VERSION 5.8 ;
BUSBITCHARS "[]" ;
DIVIDERCHAR "/" ;
UNITS
    DATABASE MICRONS 1000 ;
END UNITS

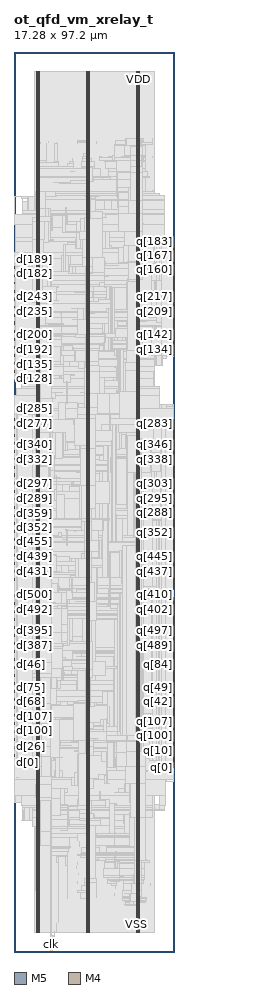
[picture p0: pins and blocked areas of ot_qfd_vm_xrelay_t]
MACRO ot_qfd_vm_xrelay_t
  FOREIGN ot_qfd_vm_xrelay_t 0 0 ;
  CLASS BLOCK ;
  SIZE 17.28 BY 97.2 ;
  PIN clk
    DIRECTION INPUT ;
    USE SIGNAL ;
    PORT
      LAYER M5 ;
        RECT  3.984 0 4.008 0.084 ;
    END
  END clk
  PIN d[0]
    DIRECTION INPUT ;
    USE SIGNAL ;
    PORT
      LAYER M4 ;
        RECT  0 20.496 0.084 20.52 ;
    END
  END d[0]
  PIN d[100]
    DIRECTION INPUT ;
    USE SIGNAL ;
    PORT
      LAYER M4 ;
        RECT  0 23.952 0.084 23.976 ;
    END
  END d[100]
  PIN d[101]
    DIRECTION INPUT ;
    USE SIGNAL ;
    PORT
      LAYER M4 ;
        RECT  0 24.048 0.084 24.072 ;
    END
  END d[101]
  PIN d[102]
    DIRECTION INPUT ;
    USE SIGNAL ;
    PORT
      LAYER M4 ;
        RECT  0 24.144 0.084 24.168 ;
    END
  END d[102]
  PIN d[103]
    DIRECTION INPUT ;
    USE SIGNAL ;
    PORT
      LAYER M4 ;
        RECT  0 24.24 0.084 24.264 ;
    END
  END d[103]
  PIN d[104]
    DIRECTION INPUT ;
    USE SIGNAL ;
    PORT
      LAYER M4 ;
        RECT  0 24.336 0.084 24.36 ;
    END
  END d[104]
  PIN d[105]
    DIRECTION INPUT ;
    USE SIGNAL ;
    PORT
      LAYER M4 ;
        RECT  0 24.432 0.084 24.456 ;
    END
  END d[105]
  PIN d[106]
    DIRECTION INPUT ;
    USE SIGNAL ;
    PORT
      LAYER M4 ;
        RECT  0 24.528 0.084 24.552 ;
    END
  END d[106]
  PIN d[107]
    DIRECTION INPUT ;
    USE SIGNAL ;
    PORT
      LAYER M4 ;
        RECT  0 24.624 0.084 24.648 ;
    END
  END d[107]
  PIN d[108]
    DIRECTION INPUT ;
    USE SIGNAL ;
    PORT
      LAYER M4 ;
        RECT  0 24.72 0.084 24.744 ;
    END
  END d[108]
  PIN d[109]
    DIRECTION INPUT ;
    USE SIGNAL ;
    PORT
      LAYER M4 ;
        RECT  0 24.816 0.084 24.84 ;
    END
  END d[109]
  PIN d[10]
    DIRECTION INPUT ;
    USE SIGNAL ;
    PORT
      LAYER M4 ;
        RECT  0 21.456 0.084 21.48 ;
    END
  END d[10]
  PIN d[110]
    DIRECTION INPUT ;
    USE SIGNAL ;
    PORT
      LAYER M4 ;
        RECT  0 24.912 0.084 24.936 ;
    END
  END d[110]
  PIN d[111]
    DIRECTION INPUT ;
    USE SIGNAL ;
    PORT
      LAYER M4 ;
        RECT  0 25.008 0.084 25.032 ;
    END
  END d[111]
  PIN d[112]
    DIRECTION INPUT ;
    USE SIGNAL ;
    PORT
      LAYER M4 ;
        RECT  0 25.104 0.084 25.128 ;
    END
  END d[112]
  PIN d[113]
    DIRECTION INPUT ;
    USE SIGNAL ;
    PORT
      LAYER M4 ;
        RECT  0 25.2 0.084 25.224 ;
    END
  END d[113]
  PIN d[114]
    DIRECTION INPUT ;
    USE SIGNAL ;
    PORT
      LAYER M4 ;
        RECT  0 25.296 0.084 25.32 ;
    END
  END d[114]
  PIN d[115]
    DIRECTION INPUT ;
    USE SIGNAL ;
    PORT
      LAYER M4 ;
        RECT  0 25.392 0.084 25.416 ;
    END
  END d[115]
  PIN d[116]
    DIRECTION INPUT ;
    USE SIGNAL ;
    PORT
      LAYER M4 ;
        RECT  0 25.488 0.084 25.512 ;
    END
  END d[116]
  PIN d[117]
    DIRECTION INPUT ;
    USE SIGNAL ;
    PORT
      LAYER M4 ;
        RECT  0 25.584 0.084 25.608 ;
    END
  END d[117]
  PIN d[118]
    DIRECTION INPUT ;
    USE SIGNAL ;
    PORT
      LAYER M4 ;
        RECT  0 25.68 0.084 25.704 ;
    END
  END d[118]
  PIN d[119]
    DIRECTION INPUT ;
    USE SIGNAL ;
    PORT
      LAYER M4 ;
        RECT  0 25.776 0.084 25.8 ;
    END
  END d[119]
  PIN d[11]
    DIRECTION INPUT ;
    USE SIGNAL ;
    PORT
      LAYER M4 ;
        RECT  0 21.552 0.084 21.576 ;
    END
  END d[11]
  PIN d[120]
    DIRECTION INPUT ;
    USE SIGNAL ;
    PORT
      LAYER M4 ;
        RECT  0 25.872 0.084 25.896 ;
    END
  END d[120]
  PIN d[121]
    DIRECTION INPUT ;
    USE SIGNAL ;
    PORT
      LAYER M4 ;
        RECT  0 25.968 0.084 25.992 ;
    END
  END d[121]
  PIN d[122]
    DIRECTION INPUT ;
    USE SIGNAL ;
    PORT
      LAYER M4 ;
        RECT  0 26.064 0.084 26.088 ;
    END
  END d[122]
  PIN d[123]
    DIRECTION INPUT ;
    USE SIGNAL ;
    PORT
      LAYER M4 ;
        RECT  0 26.16 0.084 26.184 ;
    END
  END d[123]
  PIN d[124]
    DIRECTION INPUT ;
    USE SIGNAL ;
    PORT
      LAYER M4 ;
        RECT  0 26.256 0.084 26.28 ;
    END
  END d[124]
  PIN d[125]
    DIRECTION INPUT ;
    USE SIGNAL ;
    PORT
      LAYER M4 ;
        RECT  0 26.352 0.084 26.376 ;
    END
  END d[125]
  PIN d[126]
    DIRECTION INPUT ;
    USE SIGNAL ;
    PORT
      LAYER M4 ;
        RECT  0 26.448 0.084 26.472 ;
    END
  END d[126]
  PIN d[127]
    DIRECTION INPUT ;
    USE SIGNAL ;
    PORT
      LAYER M4 ;
        RECT  0 26.544 0.084 26.568 ;
    END
  END d[127]
  PIN d[128]
    DIRECTION INPUT ;
    USE SIGNAL ;
    PORT
      LAYER M4 ;
        RECT  0 61.968 0.084 61.992 ;
    END
  END d[128]
  PIN d[129]
    DIRECTION INPUT ;
    USE SIGNAL ;
    PORT
      LAYER M4 ;
        RECT  0 62.064 0.084 62.088 ;
    END
  END d[129]
  PIN d[12]
    DIRECTION INPUT ;
    USE SIGNAL ;
    PORT
      LAYER M4 ;
        RECT  0 21.648 0.084 21.672 ;
    END
  END d[12]
  PIN d[130]
    DIRECTION INPUT ;
    USE SIGNAL ;
    PORT
      LAYER M4 ;
        RECT  0 62.16 0.084 62.184 ;
    END
  END d[130]
  PIN d[131]
    DIRECTION INPUT ;
    USE SIGNAL ;
    PORT
      LAYER M4 ;
        RECT  0 62.256 0.084 62.28 ;
    END
  END d[131]
  PIN d[132]
    DIRECTION INPUT ;
    USE SIGNAL ;
    PORT
      LAYER M4 ;
        RECT  0 62.352 0.084 62.376 ;
    END
  END d[132]
  PIN d[133]
    DIRECTION INPUT ;
    USE SIGNAL ;
    PORT
      LAYER M4 ;
        RECT  0 62.448 0.084 62.472 ;
    END
  END d[133]
  PIN d[134]
    DIRECTION INPUT ;
    USE SIGNAL ;
    PORT
      LAYER M4 ;
        RECT  0 62.544 0.084 62.568 ;
    END
  END d[134]
  PIN d[135]
    DIRECTION INPUT ;
    USE SIGNAL ;
    PORT
      LAYER M4 ;
        RECT  0 62.64 0.084 62.664 ;
    END
  END d[135]
  PIN d[136]
    DIRECTION INPUT ;
    USE SIGNAL ;
    PORT
      LAYER M4 ;
        RECT  0 62.736 0.084 62.76 ;
    END
  END d[136]
  PIN d[137]
    DIRECTION INPUT ;
    USE SIGNAL ;
    PORT
      LAYER M4 ;
        RECT  0 62.832 0.084 62.856 ;
    END
  END d[137]
  PIN d[138]
    DIRECTION INPUT ;
    USE SIGNAL ;
    PORT
      LAYER M4 ;
        RECT  0 62.928 0.084 62.952 ;
    END
  END d[138]
  PIN d[139]
    DIRECTION INPUT ;
    USE SIGNAL ;
    PORT
      LAYER M4 ;
        RECT  0 63.024 0.084 63.048 ;
    END
  END d[139]
  PIN d[13]
    DIRECTION INPUT ;
    USE SIGNAL ;
    PORT
      LAYER M4 ;
        RECT  0 21.744 0.084 21.768 ;
    END
  END d[13]
  PIN d[140]
    DIRECTION INPUT ;
    USE SIGNAL ;
    PORT
      LAYER M4 ;
        RECT  0 63.12 0.084 63.144 ;
    END
  END d[140]
  PIN d[141]
    DIRECTION INPUT ;
    USE SIGNAL ;
    PORT
      LAYER M4 ;
        RECT  0 63.216 0.084 63.24 ;
    END
  END d[141]
  PIN d[142]
    DIRECTION INPUT ;
    USE SIGNAL ;
    PORT
      LAYER M4 ;
        RECT  0 63.312 0.084 63.336 ;
    END
  END d[142]
  PIN d[143]
    DIRECTION INPUT ;
    USE SIGNAL ;
    PORT
      LAYER M4 ;
        RECT  0 63.408 0.084 63.432 ;
    END
  END d[143]
  PIN d[144]
    DIRECTION INPUT ;
    USE SIGNAL ;
    PORT
      LAYER M4 ;
        RECT  0 63.504 0.084 63.528 ;
    END
  END d[144]
  PIN d[145]
    DIRECTION INPUT ;
    USE SIGNAL ;
    PORT
      LAYER M4 ;
        RECT  0 63.6 0.084 63.624 ;
    END
  END d[145]
  PIN d[146]
    DIRECTION INPUT ;
    USE SIGNAL ;
    PORT
      LAYER M4 ;
        RECT  0 63.696 0.084 63.72 ;
    END
  END d[146]
  PIN d[147]
    DIRECTION INPUT ;
    USE SIGNAL ;
    PORT
      LAYER M4 ;
        RECT  0 63.792 0.084 63.816 ;
    END
  END d[147]
  PIN d[148]
    DIRECTION INPUT ;
    USE SIGNAL ;
    PORT
      LAYER M4 ;
        RECT  0 63.888 0.084 63.912 ;
    END
  END d[148]
  PIN d[149]
    DIRECTION INPUT ;
    USE SIGNAL ;
    PORT
      LAYER M4 ;
        RECT  0 63.984 0.084 64.008 ;
    END
  END d[149]
  PIN d[14]
    DIRECTION INPUT ;
    USE SIGNAL ;
    PORT
      LAYER M4 ;
        RECT  0 21.84 0.084 21.864 ;
    END
  END d[14]
  PIN d[150]
    DIRECTION INPUT ;
    USE SIGNAL ;
    PORT
      LAYER M4 ;
        RECT  0 64.08 0.084 64.104 ;
    END
  END d[150]
  PIN d[151]
    DIRECTION INPUT ;
    USE SIGNAL ;
    PORT
      LAYER M4 ;
        RECT  0 64.176 0.084 64.2 ;
    END
  END d[151]
  PIN d[152]
    DIRECTION INPUT ;
    USE SIGNAL ;
    PORT
      LAYER M4 ;
        RECT  0 64.272 0.084 64.296 ;
    END
  END d[152]
  PIN d[153]
    DIRECTION INPUT ;
    USE SIGNAL ;
    PORT
      LAYER M4 ;
        RECT  0 64.368 0.084 64.392 ;
    END
  END d[153]
  PIN d[154]
    DIRECTION INPUT ;
    USE SIGNAL ;
    PORT
      LAYER M4 ;
        RECT  0 64.464 0.084 64.488 ;
    END
  END d[154]
  PIN d[155]
    DIRECTION INPUT ;
    USE SIGNAL ;
    PORT
      LAYER M4 ;
        RECT  0 64.56 0.084 64.584 ;
    END
  END d[155]
  PIN d[156]
    DIRECTION INPUT ;
    USE SIGNAL ;
    PORT
      LAYER M4 ;
        RECT  0 64.656 0.084 64.68 ;
    END
  END d[156]
  PIN d[157]
    DIRECTION INPUT ;
    USE SIGNAL ;
    PORT
      LAYER M4 ;
        RECT  0 64.752 0.084 64.776 ;
    END
  END d[157]
  PIN d[158]
    DIRECTION INPUT ;
    USE SIGNAL ;
    PORT
      LAYER M4 ;
        RECT  0 64.848 0.084 64.872 ;
    END
  END d[158]
  PIN d[159]
    DIRECTION INPUT ;
    USE SIGNAL ;
    PORT
      LAYER M4 ;
        RECT  0 64.944 0.084 64.968 ;
    END
  END d[159]
  PIN d[15]
    DIRECTION INPUT ;
    USE SIGNAL ;
    PORT
      LAYER M4 ;
        RECT  0 21.936 0.084 21.96 ;
    END
  END d[15]
  PIN d[160]
    DIRECTION INPUT ;
    USE SIGNAL ;
    PORT
      LAYER M4 ;
        RECT  0 71.184 0.084 71.208 ;
    END
  END d[160]
  PIN d[161]
    DIRECTION INPUT ;
    USE SIGNAL ;
    PORT
      LAYER M4 ;
        RECT  0 71.28 0.084 71.304 ;
    END
  END d[161]
  PIN d[162]
    DIRECTION INPUT ;
    USE SIGNAL ;
    PORT
      LAYER M4 ;
        RECT  0 71.376 0.084 71.4 ;
    END
  END d[162]
  PIN d[163]
    DIRECTION INPUT ;
    USE SIGNAL ;
    PORT
      LAYER M4 ;
        RECT  0 71.472 0.084 71.496 ;
    END
  END d[163]
  PIN d[164]
    DIRECTION INPUT ;
    USE SIGNAL ;
    PORT
      LAYER M4 ;
        RECT  0 71.568 0.084 71.592 ;
    END
  END d[164]
  PIN d[165]
    DIRECTION INPUT ;
    USE SIGNAL ;
    PORT
      LAYER M4 ;
        RECT  0 71.664 0.084 71.688 ;
    END
  END d[165]
  PIN d[166]
    DIRECTION INPUT ;
    USE SIGNAL ;
    PORT
      LAYER M4 ;
        RECT  0 71.76 0.084 71.784 ;
    END
  END d[166]
  PIN d[167]
    DIRECTION INPUT ;
    USE SIGNAL ;
    PORT
      LAYER M4 ;
        RECT  0 71.856 0.084 71.88 ;
    END
  END d[167]
  PIN d[168]
    DIRECTION INPUT ;
    USE SIGNAL ;
    PORT
      LAYER M4 ;
        RECT  0 71.952 0.084 71.976 ;
    END
  END d[168]
  PIN d[169]
    DIRECTION INPUT ;
    USE SIGNAL ;
    PORT
      LAYER M4 ;
        RECT  0 72.048 0.084 72.072 ;
    END
  END d[169]
  PIN d[16]
    DIRECTION INPUT ;
    USE SIGNAL ;
    PORT
      LAYER M4 ;
        RECT  0 22.032 0.084 22.056 ;
    END
  END d[16]
  PIN d[170]
    DIRECTION INPUT ;
    USE SIGNAL ;
    PORT
      LAYER M4 ;
        RECT  0 72.144 0.084 72.168 ;
    END
  END d[170]
  PIN d[171]
    DIRECTION INPUT ;
    USE SIGNAL ;
    PORT
      LAYER M4 ;
        RECT  0 72.24 0.084 72.264 ;
    END
  END d[171]
  PIN d[172]
    DIRECTION INPUT ;
    USE SIGNAL ;
    PORT
      LAYER M4 ;
        RECT  0 72.336 0.084 72.36 ;
    END
  END d[172]
  PIN d[173]
    DIRECTION INPUT ;
    USE SIGNAL ;
    PORT
      LAYER M4 ;
        RECT  0 72.432 0.084 72.456 ;
    END
  END d[173]
  PIN d[174]
    DIRECTION INPUT ;
    USE SIGNAL ;
    PORT
      LAYER M4 ;
        RECT  0 72.528 0.084 72.552 ;
    END
  END d[174]
  PIN d[175]
    DIRECTION INPUT ;
    USE SIGNAL ;
    PORT
      LAYER M4 ;
        RECT  0 72.624 0.084 72.648 ;
    END
  END d[175]
  PIN d[176]
    DIRECTION INPUT ;
    USE SIGNAL ;
    PORT
      LAYER M4 ;
        RECT  0 72.72 0.084 72.744 ;
    END
  END d[176]
  PIN d[177]
    DIRECTION INPUT ;
    USE SIGNAL ;
    PORT
      LAYER M4 ;
        RECT  0 72.816 0.084 72.84 ;
    END
  END d[177]
  PIN d[178]
    DIRECTION INPUT ;
    USE SIGNAL ;
    PORT
      LAYER M4 ;
        RECT  0 72.912 0.084 72.936 ;
    END
  END d[178]
  PIN d[179]
    DIRECTION INPUT ;
    USE SIGNAL ;
    PORT
      LAYER M4 ;
        RECT  0 73.008 0.084 73.032 ;
    END
  END d[179]
  PIN d[17]
    DIRECTION INPUT ;
    USE SIGNAL ;
    PORT
      LAYER M4 ;
        RECT  0 22.128 0.084 22.152 ;
    END
  END d[17]
  PIN d[180]
    DIRECTION INPUT ;
    USE SIGNAL ;
    PORT
      LAYER M4 ;
        RECT  0 73.104 0.084 73.128 ;
    END
  END d[180]
  PIN d[181]
    DIRECTION INPUT ;
    USE SIGNAL ;
    PORT
      LAYER M4 ;
        RECT  0 73.2 0.084 73.224 ;
    END
  END d[181]
  PIN d[182]
    DIRECTION INPUT ;
    USE SIGNAL ;
    PORT
      LAYER M4 ;
        RECT  0 73.296 0.084 73.32 ;
    END
  END d[182]
  PIN d[183]
    DIRECTION INPUT ;
    USE SIGNAL ;
    PORT
      LAYER M4 ;
        RECT  0 73.392 0.084 73.416 ;
    END
  END d[183]
  PIN d[184]
    DIRECTION INPUT ;
    USE SIGNAL ;
    PORT
      LAYER M4 ;
        RECT  0 73.488 0.084 73.512 ;
    END
  END d[184]
  PIN d[185]
    DIRECTION INPUT ;
    USE SIGNAL ;
    PORT
      LAYER M4 ;
        RECT  0 73.584 0.084 73.608 ;
    END
  END d[185]
  PIN d[186]
    DIRECTION INPUT ;
    USE SIGNAL ;
    PORT
      LAYER M4 ;
        RECT  0 73.68 0.084 73.704 ;
    END
  END d[186]
  PIN d[187]
    DIRECTION INPUT ;
    USE SIGNAL ;
    PORT
      LAYER M4 ;
        RECT  0 73.776 0.084 73.8 ;
    END
  END d[187]
  PIN d[188]
    DIRECTION INPUT ;
    USE SIGNAL ;
    PORT
      LAYER M4 ;
        RECT  0 73.872 0.084 73.896 ;
    END
  END d[188]
  PIN d[189]
    DIRECTION INPUT ;
    USE SIGNAL ;
    PORT
      LAYER M4 ;
        RECT  0 73.968 0.084 73.992 ;
    END
  END d[189]
  PIN d[18]
    DIRECTION INPUT ;
    USE SIGNAL ;
    PORT
      LAYER M4 ;
        RECT  0 22.224 0.084 22.248 ;
    END
  END d[18]
  PIN d[190]
    DIRECTION INPUT ;
    USE SIGNAL ;
    PORT
      LAYER M4 ;
        RECT  0 74.064 0.084 74.088 ;
    END
  END d[190]
  PIN d[191]
    DIRECTION INPUT ;
    USE SIGNAL ;
    PORT
      LAYER M4 ;
        RECT  0 74.16 0.084 74.184 ;
    END
  END d[191]
  PIN d[192]
    DIRECTION INPUT ;
    USE SIGNAL ;
    PORT
      LAYER M4 ;
        RECT  0 65.04 0.084 65.064 ;
    END
  END d[192]
  PIN d[193]
    DIRECTION INPUT ;
    USE SIGNAL ;
    PORT
      LAYER M4 ;
        RECT  0 65.136 0.084 65.16 ;
    END
  END d[193]
  PIN d[194]
    DIRECTION INPUT ;
    USE SIGNAL ;
    PORT
      LAYER M4 ;
        RECT  0 65.232 0.084 65.256 ;
    END
  END d[194]
  PIN d[195]
    DIRECTION INPUT ;
    USE SIGNAL ;
    PORT
      LAYER M4 ;
        RECT  0 65.328 0.084 65.352 ;
    END
  END d[195]
  PIN d[196]
    DIRECTION INPUT ;
    USE SIGNAL ;
    PORT
      LAYER M4 ;
        RECT  0 65.424 0.084 65.448 ;
    END
  END d[196]
  PIN d[197]
    DIRECTION INPUT ;
    USE SIGNAL ;
    PORT
      LAYER M4 ;
        RECT  0 65.52 0.084 65.544 ;
    END
  END d[197]
  PIN d[198]
    DIRECTION INPUT ;
    USE SIGNAL ;
    PORT
      LAYER M4 ;
        RECT  0 65.616 0.084 65.64 ;
    END
  END d[198]
  PIN d[199]
    DIRECTION INPUT ;
    USE SIGNAL ;
    PORT
      LAYER M4 ;
        RECT  0 65.712 0.084 65.736 ;
    END
  END d[199]
  PIN d[19]
    DIRECTION INPUT ;
    USE SIGNAL ;
    PORT
      LAYER M4 ;
        RECT  0 22.32 0.084 22.344 ;
    END
  END d[19]
  PIN d[1]
    DIRECTION INPUT ;
    USE SIGNAL ;
    PORT
      LAYER M4 ;
        RECT  0 20.592 0.084 20.616 ;
    END
  END d[1]
  PIN d[200]
    DIRECTION INPUT ;
    USE SIGNAL ;
    PORT
      LAYER M4 ;
        RECT  0 65.808 0.084 65.832 ;
    END
  END d[200]
  PIN d[201]
    DIRECTION INPUT ;
    USE SIGNAL ;
    PORT
      LAYER M4 ;
        RECT  0 65.904 0.084 65.928 ;
    END
  END d[201]
  PIN d[202]
    DIRECTION INPUT ;
    USE SIGNAL ;
    PORT
      LAYER M4 ;
        RECT  0 66 0.084 66.024 ;
    END
  END d[202]
  PIN d[203]
    DIRECTION INPUT ;
    USE SIGNAL ;
    PORT
      LAYER M4 ;
        RECT  0 66.096 0.084 66.12 ;
    END
  END d[203]
  PIN d[204]
    DIRECTION INPUT ;
    USE SIGNAL ;
    PORT
      LAYER M4 ;
        RECT  0 66.192 0.084 66.216 ;
    END
  END d[204]
  PIN d[205]
    DIRECTION INPUT ;
    USE SIGNAL ;
    PORT
      LAYER M4 ;
        RECT  0 66.288 0.084 66.312 ;
    END
  END d[205]
  PIN d[206]
    DIRECTION INPUT ;
    USE SIGNAL ;
    PORT
      LAYER M4 ;
        RECT  0 66.384 0.084 66.408 ;
    END
  END d[206]
  PIN d[207]
    DIRECTION INPUT ;
    USE SIGNAL ;
    PORT
      LAYER M4 ;
        RECT  0 66.48 0.084 66.504 ;
    END
  END d[207]
  PIN d[208]
    DIRECTION INPUT ;
    USE SIGNAL ;
    PORT
      LAYER M4 ;
        RECT  0 66.576 0.084 66.6 ;
    END
  END d[208]
  PIN d[209]
    DIRECTION INPUT ;
    USE SIGNAL ;
    PORT
      LAYER M4 ;
        RECT  0 66.672 0.084 66.696 ;
    END
  END d[209]
  PIN d[20]
    DIRECTION INPUT ;
    USE SIGNAL ;
    PORT
      LAYER M4 ;
        RECT  0 22.416 0.084 22.44 ;
    END
  END d[20]
  PIN d[210]
    DIRECTION INPUT ;
    USE SIGNAL ;
    PORT
      LAYER M4 ;
        RECT  0 66.768 0.084 66.792 ;
    END
  END d[210]
  PIN d[211]
    DIRECTION INPUT ;
    USE SIGNAL ;
    PORT
      LAYER M4 ;
        RECT  0 66.864 0.084 66.888 ;
    END
  END d[211]
  PIN d[212]
    DIRECTION INPUT ;
    USE SIGNAL ;
    PORT
      LAYER M4 ;
        RECT  0 66.96 0.084 66.984 ;
    END
  END d[212]
  PIN d[213]
    DIRECTION INPUT ;
    USE SIGNAL ;
    PORT
      LAYER M4 ;
        RECT  0 67.056 0.084 67.08 ;
    END
  END d[213]
  PIN d[214]
    DIRECTION INPUT ;
    USE SIGNAL ;
    PORT
      LAYER M4 ;
        RECT  0 67.152 0.084 67.176 ;
    END
  END d[214]
  PIN d[215]
    DIRECTION INPUT ;
    USE SIGNAL ;
    PORT
      LAYER M4 ;
        RECT  0 67.248 0.084 67.272 ;
    END
  END d[215]
  PIN d[216]
    DIRECTION INPUT ;
    USE SIGNAL ;
    PORT
      LAYER M4 ;
        RECT  0 67.344 0.084 67.368 ;
    END
  END d[216]
  PIN d[217]
    DIRECTION INPUT ;
    USE SIGNAL ;
    PORT
      LAYER M4 ;
        RECT  0 67.44 0.084 67.464 ;
    END
  END d[217]
  PIN d[218]
    DIRECTION INPUT ;
    USE SIGNAL ;
    PORT
      LAYER M4 ;
        RECT  0 67.536 0.084 67.56 ;
    END
  END d[218]
  PIN d[219]
    DIRECTION INPUT ;
    USE SIGNAL ;
    PORT
      LAYER M4 ;
        RECT  0 67.632 0.084 67.656 ;
    END
  END d[219]
  PIN d[21]
    DIRECTION INPUT ;
    USE SIGNAL ;
    PORT
      LAYER M4 ;
        RECT  0 22.512 0.084 22.536 ;
    END
  END d[21]
  PIN d[220]
    DIRECTION INPUT ;
    USE SIGNAL ;
    PORT
      LAYER M4 ;
        RECT  0 67.728 0.084 67.752 ;
    END
  END d[220]
  PIN d[221]
    DIRECTION INPUT ;
    USE SIGNAL ;
    PORT
      LAYER M4 ;
        RECT  0 67.824 0.084 67.848 ;
    END
  END d[221]
  PIN d[222]
    DIRECTION INPUT ;
    USE SIGNAL ;
    PORT
      LAYER M4 ;
        RECT  0 67.92 0.084 67.944 ;
    END
  END d[222]
  PIN d[223]
    DIRECTION INPUT ;
    USE SIGNAL ;
    PORT
      LAYER M4 ;
        RECT  0 68.016 0.084 68.04 ;
    END
  END d[223]
  PIN d[224]
    DIRECTION INPUT ;
    USE SIGNAL ;
    PORT
      LAYER M4 ;
        RECT  0 68.112 0.084 68.136 ;
    END
  END d[224]
  PIN d[225]
    DIRECTION INPUT ;
    USE SIGNAL ;
    PORT
      LAYER M4 ;
        RECT  0 68.208 0.084 68.232 ;
    END
  END d[225]
  PIN d[226]
    DIRECTION INPUT ;
    USE SIGNAL ;
    PORT
      LAYER M4 ;
        RECT  0 68.304 0.084 68.328 ;
    END
  END d[226]
  PIN d[227]
    DIRECTION INPUT ;
    USE SIGNAL ;
    PORT
      LAYER M4 ;
        RECT  0 68.4 0.084 68.424 ;
    END
  END d[227]
  PIN d[228]
    DIRECTION INPUT ;
    USE SIGNAL ;
    PORT
      LAYER M4 ;
        RECT  0 68.496 0.084 68.52 ;
    END
  END d[228]
  PIN d[229]
    DIRECTION INPUT ;
    USE SIGNAL ;
    PORT
      LAYER M4 ;
        RECT  0 68.592 0.084 68.616 ;
    END
  END d[229]
  PIN d[22]
    DIRECTION INPUT ;
    USE SIGNAL ;
    PORT
      LAYER M4 ;
        RECT  0 22.608 0.084 22.632 ;
    END
  END d[22]
  PIN d[230]
    DIRECTION INPUT ;
    USE SIGNAL ;
    PORT
      LAYER M4 ;
        RECT  0 68.688 0.084 68.712 ;
    END
  END d[230]
  PIN d[231]
    DIRECTION INPUT ;
    USE SIGNAL ;
    PORT
      LAYER M4 ;
        RECT  0 68.784 0.084 68.808 ;
    END
  END d[231]
  PIN d[232]
    DIRECTION INPUT ;
    USE SIGNAL ;
    PORT
      LAYER M4 ;
        RECT  0 68.88 0.084 68.904 ;
    END
  END d[232]
  PIN d[233]
    DIRECTION INPUT ;
    USE SIGNAL ;
    PORT
      LAYER M4 ;
        RECT  0 68.976 0.084 69 ;
    END
  END d[233]
  PIN d[234]
    DIRECTION INPUT ;
    USE SIGNAL ;
    PORT
      LAYER M4 ;
        RECT  0 69.072 0.084 69.096 ;
    END
  END d[234]
  PIN d[235]
    DIRECTION INPUT ;
    USE SIGNAL ;
    PORT
      LAYER M4 ;
        RECT  0 69.168 0.084 69.192 ;
    END
  END d[235]
  PIN d[236]
    DIRECTION INPUT ;
    USE SIGNAL ;
    PORT
      LAYER M4 ;
        RECT  0 69.264 0.084 69.288 ;
    END
  END d[236]
  PIN d[237]
    DIRECTION INPUT ;
    USE SIGNAL ;
    PORT
      LAYER M4 ;
        RECT  0 69.36 0.084 69.384 ;
    END
  END d[237]
  PIN d[238]
    DIRECTION INPUT ;
    USE SIGNAL ;
    PORT
      LAYER M4 ;
        RECT  0 69.456 0.084 69.48 ;
    END
  END d[238]
  PIN d[239]
    DIRECTION INPUT ;
    USE SIGNAL ;
    PORT
      LAYER M4 ;
        RECT  0 69.552 0.084 69.576 ;
    END
  END d[239]
  PIN d[23]
    DIRECTION INPUT ;
    USE SIGNAL ;
    PORT
      LAYER M4 ;
        RECT  0 22.704 0.084 22.728 ;
    END
  END d[23]
  PIN d[240]
    DIRECTION INPUT ;
    USE SIGNAL ;
    PORT
      LAYER M4 ;
        RECT  0 69.648 0.084 69.672 ;
    END
  END d[240]
  PIN d[241]
    DIRECTION INPUT ;
    USE SIGNAL ;
    PORT
      LAYER M4 ;
        RECT  0 69.744 0.084 69.768 ;
    END
  END d[241]
  PIN d[242]
    DIRECTION INPUT ;
    USE SIGNAL ;
    PORT
      LAYER M4 ;
        RECT  0 69.84 0.084 69.864 ;
    END
  END d[242]
  PIN d[243]
    DIRECTION INPUT ;
    USE SIGNAL ;
    PORT
      LAYER M4 ;
        RECT  0 69.936 0.084 69.96 ;
    END
  END d[243]
  PIN d[244]
    DIRECTION INPUT ;
    USE SIGNAL ;
    PORT
      LAYER M4 ;
        RECT  0 70.032 0.084 70.056 ;
    END
  END d[244]
  PIN d[245]
    DIRECTION INPUT ;
    USE SIGNAL ;
    PORT
      LAYER M4 ;
        RECT  0 70.128 0.084 70.152 ;
    END
  END d[245]
  PIN d[246]
    DIRECTION INPUT ;
    USE SIGNAL ;
    PORT
      LAYER M4 ;
        RECT  0 70.224 0.084 70.248 ;
    END
  END d[246]
  PIN d[247]
    DIRECTION INPUT ;
    USE SIGNAL ;
    PORT
      LAYER M4 ;
        RECT  0 70.32 0.084 70.344 ;
    END
  END d[247]
  PIN d[248]
    DIRECTION INPUT ;
    USE SIGNAL ;
    PORT
      LAYER M4 ;
        RECT  0 70.416 0.084 70.44 ;
    END
  END d[248]
  PIN d[249]
    DIRECTION INPUT ;
    USE SIGNAL ;
    PORT
      LAYER M4 ;
        RECT  0 70.512 0.084 70.536 ;
    END
  END d[249]
  PIN d[24]
    DIRECTION INPUT ;
    USE SIGNAL ;
    PORT
      LAYER M4 ;
        RECT  0 22.8 0.084 22.824 ;
    END
  END d[24]
  PIN d[250]
    DIRECTION INPUT ;
    USE SIGNAL ;
    PORT
      LAYER M4 ;
        RECT  0 70.608 0.084 70.632 ;
    END
  END d[250]
  PIN d[251]
    DIRECTION INPUT ;
    USE SIGNAL ;
    PORT
      LAYER M4 ;
        RECT  0 70.704 0.084 70.728 ;
    END
  END d[251]
  PIN d[252]
    DIRECTION INPUT ;
    USE SIGNAL ;
    PORT
      LAYER M4 ;
        RECT  0 70.8 0.084 70.824 ;
    END
  END d[252]
  PIN d[253]
    DIRECTION INPUT ;
    USE SIGNAL ;
    PORT
      LAYER M4 ;
        RECT  0 70.896 0.084 70.92 ;
    END
  END d[253]
  PIN d[254]
    DIRECTION INPUT ;
    USE SIGNAL ;
    PORT
      LAYER M4 ;
        RECT  0 70.992 0.084 71.016 ;
    END
  END d[254]
  PIN d[255]
    DIRECTION INPUT ;
    USE SIGNAL ;
    PORT
      LAYER M4 ;
        RECT  0 71.088 0.084 71.112 ;
    END
  END d[255]
  PIN d[256]
    DIRECTION INPUT ;
    USE SIGNAL ;
    PORT
      LAYER M4 ;
        RECT  0 55.056 0.084 55.08 ;
    END
  END d[256]
  PIN d[257]
    DIRECTION INPUT ;
    USE SIGNAL ;
    PORT
      LAYER M4 ;
        RECT  0 55.152 0.084 55.176 ;
    END
  END d[257]
  PIN d[258]
    DIRECTION INPUT ;
    USE SIGNAL ;
    PORT
      LAYER M4 ;
        RECT  0 55.248 0.084 55.272 ;
    END
  END d[258]
  PIN d[259]
    DIRECTION INPUT ;
    USE SIGNAL ;
    PORT
      LAYER M4 ;
        RECT  0 55.344 0.084 55.368 ;
    END
  END d[259]
  PIN d[25]
    DIRECTION INPUT ;
    USE SIGNAL ;
    PORT
      LAYER M4 ;
        RECT  0 22.896 0.084 22.92 ;
    END
  END d[25]
  PIN d[260]
    DIRECTION INPUT ;
    USE SIGNAL ;
    PORT
      LAYER M4 ;
        RECT  0 55.44 0.084 55.464 ;
    END
  END d[260]
  PIN d[261]
    DIRECTION INPUT ;
    USE SIGNAL ;
    PORT
      LAYER M4 ;
        RECT  0 55.536 0.084 55.56 ;
    END
  END d[261]
  PIN d[262]
    DIRECTION INPUT ;
    USE SIGNAL ;
    PORT
      LAYER M4 ;
        RECT  0 55.632 0.084 55.656 ;
    END
  END d[262]
  PIN d[263]
    DIRECTION INPUT ;
    USE SIGNAL ;
    PORT
      LAYER M4 ;
        RECT  0 55.728 0.084 55.752 ;
    END
  END d[263]
  PIN d[264]
    DIRECTION INPUT ;
    USE SIGNAL ;
    PORT
      LAYER M4 ;
        RECT  0 55.824 0.084 55.848 ;
    END
  END d[264]
  PIN d[265]
    DIRECTION INPUT ;
    USE SIGNAL ;
    PORT
      LAYER M4 ;
        RECT  0 55.92 0.084 55.944 ;
    END
  END d[265]
  PIN d[266]
    DIRECTION INPUT ;
    USE SIGNAL ;
    PORT
      LAYER M4 ;
        RECT  0 56.016 0.084 56.04 ;
    END
  END d[266]
  PIN d[267]
    DIRECTION INPUT ;
    USE SIGNAL ;
    PORT
      LAYER M4 ;
        RECT  0 56.112 0.084 56.136 ;
    END
  END d[267]
  PIN d[268]
    DIRECTION INPUT ;
    USE SIGNAL ;
    PORT
      LAYER M4 ;
        RECT  0 56.208 0.084 56.232 ;
    END
  END d[268]
  PIN d[269]
    DIRECTION INPUT ;
    USE SIGNAL ;
    PORT
      LAYER M4 ;
        RECT  0 56.304 0.084 56.328 ;
    END
  END d[269]
  PIN d[26]
    DIRECTION INPUT ;
    USE SIGNAL ;
    PORT
      LAYER M4 ;
        RECT  0 22.992 0.084 23.016 ;
    END
  END d[26]
  PIN d[270]
    DIRECTION INPUT ;
    USE SIGNAL ;
    PORT
      LAYER M4 ;
        RECT  0 56.4 0.084 56.424 ;
    END
  END d[270]
  PIN d[271]
    DIRECTION INPUT ;
    USE SIGNAL ;
    PORT
      LAYER M4 ;
        RECT  0 56.496 0.084 56.52 ;
    END
  END d[271]
  PIN d[272]
    DIRECTION INPUT ;
    USE SIGNAL ;
    PORT
      LAYER M4 ;
        RECT  0 56.592 0.084 56.616 ;
    END
  END d[272]
  PIN d[273]
    DIRECTION INPUT ;
    USE SIGNAL ;
    PORT
      LAYER M4 ;
        RECT  0 56.688 0.084 56.712 ;
    END
  END d[273]
  PIN d[274]
    DIRECTION INPUT ;
    USE SIGNAL ;
    PORT
      LAYER M4 ;
        RECT  0 56.784 0.084 56.808 ;
    END
  END d[274]
  PIN d[275]
    DIRECTION INPUT ;
    USE SIGNAL ;
    PORT
      LAYER M4 ;
        RECT  0 56.88 0.084 56.904 ;
    END
  END d[275]
  PIN d[276]
    DIRECTION INPUT ;
    USE SIGNAL ;
    PORT
      LAYER M4 ;
        RECT  0 56.976 0.084 57 ;
    END
  END d[276]
  PIN d[277]
    DIRECTION INPUT ;
    USE SIGNAL ;
    PORT
      LAYER M4 ;
        RECT  0 57.072 0.084 57.096 ;
    END
  END d[277]
  PIN d[278]
    DIRECTION INPUT ;
    USE SIGNAL ;
    PORT
      LAYER M4 ;
        RECT  0 57.168 0.084 57.192 ;
    END
  END d[278]
  PIN d[279]
    DIRECTION INPUT ;
    USE SIGNAL ;
    PORT
      LAYER M4 ;
        RECT  0 57.264 0.084 57.288 ;
    END
  END d[279]
  PIN d[27]
    DIRECTION INPUT ;
    USE SIGNAL ;
    PORT
      LAYER M4 ;
        RECT  0 23.088 0.084 23.112 ;
    END
  END d[27]
  PIN d[280]
    DIRECTION INPUT ;
    USE SIGNAL ;
    PORT
      LAYER M4 ;
        RECT  0 57.36 0.084 57.384 ;
    END
  END d[280]
  PIN d[281]
    DIRECTION INPUT ;
    USE SIGNAL ;
    PORT
      LAYER M4 ;
        RECT  0 57.456 0.084 57.48 ;
    END
  END d[281]
  PIN d[282]
    DIRECTION INPUT ;
    USE SIGNAL ;
    PORT
      LAYER M4 ;
        RECT  0 57.552 0.084 57.576 ;
    END
  END d[282]
  PIN d[283]
    DIRECTION INPUT ;
    USE SIGNAL ;
    PORT
      LAYER M4 ;
        RECT  0 57.648 0.084 57.672 ;
    END
  END d[283]
  PIN d[284]
    DIRECTION INPUT ;
    USE SIGNAL ;
    PORT
      LAYER M4 ;
        RECT  0 57.744 0.084 57.768 ;
    END
  END d[284]
  PIN d[285]
    DIRECTION INPUT ;
    USE SIGNAL ;
    PORT
      LAYER M4 ;
        RECT  0 57.84 0.084 57.864 ;
    END
  END d[285]
  PIN d[286]
    DIRECTION INPUT ;
    USE SIGNAL ;
    PORT
      LAYER M4 ;
        RECT  0 57.936 0.084 57.96 ;
    END
  END d[286]
  PIN d[287]
    DIRECTION INPUT ;
    USE SIGNAL ;
    PORT
      LAYER M4 ;
        RECT  0 58.032 0.084 58.056 ;
    END
  END d[287]
  PIN d[288]
    DIRECTION INPUT ;
    USE SIGNAL ;
    PORT
      LAYER M4 ;
        RECT  0 48.912 0.084 48.936 ;
    END
  END d[288]
  PIN d[289]
    DIRECTION INPUT ;
    USE SIGNAL ;
    PORT
      LAYER M4 ;
        RECT  0 49.008 0.084 49.032 ;
    END
  END d[289]
  PIN d[28]
    DIRECTION INPUT ;
    USE SIGNAL ;
    PORT
      LAYER M4 ;
        RECT  0 23.184 0.084 23.208 ;
    END
  END d[28]
  PIN d[290]
    DIRECTION INPUT ;
    USE SIGNAL ;
    PORT
      LAYER M4 ;
        RECT  0 49.104 0.084 49.128 ;
    END
  END d[290]
  PIN d[291]
    DIRECTION INPUT ;
    USE SIGNAL ;
    PORT
      LAYER M4 ;
        RECT  0 49.2 0.084 49.224 ;
    END
  END d[291]
  PIN d[292]
    DIRECTION INPUT ;
    USE SIGNAL ;
    PORT
      LAYER M4 ;
        RECT  0 49.296 0.084 49.32 ;
    END
  END d[292]
  PIN d[293]
    DIRECTION INPUT ;
    USE SIGNAL ;
    PORT
      LAYER M4 ;
        RECT  0 49.392 0.084 49.416 ;
    END
  END d[293]
  PIN d[294]
    DIRECTION INPUT ;
    USE SIGNAL ;
    PORT
      LAYER M4 ;
        RECT  0 49.488 0.084 49.512 ;
    END
  END d[294]
  PIN d[295]
    DIRECTION INPUT ;
    USE SIGNAL ;
    PORT
      LAYER M4 ;
        RECT  0 49.584 0.084 49.608 ;
    END
  END d[295]
  PIN d[296]
    DIRECTION INPUT ;
    USE SIGNAL ;
    PORT
      LAYER M4 ;
        RECT  0 49.68 0.084 49.704 ;
    END
  END d[296]
  PIN d[297]
    DIRECTION INPUT ;
    USE SIGNAL ;
    PORT
      LAYER M4 ;
        RECT  0 49.776 0.084 49.8 ;
    END
  END d[297]
  PIN d[298]
    DIRECTION INPUT ;
    USE SIGNAL ;
    PORT
      LAYER M4 ;
        RECT  0 49.872 0.084 49.896 ;
    END
  END d[298]
  PIN d[299]
    DIRECTION INPUT ;
    USE SIGNAL ;
    PORT
      LAYER M4 ;
        RECT  0 49.968 0.084 49.992 ;
    END
  END d[299]
  PIN d[29]
    DIRECTION INPUT ;
    USE SIGNAL ;
    PORT
      LAYER M4 ;
        RECT  0 23.28 0.084 23.304 ;
    END
  END d[29]
  PIN d[2]
    DIRECTION INPUT ;
    USE SIGNAL ;
    PORT
      LAYER M4 ;
        RECT  0 20.688 0.084 20.712 ;
    END
  END d[2]
  PIN d[300]
    DIRECTION INPUT ;
    USE SIGNAL ;
    PORT
      LAYER M4 ;
        RECT  0 50.064 0.084 50.088 ;
    END
  END d[300]
  PIN d[301]
    DIRECTION INPUT ;
    USE SIGNAL ;
    PORT
      LAYER M4 ;
        RECT  0 50.16 0.084 50.184 ;
    END
  END d[301]
  PIN d[302]
    DIRECTION INPUT ;
    USE SIGNAL ;
    PORT
      LAYER M4 ;
        RECT  0 50.256 0.084 50.28 ;
    END
  END d[302]
  PIN d[303]
    DIRECTION INPUT ;
    USE SIGNAL ;
    PORT
      LAYER M4 ;
        RECT  0 50.352 0.084 50.376 ;
    END
  END d[303]
  PIN d[304]
    DIRECTION INPUT ;
    USE SIGNAL ;
    PORT
      LAYER M4 ;
        RECT  0 50.448 0.084 50.472 ;
    END
  END d[304]
  PIN d[305]
    DIRECTION INPUT ;
    USE SIGNAL ;
    PORT
      LAYER M4 ;
        RECT  0 50.544 0.084 50.568 ;
    END
  END d[305]
  PIN d[306]
    DIRECTION INPUT ;
    USE SIGNAL ;
    PORT
      LAYER M4 ;
        RECT  0 50.64 0.084 50.664 ;
    END
  END d[306]
  PIN d[307]
    DIRECTION INPUT ;
    USE SIGNAL ;
    PORT
      LAYER M4 ;
        RECT  0 50.736 0.084 50.76 ;
    END
  END d[307]
  PIN d[308]
    DIRECTION INPUT ;
    USE SIGNAL ;
    PORT
      LAYER M4 ;
        RECT  0 50.832 0.084 50.856 ;
    END
  END d[308]
  PIN d[309]
    DIRECTION INPUT ;
    USE SIGNAL ;
    PORT
      LAYER M4 ;
        RECT  0 50.928 0.084 50.952 ;
    END
  END d[309]
  PIN d[30]
    DIRECTION INPUT ;
    USE SIGNAL ;
    PORT
      LAYER M4 ;
        RECT  0 23.376 0.084 23.4 ;
    END
  END d[30]
  PIN d[310]
    DIRECTION INPUT ;
    USE SIGNAL ;
    PORT
      LAYER M4 ;
        RECT  0 51.024 0.084 51.048 ;
    END
  END d[310]
  PIN d[311]
    DIRECTION INPUT ;
    USE SIGNAL ;
    PORT
      LAYER M4 ;
        RECT  0 51.12 0.084 51.144 ;
    END
  END d[311]
  PIN d[312]
    DIRECTION INPUT ;
    USE SIGNAL ;
    PORT
      LAYER M4 ;
        RECT  0 51.216 0.084 51.24 ;
    END
  END d[312]
  PIN d[313]
    DIRECTION INPUT ;
    USE SIGNAL ;
    PORT
      LAYER M4 ;
        RECT  0 51.312 0.084 51.336 ;
    END
  END d[313]
  PIN d[314]
    DIRECTION INPUT ;
    USE SIGNAL ;
    PORT
      LAYER M4 ;
        RECT  0 51.408 0.084 51.432 ;
    END
  END d[314]
  PIN d[315]
    DIRECTION INPUT ;
    USE SIGNAL ;
    PORT
      LAYER M4 ;
        RECT  0 51.504 0.084 51.528 ;
    END
  END d[315]
  PIN d[316]
    DIRECTION INPUT ;
    USE SIGNAL ;
    PORT
      LAYER M4 ;
        RECT  0 51.6 0.084 51.624 ;
    END
  END d[316]
  PIN d[317]
    DIRECTION INPUT ;
    USE SIGNAL ;
    PORT
      LAYER M4 ;
        RECT  0 51.696 0.084 51.72 ;
    END
  END d[317]
  PIN d[318]
    DIRECTION INPUT ;
    USE SIGNAL ;
    PORT
      LAYER M4 ;
        RECT  0 51.792 0.084 51.816 ;
    END
  END d[318]
  PIN d[319]
    DIRECTION INPUT ;
    USE SIGNAL ;
    PORT
      LAYER M4 ;
        RECT  0 51.888 0.084 51.912 ;
    END
  END d[319]
  PIN d[31]
    DIRECTION INPUT ;
    USE SIGNAL ;
    PORT
      LAYER M4 ;
        RECT  0 23.472 0.084 23.496 ;
    END
  END d[31]
  PIN d[320]
    DIRECTION INPUT ;
    USE SIGNAL ;
    PORT
      LAYER M4 ;
        RECT  0 51.984 0.084 52.008 ;
    END
  END d[320]
  PIN d[321]
    DIRECTION INPUT ;
    USE SIGNAL ;
    PORT
      LAYER M4 ;
        RECT  0 52.08 0.084 52.104 ;
    END
  END d[321]
  PIN d[322]
    DIRECTION INPUT ;
    USE SIGNAL ;
    PORT
      LAYER M4 ;
        RECT  0 52.176 0.084 52.2 ;
    END
  END d[322]
  PIN d[323]
    DIRECTION INPUT ;
    USE SIGNAL ;
    PORT
      LAYER M4 ;
        RECT  0 52.272 0.084 52.296 ;
    END
  END d[323]
  PIN d[324]
    DIRECTION INPUT ;
    USE SIGNAL ;
    PORT
      LAYER M4 ;
        RECT  0 52.368 0.084 52.392 ;
    END
  END d[324]
  PIN d[325]
    DIRECTION INPUT ;
    USE SIGNAL ;
    PORT
      LAYER M4 ;
        RECT  0 52.464 0.084 52.488 ;
    END
  END d[325]
  PIN d[326]
    DIRECTION INPUT ;
    USE SIGNAL ;
    PORT
      LAYER M4 ;
        RECT  0 52.56 0.084 52.584 ;
    END
  END d[326]
  PIN d[327]
    DIRECTION INPUT ;
    USE SIGNAL ;
    PORT
      LAYER M4 ;
        RECT  0 52.656 0.084 52.68 ;
    END
  END d[327]
  PIN d[328]
    DIRECTION INPUT ;
    USE SIGNAL ;
    PORT
      LAYER M4 ;
        RECT  0 52.752 0.084 52.776 ;
    END
  END d[328]
  PIN d[329]
    DIRECTION INPUT ;
    USE SIGNAL ;
    PORT
      LAYER M4 ;
        RECT  0 52.848 0.084 52.872 ;
    END
  END d[329]
  PIN d[32]
    DIRECTION INPUT ;
    USE SIGNAL ;
    PORT
      LAYER M4 ;
        RECT  0 29.712 0.084 29.736 ;
    END
  END d[32]
  PIN d[330]
    DIRECTION INPUT ;
    USE SIGNAL ;
    PORT
      LAYER M4 ;
        RECT  0 52.944 0.084 52.968 ;
    END
  END d[330]
  PIN d[331]
    DIRECTION INPUT ;
    USE SIGNAL ;
    PORT
      LAYER M4 ;
        RECT  0 53.04 0.084 53.064 ;
    END
  END d[331]
  PIN d[332]
    DIRECTION INPUT ;
    USE SIGNAL ;
    PORT
      LAYER M4 ;
        RECT  0 53.136 0.084 53.16 ;
    END
  END d[332]
  PIN d[333]
    DIRECTION INPUT ;
    USE SIGNAL ;
    PORT
      LAYER M4 ;
        RECT  0 53.232 0.084 53.256 ;
    END
  END d[333]
  PIN d[334]
    DIRECTION INPUT ;
    USE SIGNAL ;
    PORT
      LAYER M4 ;
        RECT  0 53.328 0.084 53.352 ;
    END
  END d[334]
  PIN d[335]
    DIRECTION INPUT ;
    USE SIGNAL ;
    PORT
      LAYER M4 ;
        RECT  0 53.424 0.084 53.448 ;
    END
  END d[335]
  PIN d[336]
    DIRECTION INPUT ;
    USE SIGNAL ;
    PORT
      LAYER M4 ;
        RECT  0 53.52 0.084 53.544 ;
    END
  END d[336]
  PIN d[337]
    DIRECTION INPUT ;
    USE SIGNAL ;
    PORT
      LAYER M4 ;
        RECT  0 53.616 0.084 53.64 ;
    END
  END d[337]
  PIN d[338]
    DIRECTION INPUT ;
    USE SIGNAL ;
    PORT
      LAYER M4 ;
        RECT  0 53.712 0.084 53.736 ;
    END
  END d[338]
  PIN d[339]
    DIRECTION INPUT ;
    USE SIGNAL ;
    PORT
      LAYER M4 ;
        RECT  0 53.808 0.084 53.832 ;
    END
  END d[339]
  PIN d[33]
    DIRECTION INPUT ;
    USE SIGNAL ;
    PORT
      LAYER M4 ;
        RECT  0 29.808 0.084 29.832 ;
    END
  END d[33]
  PIN d[340]
    DIRECTION INPUT ;
    USE SIGNAL ;
    PORT
      LAYER M4 ;
        RECT  0 53.904 0.084 53.928 ;
    END
  END d[340]
  PIN d[341]
    DIRECTION INPUT ;
    USE SIGNAL ;
    PORT
      LAYER M4 ;
        RECT  0 54 0.084 54.024 ;
    END
  END d[341]
  PIN d[342]
    DIRECTION INPUT ;
    USE SIGNAL ;
    PORT
      LAYER M4 ;
        RECT  0 54.096 0.084 54.12 ;
    END
  END d[342]
  PIN d[343]
    DIRECTION INPUT ;
    USE SIGNAL ;
    PORT
      LAYER M4 ;
        RECT  0 54.192 0.084 54.216 ;
    END
  END d[343]
  PIN d[344]
    DIRECTION INPUT ;
    USE SIGNAL ;
    PORT
      LAYER M4 ;
        RECT  0 54.288 0.084 54.312 ;
    END
  END d[344]
  PIN d[345]
    DIRECTION INPUT ;
    USE SIGNAL ;
    PORT
      LAYER M4 ;
        RECT  0 54.384 0.084 54.408 ;
    END
  END d[345]
  PIN d[346]
    DIRECTION INPUT ;
    USE SIGNAL ;
    PORT
      LAYER M4 ;
        RECT  0 54.48 0.084 54.504 ;
    END
  END d[346]
  PIN d[347]
    DIRECTION INPUT ;
    USE SIGNAL ;
    PORT
      LAYER M4 ;
        RECT  0 54.576 0.084 54.6 ;
    END
  END d[347]
  PIN d[348]
    DIRECTION INPUT ;
    USE SIGNAL ;
    PORT
      LAYER M4 ;
        RECT  0 54.672 0.084 54.696 ;
    END
  END d[348]
  PIN d[349]
    DIRECTION INPUT ;
    USE SIGNAL ;
    PORT
      LAYER M4 ;
        RECT  0 54.768 0.084 54.792 ;
    END
  END d[349]
  PIN d[34]
    DIRECTION INPUT ;
    USE SIGNAL ;
    PORT
      LAYER M4 ;
        RECT  0 29.904 0.084 29.928 ;
    END
  END d[34]
  PIN d[350]
    DIRECTION INPUT ;
    USE SIGNAL ;
    PORT
      LAYER M4 ;
        RECT  0 54.864 0.084 54.888 ;
    END
  END d[350]
  PIN d[351]
    DIRECTION INPUT ;
    USE SIGNAL ;
    PORT
      LAYER M4 ;
        RECT  0 54.96 0.084 54.984 ;
    END
  END d[351]
  PIN d[352]
    DIRECTION INPUT ;
    USE SIGNAL ;
    PORT
      LAYER M4 ;
        RECT  0 45.84 0.084 45.864 ;
    END
  END d[352]
  PIN d[353]
    DIRECTION INPUT ;
    USE SIGNAL ;
    PORT
      LAYER M4 ;
        RECT  0 45.936 0.084 45.96 ;
    END
  END d[353]
  PIN d[354]
    DIRECTION INPUT ;
    USE SIGNAL ;
    PORT
      LAYER M4 ;
        RECT  0 46.032 0.084 46.056 ;
    END
  END d[354]
  PIN d[355]
    DIRECTION INPUT ;
    USE SIGNAL ;
    PORT
      LAYER M4 ;
        RECT  0 46.128 0.084 46.152 ;
    END
  END d[355]
  PIN d[356]
    DIRECTION INPUT ;
    USE SIGNAL ;
    PORT
      LAYER M4 ;
        RECT  0 46.224 0.084 46.248 ;
    END
  END d[356]
  PIN d[357]
    DIRECTION INPUT ;
    USE SIGNAL ;
    PORT
      LAYER M4 ;
        RECT  0 46.32 0.084 46.344 ;
    END
  END d[357]
  PIN d[358]
    DIRECTION INPUT ;
    USE SIGNAL ;
    PORT
      LAYER M4 ;
        RECT  0 46.416 0.084 46.44 ;
    END
  END d[358]
  PIN d[359]
    DIRECTION INPUT ;
    USE SIGNAL ;
    PORT
      LAYER M4 ;
        RECT  0 46.512 0.084 46.536 ;
    END
  END d[359]
  PIN d[35]
    DIRECTION INPUT ;
    USE SIGNAL ;
    PORT
      LAYER M4 ;
        RECT  0 30 0.084 30.024 ;
    END
  END d[35]
  PIN d[360]
    DIRECTION INPUT ;
    USE SIGNAL ;
    PORT
      LAYER M4 ;
        RECT  0 46.608 0.084 46.632 ;
    END
  END d[360]
  PIN d[361]
    DIRECTION INPUT ;
    USE SIGNAL ;
    PORT
      LAYER M4 ;
        RECT  0 46.704 0.084 46.728 ;
    END
  END d[361]
  PIN d[362]
    DIRECTION INPUT ;
    USE SIGNAL ;
    PORT
      LAYER M4 ;
        RECT  0 46.8 0.084 46.824 ;
    END
  END d[362]
  PIN d[363]
    DIRECTION INPUT ;
    USE SIGNAL ;
    PORT
      LAYER M4 ;
        RECT  0 46.896 0.084 46.92 ;
    END
  END d[363]
  PIN d[364]
    DIRECTION INPUT ;
    USE SIGNAL ;
    PORT
      LAYER M4 ;
        RECT  0 46.992 0.084 47.016 ;
    END
  END d[364]
  PIN d[365]
    DIRECTION INPUT ;
    USE SIGNAL ;
    PORT
      LAYER M4 ;
        RECT  0 47.088 0.084 47.112 ;
    END
  END d[365]
  PIN d[366]
    DIRECTION INPUT ;
    USE SIGNAL ;
    PORT
      LAYER M4 ;
        RECT  0 47.184 0.084 47.208 ;
    END
  END d[366]
  PIN d[367]
    DIRECTION INPUT ;
    USE SIGNAL ;
    PORT
      LAYER M4 ;
        RECT  0 47.28 0.084 47.304 ;
    END
  END d[367]
  PIN d[368]
    DIRECTION INPUT ;
    USE SIGNAL ;
    PORT
      LAYER M4 ;
        RECT  0 47.376 0.084 47.4 ;
    END
  END d[368]
  PIN d[369]
    DIRECTION INPUT ;
    USE SIGNAL ;
    PORT
      LAYER M4 ;
        RECT  0 47.472 0.084 47.496 ;
    END
  END d[369]
  PIN d[36]
    DIRECTION INPUT ;
    USE SIGNAL ;
    PORT
      LAYER M4 ;
        RECT  0 30.096 0.084 30.12 ;
    END
  END d[36]
  PIN d[370]
    DIRECTION INPUT ;
    USE SIGNAL ;
    PORT
      LAYER M4 ;
        RECT  0 47.568 0.084 47.592 ;
    END
  END d[370]
  PIN d[371]
    DIRECTION INPUT ;
    USE SIGNAL ;
    PORT
      LAYER M4 ;
        RECT  0 47.664 0.084 47.688 ;
    END
  END d[371]
  PIN d[372]
    DIRECTION INPUT ;
    USE SIGNAL ;
    PORT
      LAYER M4 ;
        RECT  0 47.76 0.084 47.784 ;
    END
  END d[372]
  PIN d[373]
    DIRECTION INPUT ;
    USE SIGNAL ;
    PORT
      LAYER M4 ;
        RECT  0 47.856 0.084 47.88 ;
    END
  END d[373]
  PIN d[374]
    DIRECTION INPUT ;
    USE SIGNAL ;
    PORT
      LAYER M4 ;
        RECT  0 47.952 0.084 47.976 ;
    END
  END d[374]
  PIN d[375]
    DIRECTION INPUT ;
    USE SIGNAL ;
    PORT
      LAYER M4 ;
        RECT  0 48.048 0.084 48.072 ;
    END
  END d[375]
  PIN d[376]
    DIRECTION INPUT ;
    USE SIGNAL ;
    PORT
      LAYER M4 ;
        RECT  0 48.144 0.084 48.168 ;
    END
  END d[376]
  PIN d[377]
    DIRECTION INPUT ;
    USE SIGNAL ;
    PORT
      LAYER M4 ;
        RECT  0 48.24 0.084 48.264 ;
    END
  END d[377]
  PIN d[378]
    DIRECTION INPUT ;
    USE SIGNAL ;
    PORT
      LAYER M4 ;
        RECT  0 48.336 0.084 48.36 ;
    END
  END d[378]
  PIN d[379]
    DIRECTION INPUT ;
    USE SIGNAL ;
    PORT
      LAYER M4 ;
        RECT  0 48.432 0.084 48.456 ;
    END
  END d[379]
  PIN d[37]
    DIRECTION INPUT ;
    USE SIGNAL ;
    PORT
      LAYER M4 ;
        RECT  0 30.192 0.084 30.216 ;
    END
  END d[37]
  PIN d[380]
    DIRECTION INPUT ;
    USE SIGNAL ;
    PORT
      LAYER M4 ;
        RECT  0 48.528 0.084 48.552 ;
    END
  END d[380]
  PIN d[381]
    DIRECTION INPUT ;
    USE SIGNAL ;
    PORT
      LAYER M4 ;
        RECT  0 48.624 0.084 48.648 ;
    END
  END d[381]
  PIN d[382]
    DIRECTION INPUT ;
    USE SIGNAL ;
    PORT
      LAYER M4 ;
        RECT  0 48.72 0.084 48.744 ;
    END
  END d[382]
  PIN d[383]
    DIRECTION INPUT ;
    USE SIGNAL ;
    PORT
      LAYER M4 ;
        RECT  0 48.816 0.084 48.84 ;
    END
  END d[383]
  PIN d[384]
    DIRECTION INPUT ;
    USE SIGNAL ;
    PORT
      LAYER M4 ;
        RECT  0 32.784 0.084 32.808 ;
    END
  END d[384]
  PIN d[385]
    DIRECTION INPUT ;
    USE SIGNAL ;
    PORT
      LAYER M4 ;
        RECT  0 32.88 0.084 32.904 ;
    END
  END d[385]
  PIN d[386]
    DIRECTION INPUT ;
    USE SIGNAL ;
    PORT
      LAYER M4 ;
        RECT  0 32.976 0.084 33 ;
    END
  END d[386]
  PIN d[387]
    DIRECTION INPUT ;
    USE SIGNAL ;
    PORT
      LAYER M4 ;
        RECT  0 33.072 0.084 33.096 ;
    END
  END d[387]
  PIN d[388]
    DIRECTION INPUT ;
    USE SIGNAL ;
    PORT
      LAYER M4 ;
        RECT  0 33.168 0.084 33.192 ;
    END
  END d[388]
  PIN d[389]
    DIRECTION INPUT ;
    USE SIGNAL ;
    PORT
      LAYER M4 ;
        RECT  0 33.264 0.084 33.288 ;
    END
  END d[389]
  PIN d[38]
    DIRECTION INPUT ;
    USE SIGNAL ;
    PORT
      LAYER M4 ;
        RECT  0 30.288 0.084 30.312 ;
    END
  END d[38]
  PIN d[390]
    DIRECTION INPUT ;
    USE SIGNAL ;
    PORT
      LAYER M4 ;
        RECT  0 33.36 0.084 33.384 ;
    END
  END d[390]
  PIN d[391]
    DIRECTION INPUT ;
    USE SIGNAL ;
    PORT
      LAYER M4 ;
        RECT  0 33.456 0.084 33.48 ;
    END
  END d[391]
  PIN d[392]
    DIRECTION INPUT ;
    USE SIGNAL ;
    PORT
      LAYER M4 ;
        RECT  0 33.552 0.084 33.576 ;
    END
  END d[392]
  PIN d[393]
    DIRECTION INPUT ;
    USE SIGNAL ;
    PORT
      LAYER M4 ;
        RECT  0 33.648 0.084 33.672 ;
    END
  END d[393]
  PIN d[394]
    DIRECTION INPUT ;
    USE SIGNAL ;
    PORT
      LAYER M4 ;
        RECT  0 33.744 0.084 33.768 ;
    END
  END d[394]
  PIN d[395]
    DIRECTION INPUT ;
    USE SIGNAL ;
    PORT
      LAYER M4 ;
        RECT  0 33.84 0.084 33.864 ;
    END
  END d[395]
  PIN d[396]
    DIRECTION INPUT ;
    USE SIGNAL ;
    PORT
      LAYER M4 ;
        RECT  0 33.936 0.084 33.96 ;
    END
  END d[396]
  PIN d[397]
    DIRECTION INPUT ;
    USE SIGNAL ;
    PORT
      LAYER M4 ;
        RECT  0 34.032 0.084 34.056 ;
    END
  END d[397]
  PIN d[398]
    DIRECTION INPUT ;
    USE SIGNAL ;
    PORT
      LAYER M4 ;
        RECT  0 34.128 0.084 34.152 ;
    END
  END d[398]
  PIN d[399]
    DIRECTION INPUT ;
    USE SIGNAL ;
    PORT
      LAYER M4 ;
        RECT  0 34.224 0.084 34.248 ;
    END
  END d[399]
  PIN d[39]
    DIRECTION INPUT ;
    USE SIGNAL ;
    PORT
      LAYER M4 ;
        RECT  0 30.384 0.084 30.408 ;
    END
  END d[39]
  PIN d[3]
    DIRECTION INPUT ;
    USE SIGNAL ;
    PORT
      LAYER M4 ;
        RECT  0 20.784 0.084 20.808 ;
    END
  END d[3]
  PIN d[400]
    DIRECTION INPUT ;
    USE SIGNAL ;
    PORT
      LAYER M4 ;
        RECT  0 34.32 0.084 34.344 ;
    END
  END d[400]
  PIN d[401]
    DIRECTION INPUT ;
    USE SIGNAL ;
    PORT
      LAYER M4 ;
        RECT  0 34.416 0.084 34.44 ;
    END
  END d[401]
  PIN d[402]
    DIRECTION INPUT ;
    USE SIGNAL ;
    PORT
      LAYER M4 ;
        RECT  0 34.512 0.084 34.536 ;
    END
  END d[402]
  PIN d[403]
    DIRECTION INPUT ;
    USE SIGNAL ;
    PORT
      LAYER M4 ;
        RECT  0 34.608 0.084 34.632 ;
    END
  END d[403]
  PIN d[404]
    DIRECTION INPUT ;
    USE SIGNAL ;
    PORT
      LAYER M4 ;
        RECT  0 34.704 0.084 34.728 ;
    END
  END d[404]
  PIN d[405]
    DIRECTION INPUT ;
    USE SIGNAL ;
    PORT
      LAYER M4 ;
        RECT  0 34.8 0.084 34.824 ;
    END
  END d[405]
  PIN d[406]
    DIRECTION INPUT ;
    USE SIGNAL ;
    PORT
      LAYER M4 ;
        RECT  0 34.896 0.084 34.92 ;
    END
  END d[406]
  PIN d[407]
    DIRECTION INPUT ;
    USE SIGNAL ;
    PORT
      LAYER M4 ;
        RECT  0 34.992 0.084 35.016 ;
    END
  END d[407]
  PIN d[408]
    DIRECTION INPUT ;
    USE SIGNAL ;
    PORT
      LAYER M4 ;
        RECT  0 35.088 0.084 35.112 ;
    END
  END d[408]
  PIN d[409]
    DIRECTION INPUT ;
    USE SIGNAL ;
    PORT
      LAYER M4 ;
        RECT  0 35.184 0.084 35.208 ;
    END
  END d[409]
  PIN d[40]
    DIRECTION INPUT ;
    USE SIGNAL ;
    PORT
      LAYER M4 ;
        RECT  0 30.48 0.084 30.504 ;
    END
  END d[40]
  PIN d[410]
    DIRECTION INPUT ;
    USE SIGNAL ;
    PORT
      LAYER M4 ;
        RECT  0 35.28 0.084 35.304 ;
    END
  END d[410]
  PIN d[411]
    DIRECTION INPUT ;
    USE SIGNAL ;
    PORT
      LAYER M4 ;
        RECT  0 35.376 0.084 35.4 ;
    END
  END d[411]
  PIN d[412]
    DIRECTION INPUT ;
    USE SIGNAL ;
    PORT
      LAYER M4 ;
        RECT  0 35.472 0.084 35.496 ;
    END
  END d[412]
  PIN d[413]
    DIRECTION INPUT ;
    USE SIGNAL ;
    PORT
      LAYER M4 ;
        RECT  0 35.568 0.084 35.592 ;
    END
  END d[413]
  PIN d[414]
    DIRECTION INPUT ;
    USE SIGNAL ;
    PORT
      LAYER M4 ;
        RECT  0 35.664 0.084 35.688 ;
    END
  END d[414]
  PIN d[415]
    DIRECTION INPUT ;
    USE SIGNAL ;
    PORT
      LAYER M4 ;
        RECT  0 35.76 0.084 35.784 ;
    END
  END d[415]
  PIN d[416]
    DIRECTION INPUT ;
    USE SIGNAL ;
    PORT
      LAYER M4 ;
        RECT  0 39.696 0.084 39.72 ;
    END
  END d[416]
  PIN d[417]
    DIRECTION INPUT ;
    USE SIGNAL ;
    PORT
      LAYER M4 ;
        RECT  0 39.792 0.084 39.816 ;
    END
  END d[417]
  PIN d[418]
    DIRECTION INPUT ;
    USE SIGNAL ;
    PORT
      LAYER M4 ;
        RECT  0 39.888 0.084 39.912 ;
    END
  END d[418]
  PIN d[419]
    DIRECTION INPUT ;
    USE SIGNAL ;
    PORT
      LAYER M4 ;
        RECT  0 39.984 0.084 40.008 ;
    END
  END d[419]
  PIN d[41]
    DIRECTION INPUT ;
    USE SIGNAL ;
    PORT
      LAYER M4 ;
        RECT  0 30.576 0.084 30.6 ;
    END
  END d[41]
  PIN d[420]
    DIRECTION INPUT ;
    USE SIGNAL ;
    PORT
      LAYER M4 ;
        RECT  0 40.08 0.084 40.104 ;
    END
  END d[420]
  PIN d[421]
    DIRECTION INPUT ;
    USE SIGNAL ;
    PORT
      LAYER M4 ;
        RECT  0 40.176 0.084 40.2 ;
    END
  END d[421]
  PIN d[422]
    DIRECTION INPUT ;
    USE SIGNAL ;
    PORT
      LAYER M4 ;
        RECT  0 40.272 0.084 40.296 ;
    END
  END d[422]
  PIN d[423]
    DIRECTION INPUT ;
    USE SIGNAL ;
    PORT
      LAYER M4 ;
        RECT  0 40.368 0.084 40.392 ;
    END
  END d[423]
  PIN d[424]
    DIRECTION INPUT ;
    USE SIGNAL ;
    PORT
      LAYER M4 ;
        RECT  0 40.464 0.084 40.488 ;
    END
  END d[424]
  PIN d[425]
    DIRECTION INPUT ;
    USE SIGNAL ;
    PORT
      LAYER M4 ;
        RECT  0 40.56 0.084 40.584 ;
    END
  END d[425]
  PIN d[426]
    DIRECTION INPUT ;
    USE SIGNAL ;
    PORT
      LAYER M4 ;
        RECT  0 40.656 0.084 40.68 ;
    END
  END d[426]
  PIN d[427]
    DIRECTION INPUT ;
    USE SIGNAL ;
    PORT
      LAYER M4 ;
        RECT  0 40.752 0.084 40.776 ;
    END
  END d[427]
  PIN d[428]
    DIRECTION INPUT ;
    USE SIGNAL ;
    PORT
      LAYER M4 ;
        RECT  0 40.848 0.084 40.872 ;
    END
  END d[428]
  PIN d[429]
    DIRECTION INPUT ;
    USE SIGNAL ;
    PORT
      LAYER M4 ;
        RECT  0 40.944 0.084 40.968 ;
    END
  END d[429]
  PIN d[42]
    DIRECTION INPUT ;
    USE SIGNAL ;
    PORT
      LAYER M4 ;
        RECT  0 30.672 0.084 30.696 ;
    END
  END d[42]
  PIN d[430]
    DIRECTION INPUT ;
    USE SIGNAL ;
    PORT
      LAYER M4 ;
        RECT  0 41.04 0.084 41.064 ;
    END
  END d[430]
  PIN d[431]
    DIRECTION INPUT ;
    USE SIGNAL ;
    PORT
      LAYER M4 ;
        RECT  0 41.136 0.084 41.16 ;
    END
  END d[431]
  PIN d[432]
    DIRECTION INPUT ;
    USE SIGNAL ;
    PORT
      LAYER M4 ;
        RECT  0 41.232 0.084 41.256 ;
    END
  END d[432]
  PIN d[433]
    DIRECTION INPUT ;
    USE SIGNAL ;
    PORT
      LAYER M4 ;
        RECT  0 41.328 0.084 41.352 ;
    END
  END d[433]
  PIN d[434]
    DIRECTION INPUT ;
    USE SIGNAL ;
    PORT
      LAYER M4 ;
        RECT  0 41.424 0.084 41.448 ;
    END
  END d[434]
  PIN d[435]
    DIRECTION INPUT ;
    USE SIGNAL ;
    PORT
      LAYER M4 ;
        RECT  0 41.52 0.084 41.544 ;
    END
  END d[435]
  PIN d[436]
    DIRECTION INPUT ;
    USE SIGNAL ;
    PORT
      LAYER M4 ;
        RECT  0 41.616 0.084 41.64 ;
    END
  END d[436]
  PIN d[437]
    DIRECTION INPUT ;
    USE SIGNAL ;
    PORT
      LAYER M4 ;
        RECT  0 41.712 0.084 41.736 ;
    END
  END d[437]
  PIN d[438]
    DIRECTION INPUT ;
    USE SIGNAL ;
    PORT
      LAYER M4 ;
        RECT  0 41.808 0.084 41.832 ;
    END
  END d[438]
  PIN d[439]
    DIRECTION INPUT ;
    USE SIGNAL ;
    PORT
      LAYER M4 ;
        RECT  0 41.904 0.084 41.928 ;
    END
  END d[439]
  PIN d[43]
    DIRECTION INPUT ;
    USE SIGNAL ;
    PORT
      LAYER M4 ;
        RECT  0 30.768 0.084 30.792 ;
    END
  END d[43]
  PIN d[440]
    DIRECTION INPUT ;
    USE SIGNAL ;
    PORT
      LAYER M4 ;
        RECT  0 42 0.084 42.024 ;
    END
  END d[440]
  PIN d[441]
    DIRECTION INPUT ;
    USE SIGNAL ;
    PORT
      LAYER M4 ;
        RECT  0 42.096 0.084 42.12 ;
    END
  END d[441]
  PIN d[442]
    DIRECTION INPUT ;
    USE SIGNAL ;
    PORT
      LAYER M4 ;
        RECT  0 42.192 0.084 42.216 ;
    END
  END d[442]
  PIN d[443]
    DIRECTION INPUT ;
    USE SIGNAL ;
    PORT
      LAYER M4 ;
        RECT  0 42.288 0.084 42.312 ;
    END
  END d[443]
  PIN d[444]
    DIRECTION INPUT ;
    USE SIGNAL ;
    PORT
      LAYER M4 ;
        RECT  0 42.384 0.084 42.408 ;
    END
  END d[444]
  PIN d[445]
    DIRECTION INPUT ;
    USE SIGNAL ;
    PORT
      LAYER M4 ;
        RECT  0 42.48 0.084 42.504 ;
    END
  END d[445]
  PIN d[446]
    DIRECTION INPUT ;
    USE SIGNAL ;
    PORT
      LAYER M4 ;
        RECT  0 42.576 0.084 42.6 ;
    END
  END d[446]
  PIN d[447]
    DIRECTION INPUT ;
    USE SIGNAL ;
    PORT
      LAYER M4 ;
        RECT  0 42.672 0.084 42.696 ;
    END
  END d[447]
  PIN d[448]
    DIRECTION INPUT ;
    USE SIGNAL ;
    PORT
      LAYER M4 ;
        RECT  0 42.768 0.084 42.792 ;
    END
  END d[448]
  PIN d[449]
    DIRECTION INPUT ;
    USE SIGNAL ;
    PORT
      LAYER M4 ;
        RECT  0 42.864 0.084 42.888 ;
    END
  END d[449]
  PIN d[44]
    DIRECTION INPUT ;
    USE SIGNAL ;
    PORT
      LAYER M4 ;
        RECT  0 30.864 0.084 30.888 ;
    END
  END d[44]
  PIN d[450]
    DIRECTION INPUT ;
    USE SIGNAL ;
    PORT
      LAYER M4 ;
        RECT  0 42.96 0.084 42.984 ;
    END
  END d[450]
  PIN d[451]
    DIRECTION INPUT ;
    USE SIGNAL ;
    PORT
      LAYER M4 ;
        RECT  0 43.056 0.084 43.08 ;
    END
  END d[451]
  PIN d[452]
    DIRECTION INPUT ;
    USE SIGNAL ;
    PORT
      LAYER M4 ;
        RECT  0 43.152 0.084 43.176 ;
    END
  END d[452]
  PIN d[453]
    DIRECTION INPUT ;
    USE SIGNAL ;
    PORT
      LAYER M4 ;
        RECT  0 43.248 0.084 43.272 ;
    END
  END d[453]
  PIN d[454]
    DIRECTION INPUT ;
    USE SIGNAL ;
    PORT
      LAYER M4 ;
        RECT  0 43.344 0.084 43.368 ;
    END
  END d[454]
  PIN d[455]
    DIRECTION INPUT ;
    USE SIGNAL ;
    PORT
      LAYER M4 ;
        RECT  0 43.44 0.084 43.464 ;
    END
  END d[455]
  PIN d[456]
    DIRECTION INPUT ;
    USE SIGNAL ;
    PORT
      LAYER M4 ;
        RECT  0 43.536 0.084 43.56 ;
    END
  END d[456]
  PIN d[457]
    DIRECTION INPUT ;
    USE SIGNAL ;
    PORT
      LAYER M4 ;
        RECT  0 43.632 0.084 43.656 ;
    END
  END d[457]
  PIN d[458]
    DIRECTION INPUT ;
    USE SIGNAL ;
    PORT
      LAYER M4 ;
        RECT  0 43.728 0.084 43.752 ;
    END
  END d[458]
  PIN d[459]
    DIRECTION INPUT ;
    USE SIGNAL ;
    PORT
      LAYER M4 ;
        RECT  0 43.824 0.084 43.848 ;
    END
  END d[459]
  PIN d[45]
    DIRECTION INPUT ;
    USE SIGNAL ;
    PORT
      LAYER M4 ;
        RECT  0 30.96 0.084 30.984 ;
    END
  END d[45]
  PIN d[460]
    DIRECTION INPUT ;
    USE SIGNAL ;
    PORT
      LAYER M4 ;
        RECT  0 43.92 0.084 43.944 ;
    END
  END d[460]
  PIN d[461]
    DIRECTION INPUT ;
    USE SIGNAL ;
    PORT
      LAYER M4 ;
        RECT  0 44.016 0.084 44.04 ;
    END
  END d[461]
  PIN d[462]
    DIRECTION INPUT ;
    USE SIGNAL ;
    PORT
      LAYER M4 ;
        RECT  0 44.112 0.084 44.136 ;
    END
  END d[462]
  PIN d[463]
    DIRECTION INPUT ;
    USE SIGNAL ;
    PORT
      LAYER M4 ;
        RECT  0 44.208 0.084 44.232 ;
    END
  END d[463]
  PIN d[464]
    DIRECTION INPUT ;
    USE SIGNAL ;
    PORT
      LAYER M4 ;
        RECT  0 44.304 0.084 44.328 ;
    END
  END d[464]
  PIN d[465]
    DIRECTION INPUT ;
    USE SIGNAL ;
    PORT
      LAYER M4 ;
        RECT  0 44.4 0.084 44.424 ;
    END
  END d[465]
  PIN d[466]
    DIRECTION INPUT ;
    USE SIGNAL ;
    PORT
      LAYER M4 ;
        RECT  0 44.496 0.084 44.52 ;
    END
  END d[466]
  PIN d[467]
    DIRECTION INPUT ;
    USE SIGNAL ;
    PORT
      LAYER M4 ;
        RECT  0 44.592 0.084 44.616 ;
    END
  END d[467]
  PIN d[468]
    DIRECTION INPUT ;
    USE SIGNAL ;
    PORT
      LAYER M4 ;
        RECT  0 44.688 0.084 44.712 ;
    END
  END d[468]
  PIN d[469]
    DIRECTION INPUT ;
    USE SIGNAL ;
    PORT
      LAYER M4 ;
        RECT  0 44.784 0.084 44.808 ;
    END
  END d[469]
  PIN d[46]
    DIRECTION INPUT ;
    USE SIGNAL ;
    PORT
      LAYER M4 ;
        RECT  0 31.056 0.084 31.08 ;
    END
  END d[46]
  PIN d[470]
    DIRECTION INPUT ;
    USE SIGNAL ;
    PORT
      LAYER M4 ;
        RECT  0 44.88 0.084 44.904 ;
    END
  END d[470]
  PIN d[471]
    DIRECTION INPUT ;
    USE SIGNAL ;
    PORT
      LAYER M4 ;
        RECT  0 44.976 0.084 45 ;
    END
  END d[471]
  PIN d[472]
    DIRECTION INPUT ;
    USE SIGNAL ;
    PORT
      LAYER M4 ;
        RECT  0 45.072 0.084 45.096 ;
    END
  END d[472]
  PIN d[473]
    DIRECTION INPUT ;
    USE SIGNAL ;
    PORT
      LAYER M4 ;
        RECT  0 45.168 0.084 45.192 ;
    END
  END d[473]
  PIN d[474]
    DIRECTION INPUT ;
    USE SIGNAL ;
    PORT
      LAYER M4 ;
        RECT  0 45.264 0.084 45.288 ;
    END
  END d[474]
  PIN d[475]
    DIRECTION INPUT ;
    USE SIGNAL ;
    PORT
      LAYER M4 ;
        RECT  0 45.36 0.084 45.384 ;
    END
  END d[475]
  PIN d[476]
    DIRECTION INPUT ;
    USE SIGNAL ;
    PORT
      LAYER M4 ;
        RECT  0 45.456 0.084 45.48 ;
    END
  END d[476]
  PIN d[477]
    DIRECTION INPUT ;
    USE SIGNAL ;
    PORT
      LAYER M4 ;
        RECT  0 45.552 0.084 45.576 ;
    END
  END d[477]
  PIN d[478]
    DIRECTION INPUT ;
    USE SIGNAL ;
    PORT
      LAYER M4 ;
        RECT  0 45.648 0.084 45.672 ;
    END
  END d[478]
  PIN d[479]
    DIRECTION INPUT ;
    USE SIGNAL ;
    PORT
      LAYER M4 ;
        RECT  0 45.744 0.084 45.768 ;
    END
  END d[479]
  PIN d[47]
    DIRECTION INPUT ;
    USE SIGNAL ;
    PORT
      LAYER M4 ;
        RECT  0 31.152 0.084 31.176 ;
    END
  END d[47]
  PIN d[480]
    DIRECTION INPUT ;
    USE SIGNAL ;
    PORT
      LAYER M4 ;
        RECT  0 35.856 0.084 35.88 ;
    END
  END d[480]
  PIN d[481]
    DIRECTION INPUT ;
    USE SIGNAL ;
    PORT
      LAYER M4 ;
        RECT  0 35.952 0.084 35.976 ;
    END
  END d[481]
  PIN d[482]
    DIRECTION INPUT ;
    USE SIGNAL ;
    PORT
      LAYER M4 ;
        RECT  0 36.048 0.084 36.072 ;
    END
  END d[482]
  PIN d[483]
    DIRECTION INPUT ;
    USE SIGNAL ;
    PORT
      LAYER M4 ;
        RECT  0 36.144 0.084 36.168 ;
    END
  END d[483]
  PIN d[484]
    DIRECTION INPUT ;
    USE SIGNAL ;
    PORT
      LAYER M4 ;
        RECT  0 36.24 0.084 36.264 ;
    END
  END d[484]
  PIN d[485]
    DIRECTION INPUT ;
    USE SIGNAL ;
    PORT
      LAYER M4 ;
        RECT  0 36.336 0.084 36.36 ;
    END
  END d[485]
  PIN d[486]
    DIRECTION INPUT ;
    USE SIGNAL ;
    PORT
      LAYER M4 ;
        RECT  0 36.432 0.084 36.456 ;
    END
  END d[486]
  PIN d[487]
    DIRECTION INPUT ;
    USE SIGNAL ;
    PORT
      LAYER M4 ;
        RECT  0 36.528 0.084 36.552 ;
    END
  END d[487]
  PIN d[488]
    DIRECTION INPUT ;
    USE SIGNAL ;
    PORT
      LAYER M4 ;
        RECT  0 36.624 0.084 36.648 ;
    END
  END d[488]
  PIN d[489]
    DIRECTION INPUT ;
    USE SIGNAL ;
    PORT
      LAYER M4 ;
        RECT  0 36.72 0.084 36.744 ;
    END
  END d[489]
  PIN d[48]
    DIRECTION INPUT ;
    USE SIGNAL ;
    PORT
      LAYER M4 ;
        RECT  0 31.248 0.084 31.272 ;
    END
  END d[48]
  PIN d[490]
    DIRECTION INPUT ;
    USE SIGNAL ;
    PORT
      LAYER M4 ;
        RECT  0 36.816 0.084 36.84 ;
    END
  END d[490]
  PIN d[491]
    DIRECTION INPUT ;
    USE SIGNAL ;
    PORT
      LAYER M4 ;
        RECT  0 36.912 0.084 36.936 ;
    END
  END d[491]
  PIN d[492]
    DIRECTION INPUT ;
    USE SIGNAL ;
    PORT
      LAYER M4 ;
        RECT  0 37.008 0.084 37.032 ;
    END
  END d[492]
  PIN d[493]
    DIRECTION INPUT ;
    USE SIGNAL ;
    PORT
      LAYER M4 ;
        RECT  0 37.104 0.084 37.128 ;
    END
  END d[493]
  PIN d[494]
    DIRECTION INPUT ;
    USE SIGNAL ;
    PORT
      LAYER M4 ;
        RECT  0 37.2 0.084 37.224 ;
    END
  END d[494]
  PIN d[495]
    DIRECTION INPUT ;
    USE SIGNAL ;
    PORT
      LAYER M4 ;
        RECT  0 37.296 0.084 37.32 ;
    END
  END d[495]
  PIN d[496]
    DIRECTION INPUT ;
    USE SIGNAL ;
    PORT
      LAYER M4 ;
        RECT  0 37.392 0.084 37.416 ;
    END
  END d[496]
  PIN d[497]
    DIRECTION INPUT ;
    USE SIGNAL ;
    PORT
      LAYER M4 ;
        RECT  0 37.488 0.084 37.512 ;
    END
  END d[497]
  PIN d[498]
    DIRECTION INPUT ;
    USE SIGNAL ;
    PORT
      LAYER M4 ;
        RECT  0 37.584 0.084 37.608 ;
    END
  END d[498]
  PIN d[499]
    DIRECTION INPUT ;
    USE SIGNAL ;
    PORT
      LAYER M4 ;
        RECT  0 37.68 0.084 37.704 ;
    END
  END d[499]
  PIN d[49]
    DIRECTION INPUT ;
    USE SIGNAL ;
    PORT
      LAYER M4 ;
        RECT  0 31.344 0.084 31.368 ;
    END
  END d[49]
  PIN d[4]
    DIRECTION INPUT ;
    USE SIGNAL ;
    PORT
      LAYER M4 ;
        RECT  0 20.88 0.084 20.904 ;
    END
  END d[4]
  PIN d[500]
    DIRECTION INPUT ;
    USE SIGNAL ;
    PORT
      LAYER M4 ;
        RECT  0 37.776 0.084 37.8 ;
    END
  END d[500]
  PIN d[501]
    DIRECTION INPUT ;
    USE SIGNAL ;
    PORT
      LAYER M4 ;
        RECT  0 37.872 0.084 37.896 ;
    END
  END d[501]
  PIN d[502]
    DIRECTION INPUT ;
    USE SIGNAL ;
    PORT
      LAYER M4 ;
        RECT  0 37.968 0.084 37.992 ;
    END
  END d[502]
  PIN d[503]
    DIRECTION INPUT ;
    USE SIGNAL ;
    PORT
      LAYER M4 ;
        RECT  0 38.064 0.084 38.088 ;
    END
  END d[503]
  PIN d[504]
    DIRECTION INPUT ;
    USE SIGNAL ;
    PORT
      LAYER M4 ;
        RECT  0 38.16 0.084 38.184 ;
    END
  END d[504]
  PIN d[505]
    DIRECTION INPUT ;
    USE SIGNAL ;
    PORT
      LAYER M4 ;
        RECT  0 38.256 0.084 38.28 ;
    END
  END d[505]
  PIN d[506]
    DIRECTION INPUT ;
    USE SIGNAL ;
    PORT
      LAYER M4 ;
        RECT  0 38.352 0.084 38.376 ;
    END
  END d[506]
  PIN d[507]
    DIRECTION INPUT ;
    USE SIGNAL ;
    PORT
      LAYER M4 ;
        RECT  0 38.448 0.084 38.472 ;
    END
  END d[507]
  PIN d[508]
    DIRECTION INPUT ;
    USE SIGNAL ;
    PORT
      LAYER M4 ;
        RECT  0 38.544 0.084 38.568 ;
    END
  END d[508]
  PIN d[509]
    DIRECTION INPUT ;
    USE SIGNAL ;
    PORT
      LAYER M4 ;
        RECT  0 38.64 0.084 38.664 ;
    END
  END d[509]
  PIN d[50]
    DIRECTION INPUT ;
    USE SIGNAL ;
    PORT
      LAYER M4 ;
        RECT  0 31.44 0.084 31.464 ;
    END
  END d[50]
  PIN d[510]
    DIRECTION INPUT ;
    USE SIGNAL ;
    PORT
      LAYER M4 ;
        RECT  0 38.736 0.084 38.76 ;
    END
  END d[510]
  PIN d[511]
    DIRECTION INPUT ;
    USE SIGNAL ;
    PORT
      LAYER M4 ;
        RECT  0 38.832 0.084 38.856 ;
    END
  END d[511]
  PIN d[51]
    DIRECTION INPUT ;
    USE SIGNAL ;
    PORT
      LAYER M4 ;
        RECT  0 31.536 0.084 31.56 ;
    END
  END d[51]
  PIN d[52]
    DIRECTION INPUT ;
    USE SIGNAL ;
    PORT
      LAYER M4 ;
        RECT  0 31.632 0.084 31.656 ;
    END
  END d[52]
  PIN d[53]
    DIRECTION INPUT ;
    USE SIGNAL ;
    PORT
      LAYER M4 ;
        RECT  0 31.728 0.084 31.752 ;
    END
  END d[53]
  PIN d[54]
    DIRECTION INPUT ;
    USE SIGNAL ;
    PORT
      LAYER M4 ;
        RECT  0 31.824 0.084 31.848 ;
    END
  END d[54]
  PIN d[55]
    DIRECTION INPUT ;
    USE SIGNAL ;
    PORT
      LAYER M4 ;
        RECT  0 31.92 0.084 31.944 ;
    END
  END d[55]
  PIN d[56]
    DIRECTION INPUT ;
    USE SIGNAL ;
    PORT
      LAYER M4 ;
        RECT  0 32.016 0.084 32.04 ;
    END
  END d[56]
  PIN d[57]
    DIRECTION INPUT ;
    USE SIGNAL ;
    PORT
      LAYER M4 ;
        RECT  0 32.112 0.084 32.136 ;
    END
  END d[57]
  PIN d[58]
    DIRECTION INPUT ;
    USE SIGNAL ;
    PORT
      LAYER M4 ;
        RECT  0 32.208 0.084 32.232 ;
    END
  END d[58]
  PIN d[59]
    DIRECTION INPUT ;
    USE SIGNAL ;
    PORT
      LAYER M4 ;
        RECT  0 32.304 0.084 32.328 ;
    END
  END d[59]
  PIN d[5]
    DIRECTION INPUT ;
    USE SIGNAL ;
    PORT
      LAYER M4 ;
        RECT  0 20.976 0.084 21 ;
    END
  END d[5]
  PIN d[60]
    DIRECTION INPUT ;
    USE SIGNAL ;
    PORT
      LAYER M4 ;
        RECT  0 32.4 0.084 32.424 ;
    END
  END d[60]
  PIN d[61]
    DIRECTION INPUT ;
    USE SIGNAL ;
    PORT
      LAYER M4 ;
        RECT  0 32.496 0.084 32.52 ;
    END
  END d[61]
  PIN d[62]
    DIRECTION INPUT ;
    USE SIGNAL ;
    PORT
      LAYER M4 ;
        RECT  0 32.592 0.084 32.616 ;
    END
  END d[62]
  PIN d[63]
    DIRECTION INPUT ;
    USE SIGNAL ;
    PORT
      LAYER M4 ;
        RECT  0 32.688 0.084 32.712 ;
    END
  END d[63]
  PIN d[64]
    DIRECTION INPUT ;
    USE SIGNAL ;
    PORT
      LAYER M4 ;
        RECT  0 26.64 0.084 26.664 ;
    END
  END d[64]
  PIN d[65]
    DIRECTION INPUT ;
    USE SIGNAL ;
    PORT
      LAYER M4 ;
        RECT  0 26.736 0.084 26.76 ;
    END
  END d[65]
  PIN d[66]
    DIRECTION INPUT ;
    USE SIGNAL ;
    PORT
      LAYER M4 ;
        RECT  0 26.832 0.084 26.856 ;
    END
  END d[66]
  PIN d[67]
    DIRECTION INPUT ;
    USE SIGNAL ;
    PORT
      LAYER M4 ;
        RECT  0 26.928 0.084 26.952 ;
    END
  END d[67]
  PIN d[68]
    DIRECTION INPUT ;
    USE SIGNAL ;
    PORT
      LAYER M4 ;
        RECT  0 27.024 0.084 27.048 ;
    END
  END d[68]
  PIN d[69]
    DIRECTION INPUT ;
    USE SIGNAL ;
    PORT
      LAYER M4 ;
        RECT  0 27.12 0.084 27.144 ;
    END
  END d[69]
  PIN d[6]
    DIRECTION INPUT ;
    USE SIGNAL ;
    PORT
      LAYER M4 ;
        RECT  0 21.072 0.084 21.096 ;
    END
  END d[6]
  PIN d[70]
    DIRECTION INPUT ;
    USE SIGNAL ;
    PORT
      LAYER M4 ;
        RECT  0 27.216 0.084 27.24 ;
    END
  END d[70]
  PIN d[71]
    DIRECTION INPUT ;
    USE SIGNAL ;
    PORT
      LAYER M4 ;
        RECT  0 27.312 0.084 27.336 ;
    END
  END d[71]
  PIN d[72]
    DIRECTION INPUT ;
    USE SIGNAL ;
    PORT
      LAYER M4 ;
        RECT  0 27.408 0.084 27.432 ;
    END
  END d[72]
  PIN d[73]
    DIRECTION INPUT ;
    USE SIGNAL ;
    PORT
      LAYER M4 ;
        RECT  0 27.504 0.084 27.528 ;
    END
  END d[73]
  PIN d[74]
    DIRECTION INPUT ;
    USE SIGNAL ;
    PORT
      LAYER M4 ;
        RECT  0 27.6 0.084 27.624 ;
    END
  END d[74]
  PIN d[75]
    DIRECTION INPUT ;
    USE SIGNAL ;
    PORT
      LAYER M4 ;
        RECT  0 27.696 0.084 27.72 ;
    END
  END d[75]
  PIN d[76]
    DIRECTION INPUT ;
    USE SIGNAL ;
    PORT
      LAYER M4 ;
        RECT  0 27.792 0.084 27.816 ;
    END
  END d[76]
  PIN d[77]
    DIRECTION INPUT ;
    USE SIGNAL ;
    PORT
      LAYER M4 ;
        RECT  0 27.888 0.084 27.912 ;
    END
  END d[77]
  PIN d[78]
    DIRECTION INPUT ;
    USE SIGNAL ;
    PORT
      LAYER M4 ;
        RECT  0 27.984 0.084 28.008 ;
    END
  END d[78]
  PIN d[79]
    DIRECTION INPUT ;
    USE SIGNAL ;
    PORT
      LAYER M4 ;
        RECT  0 28.08 0.084 28.104 ;
    END
  END d[79]
  PIN d[7]
    DIRECTION INPUT ;
    USE SIGNAL ;
    PORT
      LAYER M4 ;
        RECT  0 21.168 0.084 21.192 ;
    END
  END d[7]
  PIN d[80]
    DIRECTION INPUT ;
    USE SIGNAL ;
    PORT
      LAYER M4 ;
        RECT  0 28.176 0.084 28.2 ;
    END
  END d[80]
  PIN d[81]
    DIRECTION INPUT ;
    USE SIGNAL ;
    PORT
      LAYER M4 ;
        RECT  0 28.272 0.084 28.296 ;
    END
  END d[81]
  PIN d[82]
    DIRECTION INPUT ;
    USE SIGNAL ;
    PORT
      LAYER M4 ;
        RECT  0 28.368 0.084 28.392 ;
    END
  END d[82]
  PIN d[83]
    DIRECTION INPUT ;
    USE SIGNAL ;
    PORT
      LAYER M4 ;
        RECT  0 28.464 0.084 28.488 ;
    END
  END d[83]
  PIN d[84]
    DIRECTION INPUT ;
    USE SIGNAL ;
    PORT
      LAYER M4 ;
        RECT  0 28.56 0.084 28.584 ;
    END
  END d[84]
  PIN d[85]
    DIRECTION INPUT ;
    USE SIGNAL ;
    PORT
      LAYER M4 ;
        RECT  0 28.656 0.084 28.68 ;
    END
  END d[85]
  PIN d[86]
    DIRECTION INPUT ;
    USE SIGNAL ;
    PORT
      LAYER M4 ;
        RECT  0 28.752 0.084 28.776 ;
    END
  END d[86]
  PIN d[87]
    DIRECTION INPUT ;
    USE SIGNAL ;
    PORT
      LAYER M4 ;
        RECT  0 28.848 0.084 28.872 ;
    END
  END d[87]
  PIN d[88]
    DIRECTION INPUT ;
    USE SIGNAL ;
    PORT
      LAYER M4 ;
        RECT  0 28.944 0.084 28.968 ;
    END
  END d[88]
  PIN d[89]
    DIRECTION INPUT ;
    USE SIGNAL ;
    PORT
      LAYER M4 ;
        RECT  0 29.04 0.084 29.064 ;
    END
  END d[89]
  PIN d[8]
    DIRECTION INPUT ;
    USE SIGNAL ;
    PORT
      LAYER M4 ;
        RECT  0 21.264 0.084 21.288 ;
    END
  END d[8]
  PIN d[90]
    DIRECTION INPUT ;
    USE SIGNAL ;
    PORT
      LAYER M4 ;
        RECT  0 29.136 0.084 29.16 ;
    END
  END d[90]
  PIN d[91]
    DIRECTION INPUT ;
    USE SIGNAL ;
    PORT
      LAYER M4 ;
        RECT  0 29.232 0.084 29.256 ;
    END
  END d[91]
  PIN d[92]
    DIRECTION INPUT ;
    USE SIGNAL ;
    PORT
      LAYER M4 ;
        RECT  0 29.328 0.084 29.352 ;
    END
  END d[92]
  PIN d[93]
    DIRECTION INPUT ;
    USE SIGNAL ;
    PORT
      LAYER M4 ;
        RECT  0 29.424 0.084 29.448 ;
    END
  END d[93]
  PIN d[94]
    DIRECTION INPUT ;
    USE SIGNAL ;
    PORT
      LAYER M4 ;
        RECT  0 29.52 0.084 29.544 ;
    END
  END d[94]
  PIN d[95]
    DIRECTION INPUT ;
    USE SIGNAL ;
    PORT
      LAYER M4 ;
        RECT  0 29.616 0.084 29.64 ;
    END
  END d[95]
  PIN d[96]
    DIRECTION INPUT ;
    USE SIGNAL ;
    PORT
      LAYER M4 ;
        RECT  0 23.568 0.084 23.592 ;
    END
  END d[96]
  PIN d[97]
    DIRECTION INPUT ;
    USE SIGNAL ;
    PORT
      LAYER M4 ;
        RECT  0 23.664 0.084 23.688 ;
    END
  END d[97]
  PIN d[98]
    DIRECTION INPUT ;
    USE SIGNAL ;
    PORT
      LAYER M4 ;
        RECT  0 23.76 0.084 23.784 ;
    END
  END d[98]
  PIN d[99]
    DIRECTION INPUT ;
    USE SIGNAL ;
    PORT
      LAYER M4 ;
        RECT  0 23.856 0.084 23.88 ;
    END
  END d[99]
  PIN d[9]
    DIRECTION INPUT ;
    USE SIGNAL ;
    PORT
      LAYER M4 ;
        RECT  0 21.36 0.084 21.384 ;
    END
  END d[9]
  PIN me_e
    DIRECTION INPUT ;
    USE SIGNAL ;
    PORT
      LAYER M5 ;
        RECT  4.08 0 4.104 0.084 ;
    END
  END me_e
  PIN q[0]
    DIRECTION OUTPUT ;
    USE SIGNAL ;
    PORT
      LAYER M4 ;
        RECT  17.196 19.92 17.28 19.944 ;
    END
  END q[0]
  PIN q[100]
    DIRECTION OUTPUT ;
    USE SIGNAL ;
    PORT
      LAYER M4 ;
        RECT  17.196 23.376 17.28 23.4 ;
    END
  END q[100]
  PIN q[101]
    DIRECTION OUTPUT ;
    USE SIGNAL ;
    PORT
      LAYER M4 ;
        RECT  17.196 23.472 17.28 23.496 ;
    END
  END q[101]
  PIN q[102]
    DIRECTION OUTPUT ;
    USE SIGNAL ;
    PORT
      LAYER M4 ;
        RECT  17.196 23.568 17.28 23.592 ;
    END
  END q[102]
  PIN q[103]
    DIRECTION OUTPUT ;
    USE SIGNAL ;
    PORT
      LAYER M4 ;
        RECT  17.196 23.664 17.28 23.688 ;
    END
  END q[103]
  PIN q[104]
    DIRECTION OUTPUT ;
    USE SIGNAL ;
    PORT
      LAYER M4 ;
        RECT  17.196 23.76 17.28 23.784 ;
    END
  END q[104]
  PIN q[105]
    DIRECTION OUTPUT ;
    USE SIGNAL ;
    PORT
      LAYER M4 ;
        RECT  17.196 23.856 17.28 23.88 ;
    END
  END q[105]
  PIN q[106]
    DIRECTION OUTPUT ;
    USE SIGNAL ;
    PORT
      LAYER M4 ;
        RECT  17.196 23.952 17.28 23.976 ;
    END
  END q[106]
  PIN q[107]
    DIRECTION OUTPUT ;
    USE SIGNAL ;
    PORT
      LAYER M4 ;
        RECT  17.196 24.048 17.28 24.072 ;
    END
  END q[107]
  PIN q[108]
    DIRECTION OUTPUT ;
    USE SIGNAL ;
    PORT
      LAYER M4 ;
        RECT  17.196 24.144 17.28 24.168 ;
    END
  END q[108]
  PIN q[109]
    DIRECTION OUTPUT ;
    USE SIGNAL ;
    PORT
      LAYER M4 ;
        RECT  17.196 24.24 17.28 24.264 ;
    END
  END q[109]
  PIN q[10]
    DIRECTION OUTPUT ;
    USE SIGNAL ;
    PORT
      LAYER M4 ;
        RECT  17.196 20.88 17.28 20.904 ;
    END
  END q[10]
  PIN q[110]
    DIRECTION OUTPUT ;
    USE SIGNAL ;
    PORT
      LAYER M4 ;
        RECT  17.196 24.336 17.28 24.36 ;
    END
  END q[110]
  PIN q[111]
    DIRECTION OUTPUT ;
    USE SIGNAL ;
    PORT
      LAYER M4 ;
        RECT  17.196 24.432 17.28 24.456 ;
    END
  END q[111]
  PIN q[112]
    DIRECTION OUTPUT ;
    USE SIGNAL ;
    PORT
      LAYER M4 ;
        RECT  17.196 24.528 17.28 24.552 ;
    END
  END q[112]
  PIN q[113]
    DIRECTION OUTPUT ;
    USE SIGNAL ;
    PORT
      LAYER M4 ;
        RECT  17.196 24.624 17.28 24.648 ;
    END
  END q[113]
  PIN q[114]
    DIRECTION OUTPUT ;
    USE SIGNAL ;
    PORT
      LAYER M4 ;
        RECT  17.196 24.72 17.28 24.744 ;
    END
  END q[114]
  PIN q[115]
    DIRECTION OUTPUT ;
    USE SIGNAL ;
    PORT
      LAYER M4 ;
        RECT  17.196 24.816 17.28 24.84 ;
    END
  END q[115]
  PIN q[116]
    DIRECTION OUTPUT ;
    USE SIGNAL ;
    PORT
      LAYER M4 ;
        RECT  17.196 24.912 17.28 24.936 ;
    END
  END q[116]
  PIN q[117]
    DIRECTION OUTPUT ;
    USE SIGNAL ;
    PORT
      LAYER M4 ;
        RECT  17.196 25.008 17.28 25.032 ;
    END
  END q[117]
  PIN q[118]
    DIRECTION OUTPUT ;
    USE SIGNAL ;
    PORT
      LAYER M4 ;
        RECT  17.196 25.104 17.28 25.128 ;
    END
  END q[118]
  PIN q[119]
    DIRECTION OUTPUT ;
    USE SIGNAL ;
    PORT
      LAYER M4 ;
        RECT  17.196 25.2 17.28 25.224 ;
    END
  END q[119]
  PIN q[11]
    DIRECTION OUTPUT ;
    USE SIGNAL ;
    PORT
      LAYER M4 ;
        RECT  17.196 20.976 17.28 21 ;
    END
  END q[11]
  PIN q[120]
    DIRECTION OUTPUT ;
    USE SIGNAL ;
    PORT
      LAYER M4 ;
        RECT  17.196 25.296 17.28 25.32 ;
    END
  END q[120]
  PIN q[121]
    DIRECTION OUTPUT ;
    USE SIGNAL ;
    PORT
      LAYER M4 ;
        RECT  17.196 25.392 17.28 25.416 ;
    END
  END q[121]
  PIN q[122]
    DIRECTION OUTPUT ;
    USE SIGNAL ;
    PORT
      LAYER M4 ;
        RECT  17.196 25.488 17.28 25.512 ;
    END
  END q[122]
  PIN q[123]
    DIRECTION OUTPUT ;
    USE SIGNAL ;
    PORT
      LAYER M4 ;
        RECT  17.196 25.584 17.28 25.608 ;
    END
  END q[123]
  PIN q[124]
    DIRECTION OUTPUT ;
    USE SIGNAL ;
    PORT
      LAYER M4 ;
        RECT  17.196 25.68 17.28 25.704 ;
    END
  END q[124]
  PIN q[125]
    DIRECTION OUTPUT ;
    USE SIGNAL ;
    PORT
      LAYER M4 ;
        RECT  17.196 25.776 17.28 25.8 ;
    END
  END q[125]
  PIN q[126]
    DIRECTION OUTPUT ;
    USE SIGNAL ;
    PORT
      LAYER M4 ;
        RECT  17.196 25.872 17.28 25.896 ;
    END
  END q[126]
  PIN q[127]
    DIRECTION OUTPUT ;
    USE SIGNAL ;
    PORT
      LAYER M4 ;
        RECT  17.196 25.968 17.28 25.992 ;
    END
  END q[127]
  PIN q[128]
    DIRECTION OUTPUT ;
    USE SIGNAL ;
    PORT
      LAYER M4 ;
        RECT  17.196 64.464 17.28 64.488 ;
    END
  END q[128]
  PIN q[129]
    DIRECTION OUTPUT ;
    USE SIGNAL ;
    PORT
      LAYER M4 ;
        RECT  17.196 64.56 17.28 64.584 ;
    END
  END q[129]
  PIN q[12]
    DIRECTION OUTPUT ;
    USE SIGNAL ;
    PORT
      LAYER M4 ;
        RECT  17.196 21.072 17.28 21.096 ;
    END
  END q[12]
  PIN q[130]
    DIRECTION OUTPUT ;
    USE SIGNAL ;
    PORT
      LAYER M4 ;
        RECT  17.196 64.656 17.28 64.68 ;
    END
  END q[130]
  PIN q[131]
    DIRECTION OUTPUT ;
    USE SIGNAL ;
    PORT
      LAYER M4 ;
        RECT  17.196 64.752 17.28 64.776 ;
    END
  END q[131]
  PIN q[132]
    DIRECTION OUTPUT ;
    USE SIGNAL ;
    PORT
      LAYER M4 ;
        RECT  17.196 64.848 17.28 64.872 ;
    END
  END q[132]
  PIN q[133]
    DIRECTION OUTPUT ;
    USE SIGNAL ;
    PORT
      LAYER M4 ;
        RECT  17.196 64.944 17.28 64.968 ;
    END
  END q[133]
  PIN q[134]
    DIRECTION OUTPUT ;
    USE SIGNAL ;
    PORT
      LAYER M4 ;
        RECT  17.196 65.04 17.28 65.064 ;
    END
  END q[134]
  PIN q[135]
    DIRECTION OUTPUT ;
    USE SIGNAL ;
    PORT
      LAYER M4 ;
        RECT  17.196 65.136 17.28 65.16 ;
    END
  END q[135]
  PIN q[136]
    DIRECTION OUTPUT ;
    USE SIGNAL ;
    PORT
      LAYER M4 ;
        RECT  17.196 65.232 17.28 65.256 ;
    END
  END q[136]
  PIN q[137]
    DIRECTION OUTPUT ;
    USE SIGNAL ;
    PORT
      LAYER M4 ;
        RECT  17.196 65.328 17.28 65.352 ;
    END
  END q[137]
  PIN q[138]
    DIRECTION OUTPUT ;
    USE SIGNAL ;
    PORT
      LAYER M4 ;
        RECT  17.196 65.424 17.28 65.448 ;
    END
  END q[138]
  PIN q[139]
    DIRECTION OUTPUT ;
    USE SIGNAL ;
    PORT
      LAYER M4 ;
        RECT  17.196 65.52 17.28 65.544 ;
    END
  END q[139]
  PIN q[13]
    DIRECTION OUTPUT ;
    USE SIGNAL ;
    PORT
      LAYER M4 ;
        RECT  17.196 21.168 17.28 21.192 ;
    END
  END q[13]
  PIN q[140]
    DIRECTION OUTPUT ;
    USE SIGNAL ;
    PORT
      LAYER M4 ;
        RECT  17.196 65.616 17.28 65.64 ;
    END
  END q[140]
  PIN q[141]
    DIRECTION OUTPUT ;
    USE SIGNAL ;
    PORT
      LAYER M4 ;
        RECT  17.196 65.712 17.28 65.736 ;
    END
  END q[141]
  PIN q[142]
    DIRECTION OUTPUT ;
    USE SIGNAL ;
    PORT
      LAYER M4 ;
        RECT  17.196 65.808 17.28 65.832 ;
    END
  END q[142]
  PIN q[143]
    DIRECTION OUTPUT ;
    USE SIGNAL ;
    PORT
      LAYER M4 ;
        RECT  17.196 65.904 17.28 65.928 ;
    END
  END q[143]
  PIN q[144]
    DIRECTION OUTPUT ;
    USE SIGNAL ;
    PORT
      LAYER M4 ;
        RECT  17.196 66 17.28 66.024 ;
    END
  END q[144]
  PIN q[145]
    DIRECTION OUTPUT ;
    USE SIGNAL ;
    PORT
      LAYER M4 ;
        RECT  17.196 66.096 17.28 66.12 ;
    END
  END q[145]
  PIN q[146]
    DIRECTION OUTPUT ;
    USE SIGNAL ;
    PORT
      LAYER M4 ;
        RECT  17.196 66.192 17.28 66.216 ;
    END
  END q[146]
  PIN q[147]
    DIRECTION OUTPUT ;
    USE SIGNAL ;
    PORT
      LAYER M4 ;
        RECT  17.196 66.288 17.28 66.312 ;
    END
  END q[147]
  PIN q[148]
    DIRECTION OUTPUT ;
    USE SIGNAL ;
    PORT
      LAYER M4 ;
        RECT  17.196 66.384 17.28 66.408 ;
    END
  END q[148]
  PIN q[149]
    DIRECTION OUTPUT ;
    USE SIGNAL ;
    PORT
      LAYER M4 ;
        RECT  17.196 66.48 17.28 66.504 ;
    END
  END q[149]
  PIN q[14]
    DIRECTION OUTPUT ;
    USE SIGNAL ;
    PORT
      LAYER M4 ;
        RECT  17.196 21.264 17.28 21.288 ;
    END
  END q[14]
  PIN q[150]
    DIRECTION OUTPUT ;
    USE SIGNAL ;
    PORT
      LAYER M4 ;
        RECT  17.196 66.576 17.28 66.6 ;
    END
  END q[150]
  PIN q[151]
    DIRECTION OUTPUT ;
    USE SIGNAL ;
    PORT
      LAYER M4 ;
        RECT  17.196 66.672 17.28 66.696 ;
    END
  END q[151]
  PIN q[152]
    DIRECTION OUTPUT ;
    USE SIGNAL ;
    PORT
      LAYER M4 ;
        RECT  17.196 66.768 17.28 66.792 ;
    END
  END q[152]
  PIN q[153]
    DIRECTION OUTPUT ;
    USE SIGNAL ;
    PORT
      LAYER M4 ;
        RECT  17.196 66.864 17.28 66.888 ;
    END
  END q[153]
  PIN q[154]
    DIRECTION OUTPUT ;
    USE SIGNAL ;
    PORT
      LAYER M4 ;
        RECT  17.196 66.96 17.28 66.984 ;
    END
  END q[154]
  PIN q[155]
    DIRECTION OUTPUT ;
    USE SIGNAL ;
    PORT
      LAYER M4 ;
        RECT  17.196 67.056 17.28 67.08 ;
    END
  END q[155]
  PIN q[156]
    DIRECTION OUTPUT ;
    USE SIGNAL ;
    PORT
      LAYER M4 ;
        RECT  17.196 67.152 17.28 67.176 ;
    END
  END q[156]
  PIN q[157]
    DIRECTION OUTPUT ;
    USE SIGNAL ;
    PORT
      LAYER M4 ;
        RECT  17.196 67.248 17.28 67.272 ;
    END
  END q[157]
  PIN q[158]
    DIRECTION OUTPUT ;
    USE SIGNAL ;
    PORT
      LAYER M4 ;
        RECT  17.196 67.344 17.28 67.368 ;
    END
  END q[158]
  PIN q[159]
    DIRECTION OUTPUT ;
    USE SIGNAL ;
    PORT
      LAYER M4 ;
        RECT  17.196 67.44 17.28 67.464 ;
    END
  END q[159]
  PIN q[15]
    DIRECTION OUTPUT ;
    USE SIGNAL ;
    PORT
      LAYER M4 ;
        RECT  17.196 21.36 17.28 21.384 ;
    END
  END q[15]
  PIN q[160]
    DIRECTION OUTPUT ;
    USE SIGNAL ;
    PORT
      LAYER M4 ;
        RECT  17.196 73.68 17.28 73.704 ;
    END
  END q[160]
  PIN q[161]
    DIRECTION OUTPUT ;
    USE SIGNAL ;
    PORT
      LAYER M4 ;
        RECT  17.196 73.776 17.28 73.8 ;
    END
  END q[161]
  PIN q[162]
    DIRECTION OUTPUT ;
    USE SIGNAL ;
    PORT
      LAYER M4 ;
        RECT  17.196 73.872 17.28 73.896 ;
    END
  END q[162]
  PIN q[163]
    DIRECTION OUTPUT ;
    USE SIGNAL ;
    PORT
      LAYER M4 ;
        RECT  17.196 73.968 17.28 73.992 ;
    END
  END q[163]
  PIN q[164]
    DIRECTION OUTPUT ;
    USE SIGNAL ;
    PORT
      LAYER M4 ;
        RECT  17.196 74.064 17.28 74.088 ;
    END
  END q[164]
  PIN q[165]
    DIRECTION OUTPUT ;
    USE SIGNAL ;
    PORT
      LAYER M4 ;
        RECT  17.196 74.16 17.28 74.184 ;
    END
  END q[165]
  PIN q[166]
    DIRECTION OUTPUT ;
    USE SIGNAL ;
    PORT
      LAYER M4 ;
        RECT  17.196 74.256 17.28 74.28 ;
    END
  END q[166]
  PIN q[167]
    DIRECTION OUTPUT ;
    USE SIGNAL ;
    PORT
      LAYER M4 ;
        RECT  17.196 74.352 17.28 74.376 ;
    END
  END q[167]
  PIN q[168]
    DIRECTION OUTPUT ;
    USE SIGNAL ;
    PORT
      LAYER M4 ;
        RECT  17.196 74.448 17.28 74.472 ;
    END
  END q[168]
  PIN q[169]
    DIRECTION OUTPUT ;
    USE SIGNAL ;
    PORT
      LAYER M4 ;
        RECT  17.196 74.544 17.28 74.568 ;
    END
  END q[169]
  PIN q[16]
    DIRECTION OUTPUT ;
    USE SIGNAL ;
    PORT
      LAYER M4 ;
        RECT  17.196 21.456 17.28 21.48 ;
    END
  END q[16]
  PIN q[170]
    DIRECTION OUTPUT ;
    USE SIGNAL ;
    PORT
      LAYER M4 ;
        RECT  17.196 74.64 17.28 74.664 ;
    END
  END q[170]
  PIN q[171]
    DIRECTION OUTPUT ;
    USE SIGNAL ;
    PORT
      LAYER M4 ;
        RECT  17.196 74.736 17.28 74.76 ;
    END
  END q[171]
  PIN q[172]
    DIRECTION OUTPUT ;
    USE SIGNAL ;
    PORT
      LAYER M4 ;
        RECT  17.196 74.832 17.28 74.856 ;
    END
  END q[172]
  PIN q[173]
    DIRECTION OUTPUT ;
    USE SIGNAL ;
    PORT
      LAYER M4 ;
        RECT  17.196 74.928 17.28 74.952 ;
    END
  END q[173]
  PIN q[174]
    DIRECTION OUTPUT ;
    USE SIGNAL ;
    PORT
      LAYER M4 ;
        RECT  17.196 75.024 17.28 75.048 ;
    END
  END q[174]
  PIN q[175]
    DIRECTION OUTPUT ;
    USE SIGNAL ;
    PORT
      LAYER M4 ;
        RECT  17.196 75.12 17.28 75.144 ;
    END
  END q[175]
  PIN q[176]
    DIRECTION OUTPUT ;
    USE SIGNAL ;
    PORT
      LAYER M4 ;
        RECT  17.196 75.216 17.28 75.24 ;
    END
  END q[176]
  PIN q[177]
    DIRECTION OUTPUT ;
    USE SIGNAL ;
    PORT
      LAYER M4 ;
        RECT  17.196 75.312 17.28 75.336 ;
    END
  END q[177]
  PIN q[178]
    DIRECTION OUTPUT ;
    USE SIGNAL ;
    PORT
      LAYER M4 ;
        RECT  17.196 75.408 17.28 75.432 ;
    END
  END q[178]
  PIN q[179]
    DIRECTION OUTPUT ;
    USE SIGNAL ;
    PORT
      LAYER M4 ;
        RECT  17.196 75.504 17.28 75.528 ;
    END
  END q[179]
  PIN q[17]
    DIRECTION OUTPUT ;
    USE SIGNAL ;
    PORT
      LAYER M4 ;
        RECT  17.196 21.552 17.28 21.576 ;
    END
  END q[17]
  PIN q[180]
    DIRECTION OUTPUT ;
    USE SIGNAL ;
    PORT
      LAYER M4 ;
        RECT  17.196 75.6 17.28 75.624 ;
    END
  END q[180]
  PIN q[181]
    DIRECTION OUTPUT ;
    USE SIGNAL ;
    PORT
      LAYER M4 ;
        RECT  17.196 75.696 17.28 75.72 ;
    END
  END q[181]
  PIN q[182]
    DIRECTION OUTPUT ;
    USE SIGNAL ;
    PORT
      LAYER M4 ;
        RECT  17.196 75.792 17.28 75.816 ;
    END
  END q[182]
  PIN q[183]
    DIRECTION OUTPUT ;
    USE SIGNAL ;
    PORT
      LAYER M4 ;
        RECT  17.196 75.888 17.28 75.912 ;
    END
  END q[183]
  PIN q[184]
    DIRECTION OUTPUT ;
    USE SIGNAL ;
    PORT
      LAYER M4 ;
        RECT  17.196 75.984 17.28 76.008 ;
    END
  END q[184]
  PIN q[185]
    DIRECTION OUTPUT ;
    USE SIGNAL ;
    PORT
      LAYER M4 ;
        RECT  17.196 76.08 17.28 76.104 ;
    END
  END q[185]
  PIN q[186]
    DIRECTION OUTPUT ;
    USE SIGNAL ;
    PORT
      LAYER M4 ;
        RECT  17.196 76.176 17.28 76.2 ;
    END
  END q[186]
  PIN q[187]
    DIRECTION OUTPUT ;
    USE SIGNAL ;
    PORT
      LAYER M4 ;
        RECT  17.196 76.272 17.28 76.296 ;
    END
  END q[187]
  PIN q[188]
    DIRECTION OUTPUT ;
    USE SIGNAL ;
    PORT
      LAYER M4 ;
        RECT  17.196 76.368 17.28 76.392 ;
    END
  END q[188]
  PIN q[189]
    DIRECTION OUTPUT ;
    USE SIGNAL ;
    PORT
      LAYER M4 ;
        RECT  17.196 76.464 17.28 76.488 ;
    END
  END q[189]
  PIN q[18]
    DIRECTION OUTPUT ;
    USE SIGNAL ;
    PORT
      LAYER M4 ;
        RECT  17.196 21.648 17.28 21.672 ;
    END
  END q[18]
  PIN q[190]
    DIRECTION OUTPUT ;
    USE SIGNAL ;
    PORT
      LAYER M4 ;
        RECT  17.196 76.56 17.28 76.584 ;
    END
  END q[190]
  PIN q[191]
    DIRECTION OUTPUT ;
    USE SIGNAL ;
    PORT
      LAYER M4 ;
        RECT  17.196 76.656 17.28 76.68 ;
    END
  END q[191]
  PIN q[192]
    DIRECTION OUTPUT ;
    USE SIGNAL ;
    PORT
      LAYER M4 ;
        RECT  17.196 67.536 17.28 67.56 ;
    END
  END q[192]
  PIN q[193]
    DIRECTION OUTPUT ;
    USE SIGNAL ;
    PORT
      LAYER M4 ;
        RECT  17.196 67.632 17.28 67.656 ;
    END
  END q[193]
  PIN q[194]
    DIRECTION OUTPUT ;
    USE SIGNAL ;
    PORT
      LAYER M4 ;
        RECT  17.196 67.728 17.28 67.752 ;
    END
  END q[194]
  PIN q[195]
    DIRECTION OUTPUT ;
    USE SIGNAL ;
    PORT
      LAYER M4 ;
        RECT  17.196 67.824 17.28 67.848 ;
    END
  END q[195]
  PIN q[196]
    DIRECTION OUTPUT ;
    USE SIGNAL ;
    PORT
      LAYER M4 ;
        RECT  17.196 67.92 17.28 67.944 ;
    END
  END q[196]
  PIN q[197]
    DIRECTION OUTPUT ;
    USE SIGNAL ;
    PORT
      LAYER M4 ;
        RECT  17.196 68.016 17.28 68.04 ;
    END
  END q[197]
  PIN q[198]
    DIRECTION OUTPUT ;
    USE SIGNAL ;
    PORT
      LAYER M4 ;
        RECT  17.196 68.112 17.28 68.136 ;
    END
  END q[198]
  PIN q[199]
    DIRECTION OUTPUT ;
    USE SIGNAL ;
    PORT
      LAYER M4 ;
        RECT  17.196 68.208 17.28 68.232 ;
    END
  END q[199]
  PIN q[19]
    DIRECTION OUTPUT ;
    USE SIGNAL ;
    PORT
      LAYER M4 ;
        RECT  17.196 21.744 17.28 21.768 ;
    END
  END q[19]
  PIN q[1]
    DIRECTION OUTPUT ;
    USE SIGNAL ;
    PORT
      LAYER M4 ;
        RECT  17.196 20.016 17.28 20.04 ;
    END
  END q[1]
  PIN q[200]
    DIRECTION OUTPUT ;
    USE SIGNAL ;
    PORT
      LAYER M4 ;
        RECT  17.196 68.304 17.28 68.328 ;
    END
  END q[200]
  PIN q[201]
    DIRECTION OUTPUT ;
    USE SIGNAL ;
    PORT
      LAYER M4 ;
        RECT  17.196 68.4 17.28 68.424 ;
    END
  END q[201]
  PIN q[202]
    DIRECTION OUTPUT ;
    USE SIGNAL ;
    PORT
      LAYER M4 ;
        RECT  17.196 68.496 17.28 68.52 ;
    END
  END q[202]
  PIN q[203]
    DIRECTION OUTPUT ;
    USE SIGNAL ;
    PORT
      LAYER M4 ;
        RECT  17.196 68.592 17.28 68.616 ;
    END
  END q[203]
  PIN q[204]
    DIRECTION OUTPUT ;
    USE SIGNAL ;
    PORT
      LAYER M4 ;
        RECT  17.196 68.688 17.28 68.712 ;
    END
  END q[204]
  PIN q[205]
    DIRECTION OUTPUT ;
    USE SIGNAL ;
    PORT
      LAYER M4 ;
        RECT  17.196 68.784 17.28 68.808 ;
    END
  END q[205]
  PIN q[206]
    DIRECTION OUTPUT ;
    USE SIGNAL ;
    PORT
      LAYER M4 ;
        RECT  17.196 68.88 17.28 68.904 ;
    END
  END q[206]
  PIN q[207]
    DIRECTION OUTPUT ;
    USE SIGNAL ;
    PORT
      LAYER M4 ;
        RECT  17.196 68.976 17.28 69 ;
    END
  END q[207]
  PIN q[208]
    DIRECTION OUTPUT ;
    USE SIGNAL ;
    PORT
      LAYER M4 ;
        RECT  17.196 69.072 17.28 69.096 ;
    END
  END q[208]
  PIN q[209]
    DIRECTION OUTPUT ;
    USE SIGNAL ;
    PORT
      LAYER M4 ;
        RECT  17.196 69.168 17.28 69.192 ;
    END
  END q[209]
  PIN q[20]
    DIRECTION OUTPUT ;
    USE SIGNAL ;
    PORT
      LAYER M4 ;
        RECT  17.196 21.84 17.28 21.864 ;
    END
  END q[20]
  PIN q[210]
    DIRECTION OUTPUT ;
    USE SIGNAL ;
    PORT
      LAYER M4 ;
        RECT  17.196 69.264 17.28 69.288 ;
    END
  END q[210]
  PIN q[211]
    DIRECTION OUTPUT ;
    USE SIGNAL ;
    PORT
      LAYER M4 ;
        RECT  17.196 69.36 17.28 69.384 ;
    END
  END q[211]
  PIN q[212]
    DIRECTION OUTPUT ;
    USE SIGNAL ;
    PORT
      LAYER M4 ;
        RECT  17.196 69.456 17.28 69.48 ;
    END
  END q[212]
  PIN q[213]
    DIRECTION OUTPUT ;
    USE SIGNAL ;
    PORT
      LAYER M4 ;
        RECT  17.196 69.552 17.28 69.576 ;
    END
  END q[213]
  PIN q[214]
    DIRECTION OUTPUT ;
    USE SIGNAL ;
    PORT
      LAYER M4 ;
        RECT  17.196 69.648 17.28 69.672 ;
    END
  END q[214]
  PIN q[215]
    DIRECTION OUTPUT ;
    USE SIGNAL ;
    PORT
      LAYER M4 ;
        RECT  17.196 69.744 17.28 69.768 ;
    END
  END q[215]
  PIN q[216]
    DIRECTION OUTPUT ;
    USE SIGNAL ;
    PORT
      LAYER M4 ;
        RECT  17.196 69.84 17.28 69.864 ;
    END
  END q[216]
  PIN q[217]
    DIRECTION OUTPUT ;
    USE SIGNAL ;
    PORT
      LAYER M4 ;
        RECT  17.196 69.936 17.28 69.96 ;
    END
  END q[217]
  PIN q[218]
    DIRECTION OUTPUT ;
    USE SIGNAL ;
    PORT
      LAYER M4 ;
        RECT  17.196 70.032 17.28 70.056 ;
    END
  END q[218]
  PIN q[219]
    DIRECTION OUTPUT ;
    USE SIGNAL ;
    PORT
      LAYER M4 ;
        RECT  17.196 70.128 17.28 70.152 ;
    END
  END q[219]
  PIN q[21]
    DIRECTION OUTPUT ;
    USE SIGNAL ;
    PORT
      LAYER M4 ;
        RECT  17.196 21.936 17.28 21.96 ;
    END
  END q[21]
  PIN q[220]
    DIRECTION OUTPUT ;
    USE SIGNAL ;
    PORT
      LAYER M4 ;
        RECT  17.196 70.224 17.28 70.248 ;
    END
  END q[220]
  PIN q[221]
    DIRECTION OUTPUT ;
    USE SIGNAL ;
    PORT
      LAYER M4 ;
        RECT  17.196 70.32 17.28 70.344 ;
    END
  END q[221]
  PIN q[222]
    DIRECTION OUTPUT ;
    USE SIGNAL ;
    PORT
      LAYER M4 ;
        RECT  17.196 70.416 17.28 70.44 ;
    END
  END q[222]
  PIN q[223]
    DIRECTION OUTPUT ;
    USE SIGNAL ;
    PORT
      LAYER M4 ;
        RECT  17.196 70.512 17.28 70.536 ;
    END
  END q[223]
  PIN q[224]
    DIRECTION OUTPUT ;
    USE SIGNAL ;
    PORT
      LAYER M4 ;
        RECT  17.196 70.608 17.28 70.632 ;
    END
  END q[224]
  PIN q[225]
    DIRECTION OUTPUT ;
    USE SIGNAL ;
    PORT
      LAYER M4 ;
        RECT  17.196 70.704 17.28 70.728 ;
    END
  END q[225]
  PIN q[226]
    DIRECTION OUTPUT ;
    USE SIGNAL ;
    PORT
      LAYER M4 ;
        RECT  17.196 70.8 17.28 70.824 ;
    END
  END q[226]
  PIN q[227]
    DIRECTION OUTPUT ;
    USE SIGNAL ;
    PORT
      LAYER M4 ;
        RECT  17.196 70.896 17.28 70.92 ;
    END
  END q[227]
  PIN q[228]
    DIRECTION OUTPUT ;
    USE SIGNAL ;
    PORT
      LAYER M4 ;
        RECT  17.196 70.992 17.28 71.016 ;
    END
  END q[228]
  PIN q[229]
    DIRECTION OUTPUT ;
    USE SIGNAL ;
    PORT
      LAYER M4 ;
        RECT  17.196 71.088 17.28 71.112 ;
    END
  END q[229]
  PIN q[22]
    DIRECTION OUTPUT ;
    USE SIGNAL ;
    PORT
      LAYER M4 ;
        RECT  17.196 22.032 17.28 22.056 ;
    END
  END q[22]
  PIN q[230]
    DIRECTION OUTPUT ;
    USE SIGNAL ;
    PORT
      LAYER M4 ;
        RECT  17.196 71.184 17.28 71.208 ;
    END
  END q[230]
  PIN q[231]
    DIRECTION OUTPUT ;
    USE SIGNAL ;
    PORT
      LAYER M4 ;
        RECT  17.196 71.28 17.28 71.304 ;
    END
  END q[231]
  PIN q[232]
    DIRECTION OUTPUT ;
    USE SIGNAL ;
    PORT
      LAYER M4 ;
        RECT  17.196 71.376 17.28 71.4 ;
    END
  END q[232]
  PIN q[233]
    DIRECTION OUTPUT ;
    USE SIGNAL ;
    PORT
      LAYER M4 ;
        RECT  17.196 71.472 17.28 71.496 ;
    END
  END q[233]
  PIN q[234]
    DIRECTION OUTPUT ;
    USE SIGNAL ;
    PORT
      LAYER M4 ;
        RECT  17.196 71.568 17.28 71.592 ;
    END
  END q[234]
  PIN q[235]
    DIRECTION OUTPUT ;
    USE SIGNAL ;
    PORT
      LAYER M4 ;
        RECT  17.196 71.664 17.28 71.688 ;
    END
  END q[235]
  PIN q[236]
    DIRECTION OUTPUT ;
    USE SIGNAL ;
    PORT
      LAYER M4 ;
        RECT  17.196 71.76 17.28 71.784 ;
    END
  END q[236]
  PIN q[237]
    DIRECTION OUTPUT ;
    USE SIGNAL ;
    PORT
      LAYER M4 ;
        RECT  17.196 71.856 17.28 71.88 ;
    END
  END q[237]
  PIN q[238]
    DIRECTION OUTPUT ;
    USE SIGNAL ;
    PORT
      LAYER M4 ;
        RECT  17.196 71.952 17.28 71.976 ;
    END
  END q[238]
  PIN q[239]
    DIRECTION OUTPUT ;
    USE SIGNAL ;
    PORT
      LAYER M4 ;
        RECT  17.196 72.048 17.28 72.072 ;
    END
  END q[239]
  PIN q[23]
    DIRECTION OUTPUT ;
    USE SIGNAL ;
    PORT
      LAYER M4 ;
        RECT  17.196 22.128 17.28 22.152 ;
    END
  END q[23]
  PIN q[240]
    DIRECTION OUTPUT ;
    USE SIGNAL ;
    PORT
      LAYER M4 ;
        RECT  17.196 72.144 17.28 72.168 ;
    END
  END q[240]
  PIN q[241]
    DIRECTION OUTPUT ;
    USE SIGNAL ;
    PORT
      LAYER M4 ;
        RECT  17.196 72.24 17.28 72.264 ;
    END
  END q[241]
  PIN q[242]
    DIRECTION OUTPUT ;
    USE SIGNAL ;
    PORT
      LAYER M4 ;
        RECT  17.196 72.336 17.28 72.36 ;
    END
  END q[242]
  PIN q[243]
    DIRECTION OUTPUT ;
    USE SIGNAL ;
    PORT
      LAYER M4 ;
        RECT  17.196 72.432 17.28 72.456 ;
    END
  END q[243]
  PIN q[244]
    DIRECTION OUTPUT ;
    USE SIGNAL ;
    PORT
      LAYER M4 ;
        RECT  17.196 72.528 17.28 72.552 ;
    END
  END q[244]
  PIN q[245]
    DIRECTION OUTPUT ;
    USE SIGNAL ;
    PORT
      LAYER M4 ;
        RECT  17.196 72.624 17.28 72.648 ;
    END
  END q[245]
  PIN q[246]
    DIRECTION OUTPUT ;
    USE SIGNAL ;
    PORT
      LAYER M4 ;
        RECT  17.196 72.72 17.28 72.744 ;
    END
  END q[246]
  PIN q[247]
    DIRECTION OUTPUT ;
    USE SIGNAL ;
    PORT
      LAYER M4 ;
        RECT  17.196 72.816 17.28 72.84 ;
    END
  END q[247]
  PIN q[248]
    DIRECTION OUTPUT ;
    USE SIGNAL ;
    PORT
      LAYER M4 ;
        RECT  17.196 72.912 17.28 72.936 ;
    END
  END q[248]
  PIN q[249]
    DIRECTION OUTPUT ;
    USE SIGNAL ;
    PORT
      LAYER M4 ;
        RECT  17.196 73.008 17.28 73.032 ;
    END
  END q[249]
  PIN q[24]
    DIRECTION OUTPUT ;
    USE SIGNAL ;
    PORT
      LAYER M4 ;
        RECT  17.196 22.224 17.28 22.248 ;
    END
  END q[24]
  PIN q[250]
    DIRECTION OUTPUT ;
    USE SIGNAL ;
    PORT
      LAYER M4 ;
        RECT  17.196 73.104 17.28 73.128 ;
    END
  END q[250]
  PIN q[251]
    DIRECTION OUTPUT ;
    USE SIGNAL ;
    PORT
      LAYER M4 ;
        RECT  17.196 73.2 17.28 73.224 ;
    END
  END q[251]
  PIN q[252]
    DIRECTION OUTPUT ;
    USE SIGNAL ;
    PORT
      LAYER M4 ;
        RECT  17.196 73.296 17.28 73.32 ;
    END
  END q[252]
  PIN q[253]
    DIRECTION OUTPUT ;
    USE SIGNAL ;
    PORT
      LAYER M4 ;
        RECT  17.196 73.392 17.28 73.416 ;
    END
  END q[253]
  PIN q[254]
    DIRECTION OUTPUT ;
    USE SIGNAL ;
    PORT
      LAYER M4 ;
        RECT  17.196 73.488 17.28 73.512 ;
    END
  END q[254]
  PIN q[255]
    DIRECTION OUTPUT ;
    USE SIGNAL ;
    PORT
      LAYER M4 ;
        RECT  17.196 73.584 17.28 73.608 ;
    END
  END q[255]
  PIN q[256]
    DIRECTION OUTPUT ;
    USE SIGNAL ;
    PORT
      LAYER M4 ;
        RECT  17.196 54.48 17.28 54.504 ;
    END
  END q[256]
  PIN q[257]
    DIRECTION OUTPUT ;
    USE SIGNAL ;
    PORT
      LAYER M4 ;
        RECT  17.196 54.576 17.28 54.6 ;
    END
  END q[257]
  PIN q[258]
    DIRECTION OUTPUT ;
    USE SIGNAL ;
    PORT
      LAYER M4 ;
        RECT  17.196 54.672 17.28 54.696 ;
    END
  END q[258]
  PIN q[259]
    DIRECTION OUTPUT ;
    USE SIGNAL ;
    PORT
      LAYER M4 ;
        RECT  17.196 54.768 17.28 54.792 ;
    END
  END q[259]
  PIN q[25]
    DIRECTION OUTPUT ;
    USE SIGNAL ;
    PORT
      LAYER M4 ;
        RECT  17.196 22.32 17.28 22.344 ;
    END
  END q[25]
  PIN q[260]
    DIRECTION OUTPUT ;
    USE SIGNAL ;
    PORT
      LAYER M4 ;
        RECT  17.196 54.864 17.28 54.888 ;
    END
  END q[260]
  PIN q[261]
    DIRECTION OUTPUT ;
    USE SIGNAL ;
    PORT
      LAYER M4 ;
        RECT  17.196 54.96 17.28 54.984 ;
    END
  END q[261]
  PIN q[262]
    DIRECTION OUTPUT ;
    USE SIGNAL ;
    PORT
      LAYER M4 ;
        RECT  17.196 55.056 17.28 55.08 ;
    END
  END q[262]
  PIN q[263]
    DIRECTION OUTPUT ;
    USE SIGNAL ;
    PORT
      LAYER M4 ;
        RECT  17.196 55.152 17.28 55.176 ;
    END
  END q[263]
  PIN q[264]
    DIRECTION OUTPUT ;
    USE SIGNAL ;
    PORT
      LAYER M4 ;
        RECT  17.196 55.248 17.28 55.272 ;
    END
  END q[264]
  PIN q[265]
    DIRECTION OUTPUT ;
    USE SIGNAL ;
    PORT
      LAYER M4 ;
        RECT  17.196 55.344 17.28 55.368 ;
    END
  END q[265]
  PIN q[266]
    DIRECTION OUTPUT ;
    USE SIGNAL ;
    PORT
      LAYER M4 ;
        RECT  17.196 55.44 17.28 55.464 ;
    END
  END q[266]
  PIN q[267]
    DIRECTION OUTPUT ;
    USE SIGNAL ;
    PORT
      LAYER M4 ;
        RECT  17.196 55.536 17.28 55.56 ;
    END
  END q[267]
  PIN q[268]
    DIRECTION OUTPUT ;
    USE SIGNAL ;
    PORT
      LAYER M4 ;
        RECT  17.196 55.632 17.28 55.656 ;
    END
  END q[268]
  PIN q[269]
    DIRECTION OUTPUT ;
    USE SIGNAL ;
    PORT
      LAYER M4 ;
        RECT  17.196 55.728 17.28 55.752 ;
    END
  END q[269]
  PIN q[26]
    DIRECTION OUTPUT ;
    USE SIGNAL ;
    PORT
      LAYER M4 ;
        RECT  17.196 22.416 17.28 22.44 ;
    END
  END q[26]
  PIN q[270]
    DIRECTION OUTPUT ;
    USE SIGNAL ;
    PORT
      LAYER M4 ;
        RECT  17.196 55.824 17.28 55.848 ;
    END
  END q[270]
  PIN q[271]
    DIRECTION OUTPUT ;
    USE SIGNAL ;
    PORT
      LAYER M4 ;
        RECT  17.196 55.92 17.28 55.944 ;
    END
  END q[271]
  PIN q[272]
    DIRECTION OUTPUT ;
    USE SIGNAL ;
    PORT
      LAYER M4 ;
        RECT  17.196 56.016 17.28 56.04 ;
    END
  END q[272]
  PIN q[273]
    DIRECTION OUTPUT ;
    USE SIGNAL ;
    PORT
      LAYER M4 ;
        RECT  17.196 56.112 17.28 56.136 ;
    END
  END q[273]
  PIN q[274]
    DIRECTION OUTPUT ;
    USE SIGNAL ;
    PORT
      LAYER M4 ;
        RECT  17.196 56.208 17.28 56.232 ;
    END
  END q[274]
  PIN q[275]
    DIRECTION OUTPUT ;
    USE SIGNAL ;
    PORT
      LAYER M4 ;
        RECT  17.196 56.304 17.28 56.328 ;
    END
  END q[275]
  PIN q[276]
    DIRECTION OUTPUT ;
    USE SIGNAL ;
    PORT
      LAYER M4 ;
        RECT  17.196 56.4 17.28 56.424 ;
    END
  END q[276]
  PIN q[277]
    DIRECTION OUTPUT ;
    USE SIGNAL ;
    PORT
      LAYER M4 ;
        RECT  17.196 56.496 17.28 56.52 ;
    END
  END q[277]
  PIN q[278]
    DIRECTION OUTPUT ;
    USE SIGNAL ;
    PORT
      LAYER M4 ;
        RECT  17.196 56.592 17.28 56.616 ;
    END
  END q[278]
  PIN q[279]
    DIRECTION OUTPUT ;
    USE SIGNAL ;
    PORT
      LAYER M4 ;
        RECT  17.196 56.688 17.28 56.712 ;
    END
  END q[279]
  PIN q[27]
    DIRECTION OUTPUT ;
    USE SIGNAL ;
    PORT
      LAYER M4 ;
        RECT  17.196 22.512 17.28 22.536 ;
    END
  END q[27]
  PIN q[280]
    DIRECTION OUTPUT ;
    USE SIGNAL ;
    PORT
      LAYER M4 ;
        RECT  17.196 56.784 17.28 56.808 ;
    END
  END q[280]
  PIN q[281]
    DIRECTION OUTPUT ;
    USE SIGNAL ;
    PORT
      LAYER M4 ;
        RECT  17.196 56.88 17.28 56.904 ;
    END
  END q[281]
  PIN q[282]
    DIRECTION OUTPUT ;
    USE SIGNAL ;
    PORT
      LAYER M4 ;
        RECT  17.196 56.976 17.28 57 ;
    END
  END q[282]
  PIN q[283]
    DIRECTION OUTPUT ;
    USE SIGNAL ;
    PORT
      LAYER M4 ;
        RECT  17.196 57.072 17.28 57.096 ;
    END
  END q[283]
  PIN q[284]
    DIRECTION OUTPUT ;
    USE SIGNAL ;
    PORT
      LAYER M4 ;
        RECT  17.196 57.168 17.28 57.192 ;
    END
  END q[284]
  PIN q[285]
    DIRECTION OUTPUT ;
    USE SIGNAL ;
    PORT
      LAYER M4 ;
        RECT  17.196 57.264 17.28 57.288 ;
    END
  END q[285]
  PIN q[286]
    DIRECTION OUTPUT ;
    USE SIGNAL ;
    PORT
      LAYER M4 ;
        RECT  17.196 57.36 17.28 57.384 ;
    END
  END q[286]
  PIN q[287]
    DIRECTION OUTPUT ;
    USE SIGNAL ;
    PORT
      LAYER M4 ;
        RECT  17.196 57.456 17.28 57.48 ;
    END
  END q[287]
  PIN q[288]
    DIRECTION OUTPUT ;
    USE SIGNAL ;
    PORT
      LAYER M4 ;
        RECT  17.196 48.336 17.28 48.36 ;
    END
  END q[288]
  PIN q[289]
    DIRECTION OUTPUT ;
    USE SIGNAL ;
    PORT
      LAYER M4 ;
        RECT  17.196 48.432 17.28 48.456 ;
    END
  END q[289]
  PIN q[28]
    DIRECTION OUTPUT ;
    USE SIGNAL ;
    PORT
      LAYER M4 ;
        RECT  17.196 22.608 17.28 22.632 ;
    END
  END q[28]
  PIN q[290]
    DIRECTION OUTPUT ;
    USE SIGNAL ;
    PORT
      LAYER M4 ;
        RECT  17.196 48.528 17.28 48.552 ;
    END
  END q[290]
  PIN q[291]
    DIRECTION OUTPUT ;
    USE SIGNAL ;
    PORT
      LAYER M4 ;
        RECT  17.196 48.624 17.28 48.648 ;
    END
  END q[291]
  PIN q[292]
    DIRECTION OUTPUT ;
    USE SIGNAL ;
    PORT
      LAYER M4 ;
        RECT  17.196 48.72 17.28 48.744 ;
    END
  END q[292]
  PIN q[293]
    DIRECTION OUTPUT ;
    USE SIGNAL ;
    PORT
      LAYER M4 ;
        RECT  17.196 48.816 17.28 48.84 ;
    END
  END q[293]
  PIN q[294]
    DIRECTION OUTPUT ;
    USE SIGNAL ;
    PORT
      LAYER M4 ;
        RECT  17.196 48.912 17.28 48.936 ;
    END
  END q[294]
  PIN q[295]
    DIRECTION OUTPUT ;
    USE SIGNAL ;
    PORT
      LAYER M4 ;
        RECT  17.196 49.008 17.28 49.032 ;
    END
  END q[295]
  PIN q[296]
    DIRECTION OUTPUT ;
    USE SIGNAL ;
    PORT
      LAYER M4 ;
        RECT  17.196 49.104 17.28 49.128 ;
    END
  END q[296]
  PIN q[297]
    DIRECTION OUTPUT ;
    USE SIGNAL ;
    PORT
      LAYER M4 ;
        RECT  17.196 49.2 17.28 49.224 ;
    END
  END q[297]
  PIN q[298]
    DIRECTION OUTPUT ;
    USE SIGNAL ;
    PORT
      LAYER M4 ;
        RECT  17.196 49.296 17.28 49.32 ;
    END
  END q[298]
  PIN q[299]
    DIRECTION OUTPUT ;
    USE SIGNAL ;
    PORT
      LAYER M4 ;
        RECT  17.196 49.392 17.28 49.416 ;
    END
  END q[299]
  PIN q[29]
    DIRECTION OUTPUT ;
    USE SIGNAL ;
    PORT
      LAYER M4 ;
        RECT  17.196 22.704 17.28 22.728 ;
    END
  END q[29]
  PIN q[2]
    DIRECTION OUTPUT ;
    USE SIGNAL ;
    PORT
      LAYER M4 ;
        RECT  17.196 20.112 17.28 20.136 ;
    END
  END q[2]
  PIN q[300]
    DIRECTION OUTPUT ;
    USE SIGNAL ;
    PORT
      LAYER M4 ;
        RECT  17.196 49.488 17.28 49.512 ;
    END
  END q[300]
  PIN q[301]
    DIRECTION OUTPUT ;
    USE SIGNAL ;
    PORT
      LAYER M4 ;
        RECT  17.196 49.584 17.28 49.608 ;
    END
  END q[301]
  PIN q[302]
    DIRECTION OUTPUT ;
    USE SIGNAL ;
    PORT
      LAYER M4 ;
        RECT  17.196 49.68 17.28 49.704 ;
    END
  END q[302]
  PIN q[303]
    DIRECTION OUTPUT ;
    USE SIGNAL ;
    PORT
      LAYER M4 ;
        RECT  17.196 49.776 17.28 49.8 ;
    END
  END q[303]
  PIN q[304]
    DIRECTION OUTPUT ;
    USE SIGNAL ;
    PORT
      LAYER M4 ;
        RECT  17.196 49.872 17.28 49.896 ;
    END
  END q[304]
  PIN q[305]
    DIRECTION OUTPUT ;
    USE SIGNAL ;
    PORT
      LAYER M4 ;
        RECT  17.196 49.968 17.28 49.992 ;
    END
  END q[305]
  PIN q[306]
    DIRECTION OUTPUT ;
    USE SIGNAL ;
    PORT
      LAYER M4 ;
        RECT  17.196 50.064 17.28 50.088 ;
    END
  END q[306]
  PIN q[307]
    DIRECTION OUTPUT ;
    USE SIGNAL ;
    PORT
      LAYER M4 ;
        RECT  17.196 50.16 17.28 50.184 ;
    END
  END q[307]
  PIN q[308]
    DIRECTION OUTPUT ;
    USE SIGNAL ;
    PORT
      LAYER M4 ;
        RECT  17.196 50.256 17.28 50.28 ;
    END
  END q[308]
  PIN q[309]
    DIRECTION OUTPUT ;
    USE SIGNAL ;
    PORT
      LAYER M4 ;
        RECT  17.196 50.352 17.28 50.376 ;
    END
  END q[309]
  PIN q[30]
    DIRECTION OUTPUT ;
    USE SIGNAL ;
    PORT
      LAYER M4 ;
        RECT  17.196 22.8 17.28 22.824 ;
    END
  END q[30]
  PIN q[310]
    DIRECTION OUTPUT ;
    USE SIGNAL ;
    PORT
      LAYER M4 ;
        RECT  17.196 50.448 17.28 50.472 ;
    END
  END q[310]
  PIN q[311]
    DIRECTION OUTPUT ;
    USE SIGNAL ;
    PORT
      LAYER M4 ;
        RECT  17.196 50.544 17.28 50.568 ;
    END
  END q[311]
  PIN q[312]
    DIRECTION OUTPUT ;
    USE SIGNAL ;
    PORT
      LAYER M4 ;
        RECT  17.196 50.64 17.28 50.664 ;
    END
  END q[312]
  PIN q[313]
    DIRECTION OUTPUT ;
    USE SIGNAL ;
    PORT
      LAYER M4 ;
        RECT  17.196 50.736 17.28 50.76 ;
    END
  END q[313]
  PIN q[314]
    DIRECTION OUTPUT ;
    USE SIGNAL ;
    PORT
      LAYER M4 ;
        RECT  17.196 50.832 17.28 50.856 ;
    END
  END q[314]
  PIN q[315]
    DIRECTION OUTPUT ;
    USE SIGNAL ;
    PORT
      LAYER M4 ;
        RECT  17.196 50.928 17.28 50.952 ;
    END
  END q[315]
  PIN q[316]
    DIRECTION OUTPUT ;
    USE SIGNAL ;
    PORT
      LAYER M4 ;
        RECT  17.196 51.024 17.28 51.048 ;
    END
  END q[316]
  PIN q[317]
    DIRECTION OUTPUT ;
    USE SIGNAL ;
    PORT
      LAYER M4 ;
        RECT  17.196 51.12 17.28 51.144 ;
    END
  END q[317]
  PIN q[318]
    DIRECTION OUTPUT ;
    USE SIGNAL ;
    PORT
      LAYER M4 ;
        RECT  17.196 51.216 17.28 51.24 ;
    END
  END q[318]
  PIN q[319]
    DIRECTION OUTPUT ;
    USE SIGNAL ;
    PORT
      LAYER M4 ;
        RECT  17.196 51.312 17.28 51.336 ;
    END
  END q[319]
  PIN q[31]
    DIRECTION OUTPUT ;
    USE SIGNAL ;
    PORT
      LAYER M4 ;
        RECT  17.196 22.896 17.28 22.92 ;
    END
  END q[31]
  PIN q[320]
    DIRECTION OUTPUT ;
    USE SIGNAL ;
    PORT
      LAYER M4 ;
        RECT  17.196 51.408 17.28 51.432 ;
    END
  END q[320]
  PIN q[321]
    DIRECTION OUTPUT ;
    USE SIGNAL ;
    PORT
      LAYER M4 ;
        RECT  17.196 51.504 17.28 51.528 ;
    END
  END q[321]
  PIN q[322]
    DIRECTION OUTPUT ;
    USE SIGNAL ;
    PORT
      LAYER M4 ;
        RECT  17.196 51.6 17.28 51.624 ;
    END
  END q[322]
  PIN q[323]
    DIRECTION OUTPUT ;
    USE SIGNAL ;
    PORT
      LAYER M4 ;
        RECT  17.196 51.696 17.28 51.72 ;
    END
  END q[323]
  PIN q[324]
    DIRECTION OUTPUT ;
    USE SIGNAL ;
    PORT
      LAYER M4 ;
        RECT  17.196 51.792 17.28 51.816 ;
    END
  END q[324]
  PIN q[325]
    DIRECTION OUTPUT ;
    USE SIGNAL ;
    PORT
      LAYER M4 ;
        RECT  17.196 51.888 17.28 51.912 ;
    END
  END q[325]
  PIN q[326]
    DIRECTION OUTPUT ;
    USE SIGNAL ;
    PORT
      LAYER M4 ;
        RECT  17.196 51.984 17.28 52.008 ;
    END
  END q[326]
  PIN q[327]
    DIRECTION OUTPUT ;
    USE SIGNAL ;
    PORT
      LAYER M4 ;
        RECT  17.196 52.08 17.28 52.104 ;
    END
  END q[327]
  PIN q[328]
    DIRECTION OUTPUT ;
    USE SIGNAL ;
    PORT
      LAYER M4 ;
        RECT  17.196 52.176 17.28 52.2 ;
    END
  END q[328]
  PIN q[329]
    DIRECTION OUTPUT ;
    USE SIGNAL ;
    PORT
      LAYER M4 ;
        RECT  17.196 52.272 17.28 52.296 ;
    END
  END q[329]
  PIN q[32]
    DIRECTION OUTPUT ;
    USE SIGNAL ;
    PORT
      LAYER M4 ;
        RECT  17.196 26.064 17.28 26.088 ;
    END
  END q[32]
  PIN q[330]
    DIRECTION OUTPUT ;
    USE SIGNAL ;
    PORT
      LAYER M4 ;
        RECT  17.196 52.368 17.28 52.392 ;
    END
  END q[330]
  PIN q[331]
    DIRECTION OUTPUT ;
    USE SIGNAL ;
    PORT
      LAYER M4 ;
        RECT  17.196 52.464 17.28 52.488 ;
    END
  END q[331]
  PIN q[332]
    DIRECTION OUTPUT ;
    USE SIGNAL ;
    PORT
      LAYER M4 ;
        RECT  17.196 52.56 17.28 52.584 ;
    END
  END q[332]
  PIN q[333]
    DIRECTION OUTPUT ;
    USE SIGNAL ;
    PORT
      LAYER M4 ;
        RECT  17.196 52.656 17.28 52.68 ;
    END
  END q[333]
  PIN q[334]
    DIRECTION OUTPUT ;
    USE SIGNAL ;
    PORT
      LAYER M4 ;
        RECT  17.196 52.752 17.28 52.776 ;
    END
  END q[334]
  PIN q[335]
    DIRECTION OUTPUT ;
    USE SIGNAL ;
    PORT
      LAYER M4 ;
        RECT  17.196 52.848 17.28 52.872 ;
    END
  END q[335]
  PIN q[336]
    DIRECTION OUTPUT ;
    USE SIGNAL ;
    PORT
      LAYER M4 ;
        RECT  17.196 52.944 17.28 52.968 ;
    END
  END q[336]
  PIN q[337]
    DIRECTION OUTPUT ;
    USE SIGNAL ;
    PORT
      LAYER M4 ;
        RECT  17.196 53.04 17.28 53.064 ;
    END
  END q[337]
  PIN q[338]
    DIRECTION OUTPUT ;
    USE SIGNAL ;
    PORT
      LAYER M4 ;
        RECT  17.196 53.136 17.28 53.16 ;
    END
  END q[338]
  PIN q[339]
    DIRECTION OUTPUT ;
    USE SIGNAL ;
    PORT
      LAYER M4 ;
        RECT  17.196 53.232 17.28 53.256 ;
    END
  END q[339]
  PIN q[33]
    DIRECTION OUTPUT ;
    USE SIGNAL ;
    PORT
      LAYER M4 ;
        RECT  17.196 26.16 17.28 26.184 ;
    END
  END q[33]
  PIN q[340]
    DIRECTION OUTPUT ;
    USE SIGNAL ;
    PORT
      LAYER M4 ;
        RECT  17.196 53.328 17.28 53.352 ;
    END
  END q[340]
  PIN q[341]
    DIRECTION OUTPUT ;
    USE SIGNAL ;
    PORT
      LAYER M4 ;
        RECT  17.196 53.424 17.28 53.448 ;
    END
  END q[341]
  PIN q[342]
    DIRECTION OUTPUT ;
    USE SIGNAL ;
    PORT
      LAYER M4 ;
        RECT  17.196 53.52 17.28 53.544 ;
    END
  END q[342]
  PIN q[343]
    DIRECTION OUTPUT ;
    USE SIGNAL ;
    PORT
      LAYER M4 ;
        RECT  17.196 53.616 17.28 53.64 ;
    END
  END q[343]
  PIN q[344]
    DIRECTION OUTPUT ;
    USE SIGNAL ;
    PORT
      LAYER M4 ;
        RECT  17.196 53.712 17.28 53.736 ;
    END
  END q[344]
  PIN q[345]
    DIRECTION OUTPUT ;
    USE SIGNAL ;
    PORT
      LAYER M4 ;
        RECT  17.196 53.808 17.28 53.832 ;
    END
  END q[345]
  PIN q[346]
    DIRECTION OUTPUT ;
    USE SIGNAL ;
    PORT
      LAYER M4 ;
        RECT  17.196 53.904 17.28 53.928 ;
    END
  END q[346]
  PIN q[347]
    DIRECTION OUTPUT ;
    USE SIGNAL ;
    PORT
      LAYER M4 ;
        RECT  17.196 54 17.28 54.024 ;
    END
  END q[347]
  PIN q[348]
    DIRECTION OUTPUT ;
    USE SIGNAL ;
    PORT
      LAYER M4 ;
        RECT  17.196 54.096 17.28 54.12 ;
    END
  END q[348]
  PIN q[349]
    DIRECTION OUTPUT ;
    USE SIGNAL ;
    PORT
      LAYER M4 ;
        RECT  17.196 54.192 17.28 54.216 ;
    END
  END q[349]
  PIN q[34]
    DIRECTION OUTPUT ;
    USE SIGNAL ;
    PORT
      LAYER M4 ;
        RECT  17.196 26.256 17.28 26.28 ;
    END
  END q[34]
  PIN q[350]
    DIRECTION OUTPUT ;
    USE SIGNAL ;
    PORT
      LAYER M4 ;
        RECT  17.196 54.288 17.28 54.312 ;
    END
  END q[350]
  PIN q[351]
    DIRECTION OUTPUT ;
    USE SIGNAL ;
    PORT
      LAYER M4 ;
        RECT  17.196 54.384 17.28 54.408 ;
    END
  END q[351]
  PIN q[352]
    DIRECTION OUTPUT ;
    USE SIGNAL ;
    PORT
      LAYER M4 ;
        RECT  17.196 45.264 17.28 45.288 ;
    END
  END q[352]
  PIN q[353]
    DIRECTION OUTPUT ;
    USE SIGNAL ;
    PORT
      LAYER M4 ;
        RECT  17.196 45.36 17.28 45.384 ;
    END
  END q[353]
  PIN q[354]
    DIRECTION OUTPUT ;
    USE SIGNAL ;
    PORT
      LAYER M4 ;
        RECT  17.196 45.456 17.28 45.48 ;
    END
  END q[354]
  PIN q[355]
    DIRECTION OUTPUT ;
    USE SIGNAL ;
    PORT
      LAYER M4 ;
        RECT  17.196 45.552 17.28 45.576 ;
    END
  END q[355]
  PIN q[356]
    DIRECTION OUTPUT ;
    USE SIGNAL ;
    PORT
      LAYER M4 ;
        RECT  17.196 45.648 17.28 45.672 ;
    END
  END q[356]
  PIN q[357]
    DIRECTION OUTPUT ;
    USE SIGNAL ;
    PORT
      LAYER M4 ;
        RECT  17.196 45.744 17.28 45.768 ;
    END
  END q[357]
  PIN q[358]
    DIRECTION OUTPUT ;
    USE SIGNAL ;
    PORT
      LAYER M4 ;
        RECT  17.196 45.84 17.28 45.864 ;
    END
  END q[358]
  PIN q[359]
    DIRECTION OUTPUT ;
    USE SIGNAL ;
    PORT
      LAYER M4 ;
        RECT  17.196 45.936 17.28 45.96 ;
    END
  END q[359]
  PIN q[35]
    DIRECTION OUTPUT ;
    USE SIGNAL ;
    PORT
      LAYER M4 ;
        RECT  17.196 26.352 17.28 26.376 ;
    END
  END q[35]
  PIN q[360]
    DIRECTION OUTPUT ;
    USE SIGNAL ;
    PORT
      LAYER M4 ;
        RECT  17.196 46.032 17.28 46.056 ;
    END
  END q[360]
  PIN q[361]
    DIRECTION OUTPUT ;
    USE SIGNAL ;
    PORT
      LAYER M4 ;
        RECT  17.196 46.128 17.28 46.152 ;
    END
  END q[361]
  PIN q[362]
    DIRECTION OUTPUT ;
    USE SIGNAL ;
    PORT
      LAYER M4 ;
        RECT  17.196 46.224 17.28 46.248 ;
    END
  END q[362]
  PIN q[363]
    DIRECTION OUTPUT ;
    USE SIGNAL ;
    PORT
      LAYER M4 ;
        RECT  17.196 46.32 17.28 46.344 ;
    END
  END q[363]
  PIN q[364]
    DIRECTION OUTPUT ;
    USE SIGNAL ;
    PORT
      LAYER M4 ;
        RECT  17.196 46.416 17.28 46.44 ;
    END
  END q[364]
  PIN q[365]
    DIRECTION OUTPUT ;
    USE SIGNAL ;
    PORT
      LAYER M4 ;
        RECT  17.196 46.512 17.28 46.536 ;
    END
  END q[365]
  PIN q[366]
    DIRECTION OUTPUT ;
    USE SIGNAL ;
    PORT
      LAYER M4 ;
        RECT  17.196 46.608 17.28 46.632 ;
    END
  END q[366]
  PIN q[367]
    DIRECTION OUTPUT ;
    USE SIGNAL ;
    PORT
      LAYER M4 ;
        RECT  17.196 46.704 17.28 46.728 ;
    END
  END q[367]
  PIN q[368]
    DIRECTION OUTPUT ;
    USE SIGNAL ;
    PORT
      LAYER M4 ;
        RECT  17.196 46.8 17.28 46.824 ;
    END
  END q[368]
  PIN q[369]
    DIRECTION OUTPUT ;
    USE SIGNAL ;
    PORT
      LAYER M4 ;
        RECT  17.196 46.896 17.28 46.92 ;
    END
  END q[369]
  PIN q[36]
    DIRECTION OUTPUT ;
    USE SIGNAL ;
    PORT
      LAYER M4 ;
        RECT  17.196 26.448 17.28 26.472 ;
    END
  END q[36]
  PIN q[370]
    DIRECTION OUTPUT ;
    USE SIGNAL ;
    PORT
      LAYER M4 ;
        RECT  17.196 46.992 17.28 47.016 ;
    END
  END q[370]
  PIN q[371]
    DIRECTION OUTPUT ;
    USE SIGNAL ;
    PORT
      LAYER M4 ;
        RECT  17.196 47.088 17.28 47.112 ;
    END
  END q[371]
  PIN q[372]
    DIRECTION OUTPUT ;
    USE SIGNAL ;
    PORT
      LAYER M4 ;
        RECT  17.196 47.184 17.28 47.208 ;
    END
  END q[372]
  PIN q[373]
    DIRECTION OUTPUT ;
    USE SIGNAL ;
    PORT
      LAYER M4 ;
        RECT  17.196 47.28 17.28 47.304 ;
    END
  END q[373]
  PIN q[374]
    DIRECTION OUTPUT ;
    USE SIGNAL ;
    PORT
      LAYER M4 ;
        RECT  17.196 47.376 17.28 47.4 ;
    END
  END q[374]
  PIN q[375]
    DIRECTION OUTPUT ;
    USE SIGNAL ;
    PORT
      LAYER M4 ;
        RECT  17.196 47.472 17.28 47.496 ;
    END
  END q[375]
  PIN q[376]
    DIRECTION OUTPUT ;
    USE SIGNAL ;
    PORT
      LAYER M4 ;
        RECT  17.196 47.568 17.28 47.592 ;
    END
  END q[376]
  PIN q[377]
    DIRECTION OUTPUT ;
    USE SIGNAL ;
    PORT
      LAYER M4 ;
        RECT  17.196 47.664 17.28 47.688 ;
    END
  END q[377]
  PIN q[378]
    DIRECTION OUTPUT ;
    USE SIGNAL ;
    PORT
      LAYER M4 ;
        RECT  17.196 47.76 17.28 47.784 ;
    END
  END q[378]
  PIN q[379]
    DIRECTION OUTPUT ;
    USE SIGNAL ;
    PORT
      LAYER M4 ;
        RECT  17.196 47.856 17.28 47.88 ;
    END
  END q[379]
  PIN q[37]
    DIRECTION OUTPUT ;
    USE SIGNAL ;
    PORT
      LAYER M4 ;
        RECT  17.196 26.544 17.28 26.568 ;
    END
  END q[37]
  PIN q[380]
    DIRECTION OUTPUT ;
    USE SIGNAL ;
    PORT
      LAYER M4 ;
        RECT  17.196 47.952 17.28 47.976 ;
    END
  END q[380]
  PIN q[381]
    DIRECTION OUTPUT ;
    USE SIGNAL ;
    PORT
      LAYER M4 ;
        RECT  17.196 48.048 17.28 48.072 ;
    END
  END q[381]
  PIN q[382]
    DIRECTION OUTPUT ;
    USE SIGNAL ;
    PORT
      LAYER M4 ;
        RECT  17.196 48.144 17.28 48.168 ;
    END
  END q[382]
  PIN q[383]
    DIRECTION OUTPUT ;
    USE SIGNAL ;
    PORT
      LAYER M4 ;
        RECT  17.196 48.24 17.28 48.264 ;
    END
  END q[383]
  PIN q[384]
    DIRECTION OUTPUT ;
    USE SIGNAL ;
    PORT
      LAYER M4 ;
        RECT  17.196 35.28 17.28 35.304 ;
    END
  END q[384]
  PIN q[385]
    DIRECTION OUTPUT ;
    USE SIGNAL ;
    PORT
      LAYER M4 ;
        RECT  17.196 35.376 17.28 35.4 ;
    END
  END q[385]
  PIN q[386]
    DIRECTION OUTPUT ;
    USE SIGNAL ;
    PORT
      LAYER M4 ;
        RECT  17.196 35.472 17.28 35.496 ;
    END
  END q[386]
  PIN q[387]
    DIRECTION OUTPUT ;
    USE SIGNAL ;
    PORT
      LAYER M4 ;
        RECT  17.196 35.568 17.28 35.592 ;
    END
  END q[387]
  PIN q[388]
    DIRECTION OUTPUT ;
    USE SIGNAL ;
    PORT
      LAYER M4 ;
        RECT  17.196 35.664 17.28 35.688 ;
    END
  END q[388]
  PIN q[389]
    DIRECTION OUTPUT ;
    USE SIGNAL ;
    PORT
      LAYER M4 ;
        RECT  17.196 35.76 17.28 35.784 ;
    END
  END q[389]
  PIN q[38]
    DIRECTION OUTPUT ;
    USE SIGNAL ;
    PORT
      LAYER M4 ;
        RECT  17.196 26.64 17.28 26.664 ;
    END
  END q[38]
  PIN q[390]
    DIRECTION OUTPUT ;
    USE SIGNAL ;
    PORT
      LAYER M4 ;
        RECT  17.196 35.856 17.28 35.88 ;
    END
  END q[390]
  PIN q[391]
    DIRECTION OUTPUT ;
    USE SIGNAL ;
    PORT
      LAYER M4 ;
        RECT  17.196 35.952 17.28 35.976 ;
    END
  END q[391]
  PIN q[392]
    DIRECTION OUTPUT ;
    USE SIGNAL ;
    PORT
      LAYER M4 ;
        RECT  17.196 36.048 17.28 36.072 ;
    END
  END q[392]
  PIN q[393]
    DIRECTION OUTPUT ;
    USE SIGNAL ;
    PORT
      LAYER M4 ;
        RECT  17.196 36.144 17.28 36.168 ;
    END
  END q[393]
  PIN q[394]
    DIRECTION OUTPUT ;
    USE SIGNAL ;
    PORT
      LAYER M4 ;
        RECT  17.196 36.24 17.28 36.264 ;
    END
  END q[394]
  PIN q[395]
    DIRECTION OUTPUT ;
    USE SIGNAL ;
    PORT
      LAYER M4 ;
        RECT  17.196 36.336 17.28 36.36 ;
    END
  END q[395]
  PIN q[396]
    DIRECTION OUTPUT ;
    USE SIGNAL ;
    PORT
      LAYER M4 ;
        RECT  17.196 36.432 17.28 36.456 ;
    END
  END q[396]
  PIN q[397]
    DIRECTION OUTPUT ;
    USE SIGNAL ;
    PORT
      LAYER M4 ;
        RECT  17.196 36.528 17.28 36.552 ;
    END
  END q[397]
  PIN q[398]
    DIRECTION OUTPUT ;
    USE SIGNAL ;
    PORT
      LAYER M4 ;
        RECT  17.196 36.624 17.28 36.648 ;
    END
  END q[398]
  PIN q[399]
    DIRECTION OUTPUT ;
    USE SIGNAL ;
    PORT
      LAYER M4 ;
        RECT  17.196 36.72 17.28 36.744 ;
    END
  END q[399]
  PIN q[39]
    DIRECTION OUTPUT ;
    USE SIGNAL ;
    PORT
      LAYER M4 ;
        RECT  17.196 26.736 17.28 26.76 ;
    END
  END q[39]
  PIN q[3]
    DIRECTION OUTPUT ;
    USE SIGNAL ;
    PORT
      LAYER M4 ;
        RECT  17.196 20.208 17.28 20.232 ;
    END
  END q[3]
  PIN q[400]
    DIRECTION OUTPUT ;
    USE SIGNAL ;
    PORT
      LAYER M4 ;
        RECT  17.196 36.816 17.28 36.84 ;
    END
  END q[400]
  PIN q[401]
    DIRECTION OUTPUT ;
    USE SIGNAL ;
    PORT
      LAYER M4 ;
        RECT  17.196 36.912 17.28 36.936 ;
    END
  END q[401]
  PIN q[402]
    DIRECTION OUTPUT ;
    USE SIGNAL ;
    PORT
      LAYER M4 ;
        RECT  17.196 37.008 17.28 37.032 ;
    END
  END q[402]
  PIN q[403]
    DIRECTION OUTPUT ;
    USE SIGNAL ;
    PORT
      LAYER M4 ;
        RECT  17.196 37.104 17.28 37.128 ;
    END
  END q[403]
  PIN q[404]
    DIRECTION OUTPUT ;
    USE SIGNAL ;
    PORT
      LAYER M4 ;
        RECT  17.196 37.2 17.28 37.224 ;
    END
  END q[404]
  PIN q[405]
    DIRECTION OUTPUT ;
    USE SIGNAL ;
    PORT
      LAYER M4 ;
        RECT  17.196 37.296 17.28 37.32 ;
    END
  END q[405]
  PIN q[406]
    DIRECTION OUTPUT ;
    USE SIGNAL ;
    PORT
      LAYER M4 ;
        RECT  17.196 37.392 17.28 37.416 ;
    END
  END q[406]
  PIN q[407]
    DIRECTION OUTPUT ;
    USE SIGNAL ;
    PORT
      LAYER M4 ;
        RECT  17.196 37.488 17.28 37.512 ;
    END
  END q[407]
  PIN q[408]
    DIRECTION OUTPUT ;
    USE SIGNAL ;
    PORT
      LAYER M4 ;
        RECT  17.196 37.584 17.28 37.608 ;
    END
  END q[408]
  PIN q[409]
    DIRECTION OUTPUT ;
    USE SIGNAL ;
    PORT
      LAYER M4 ;
        RECT  17.196 37.68 17.28 37.704 ;
    END
  END q[409]
  PIN q[40]
    DIRECTION OUTPUT ;
    USE SIGNAL ;
    PORT
      LAYER M4 ;
        RECT  17.196 26.832 17.28 26.856 ;
    END
  END q[40]
  PIN q[410]
    DIRECTION OUTPUT ;
    USE SIGNAL ;
    PORT
      LAYER M4 ;
        RECT  17.196 37.776 17.28 37.8 ;
    END
  END q[410]
  PIN q[411]
    DIRECTION OUTPUT ;
    USE SIGNAL ;
    PORT
      LAYER M4 ;
        RECT  17.196 37.872 17.28 37.896 ;
    END
  END q[411]
  PIN q[412]
    DIRECTION OUTPUT ;
    USE SIGNAL ;
    PORT
      LAYER M4 ;
        RECT  17.196 37.968 17.28 37.992 ;
    END
  END q[412]
  PIN q[413]
    DIRECTION OUTPUT ;
    USE SIGNAL ;
    PORT
      LAYER M4 ;
        RECT  17.196 38.064 17.28 38.088 ;
    END
  END q[413]
  PIN q[414]
    DIRECTION OUTPUT ;
    USE SIGNAL ;
    PORT
      LAYER M4 ;
        RECT  17.196 38.16 17.28 38.184 ;
    END
  END q[414]
  PIN q[415]
    DIRECTION OUTPUT ;
    USE SIGNAL ;
    PORT
      LAYER M4 ;
        RECT  17.196 38.256 17.28 38.28 ;
    END
  END q[415]
  PIN q[416]
    DIRECTION OUTPUT ;
    USE SIGNAL ;
    PORT
      LAYER M4 ;
        RECT  17.196 39.12 17.28 39.144 ;
    END
  END q[416]
  PIN q[417]
    DIRECTION OUTPUT ;
    USE SIGNAL ;
    PORT
      LAYER M4 ;
        RECT  17.196 39.216 17.28 39.24 ;
    END
  END q[417]
  PIN q[418]
    DIRECTION OUTPUT ;
    USE SIGNAL ;
    PORT
      LAYER M4 ;
        RECT  17.196 39.312 17.28 39.336 ;
    END
  END q[418]
  PIN q[419]
    DIRECTION OUTPUT ;
    USE SIGNAL ;
    PORT
      LAYER M4 ;
        RECT  17.196 39.408 17.28 39.432 ;
    END
  END q[419]
  PIN q[41]
    DIRECTION OUTPUT ;
    USE SIGNAL ;
    PORT
      LAYER M4 ;
        RECT  17.196 26.928 17.28 26.952 ;
    END
  END q[41]
  PIN q[420]
    DIRECTION OUTPUT ;
    USE SIGNAL ;
    PORT
      LAYER M4 ;
        RECT  17.196 39.504 17.28 39.528 ;
    END
  END q[420]
  PIN q[421]
    DIRECTION OUTPUT ;
    USE SIGNAL ;
    PORT
      LAYER M4 ;
        RECT  17.196 39.6 17.28 39.624 ;
    END
  END q[421]
  PIN q[422]
    DIRECTION OUTPUT ;
    USE SIGNAL ;
    PORT
      LAYER M4 ;
        RECT  17.196 39.696 17.28 39.72 ;
    END
  END q[422]
  PIN q[423]
    DIRECTION OUTPUT ;
    USE SIGNAL ;
    PORT
      LAYER M4 ;
        RECT  17.196 39.792 17.28 39.816 ;
    END
  END q[423]
  PIN q[424]
    DIRECTION OUTPUT ;
    USE SIGNAL ;
    PORT
      LAYER M4 ;
        RECT  17.196 39.888 17.28 39.912 ;
    END
  END q[424]
  PIN q[425]
    DIRECTION OUTPUT ;
    USE SIGNAL ;
    PORT
      LAYER M4 ;
        RECT  17.196 39.984 17.28 40.008 ;
    END
  END q[425]
  PIN q[426]
    DIRECTION OUTPUT ;
    USE SIGNAL ;
    PORT
      LAYER M4 ;
        RECT  17.196 40.08 17.28 40.104 ;
    END
  END q[426]
  PIN q[427]
    DIRECTION OUTPUT ;
    USE SIGNAL ;
    PORT
      LAYER M4 ;
        RECT  17.196 40.176 17.28 40.2 ;
    END
  END q[427]
  PIN q[428]
    DIRECTION OUTPUT ;
    USE SIGNAL ;
    PORT
      LAYER M4 ;
        RECT  17.196 40.272 17.28 40.296 ;
    END
  END q[428]
  PIN q[429]
    DIRECTION OUTPUT ;
    USE SIGNAL ;
    PORT
      LAYER M4 ;
        RECT  17.196 40.368 17.28 40.392 ;
    END
  END q[429]
  PIN q[42]
    DIRECTION OUTPUT ;
    USE SIGNAL ;
    PORT
      LAYER M4 ;
        RECT  17.196 27.024 17.28 27.048 ;
    END
  END q[42]
  PIN q[430]
    DIRECTION OUTPUT ;
    USE SIGNAL ;
    PORT
      LAYER M4 ;
        RECT  17.196 40.464 17.28 40.488 ;
    END
  END q[430]
  PIN q[431]
    DIRECTION OUTPUT ;
    USE SIGNAL ;
    PORT
      LAYER M4 ;
        RECT  17.196 40.56 17.28 40.584 ;
    END
  END q[431]
  PIN q[432]
    DIRECTION OUTPUT ;
    USE SIGNAL ;
    PORT
      LAYER M4 ;
        RECT  17.196 40.656 17.28 40.68 ;
    END
  END q[432]
  PIN q[433]
    DIRECTION OUTPUT ;
    USE SIGNAL ;
    PORT
      LAYER M4 ;
        RECT  17.196 40.752 17.28 40.776 ;
    END
  END q[433]
  PIN q[434]
    DIRECTION OUTPUT ;
    USE SIGNAL ;
    PORT
      LAYER M4 ;
        RECT  17.196 40.848 17.28 40.872 ;
    END
  END q[434]
  PIN q[435]
    DIRECTION OUTPUT ;
    USE SIGNAL ;
    PORT
      LAYER M4 ;
        RECT  17.196 40.944 17.28 40.968 ;
    END
  END q[435]
  PIN q[436]
    DIRECTION OUTPUT ;
    USE SIGNAL ;
    PORT
      LAYER M4 ;
        RECT  17.196 41.04 17.28 41.064 ;
    END
  END q[436]
  PIN q[437]
    DIRECTION OUTPUT ;
    USE SIGNAL ;
    PORT
      LAYER M4 ;
        RECT  17.196 41.136 17.28 41.16 ;
    END
  END q[437]
  PIN q[438]
    DIRECTION OUTPUT ;
    USE SIGNAL ;
    PORT
      LAYER M4 ;
        RECT  17.196 41.232 17.28 41.256 ;
    END
  END q[438]
  PIN q[439]
    DIRECTION OUTPUT ;
    USE SIGNAL ;
    PORT
      LAYER M4 ;
        RECT  17.196 41.328 17.28 41.352 ;
    END
  END q[439]
  PIN q[43]
    DIRECTION OUTPUT ;
    USE SIGNAL ;
    PORT
      LAYER M4 ;
        RECT  17.196 27.12 17.28 27.144 ;
    END
  END q[43]
  PIN q[440]
    DIRECTION OUTPUT ;
    USE SIGNAL ;
    PORT
      LAYER M4 ;
        RECT  17.196 41.424 17.28 41.448 ;
    END
  END q[440]
  PIN q[441]
    DIRECTION OUTPUT ;
    USE SIGNAL ;
    PORT
      LAYER M4 ;
        RECT  17.196 41.52 17.28 41.544 ;
    END
  END q[441]
  PIN q[442]
    DIRECTION OUTPUT ;
    USE SIGNAL ;
    PORT
      LAYER M4 ;
        RECT  17.196 41.616 17.28 41.64 ;
    END
  END q[442]
  PIN q[443]
    DIRECTION OUTPUT ;
    USE SIGNAL ;
    PORT
      LAYER M4 ;
        RECT  17.196 41.712 17.28 41.736 ;
    END
  END q[443]
  PIN q[444]
    DIRECTION OUTPUT ;
    USE SIGNAL ;
    PORT
      LAYER M4 ;
        RECT  17.196 41.808 17.28 41.832 ;
    END
  END q[444]
  PIN q[445]
    DIRECTION OUTPUT ;
    USE SIGNAL ;
    PORT
      LAYER M4 ;
        RECT  17.196 41.904 17.28 41.928 ;
    END
  END q[445]
  PIN q[446]
    DIRECTION OUTPUT ;
    USE SIGNAL ;
    PORT
      LAYER M4 ;
        RECT  17.196 42 17.28 42.024 ;
    END
  END q[446]
  PIN q[447]
    DIRECTION OUTPUT ;
    USE SIGNAL ;
    PORT
      LAYER M4 ;
        RECT  17.196 42.096 17.28 42.12 ;
    END
  END q[447]
  PIN q[448]
    DIRECTION OUTPUT ;
    USE SIGNAL ;
    PORT
      LAYER M4 ;
        RECT  17.196 42.192 17.28 42.216 ;
    END
  END q[448]
  PIN q[449]
    DIRECTION OUTPUT ;
    USE SIGNAL ;
    PORT
      LAYER M4 ;
        RECT  17.196 42.288 17.28 42.312 ;
    END
  END q[449]
  PIN q[44]
    DIRECTION OUTPUT ;
    USE SIGNAL ;
    PORT
      LAYER M4 ;
        RECT  17.196 27.216 17.28 27.24 ;
    END
  END q[44]
  PIN q[450]
    DIRECTION OUTPUT ;
    USE SIGNAL ;
    PORT
      LAYER M4 ;
        RECT  17.196 42.384 17.28 42.408 ;
    END
  END q[450]
  PIN q[451]
    DIRECTION OUTPUT ;
    USE SIGNAL ;
    PORT
      LAYER M4 ;
        RECT  17.196 42.48 17.28 42.504 ;
    END
  END q[451]
  PIN q[452]
    DIRECTION OUTPUT ;
    USE SIGNAL ;
    PORT
      LAYER M4 ;
        RECT  17.196 42.576 17.28 42.6 ;
    END
  END q[452]
  PIN q[453]
    DIRECTION OUTPUT ;
    USE SIGNAL ;
    PORT
      LAYER M4 ;
        RECT  17.196 42.672 17.28 42.696 ;
    END
  END q[453]
  PIN q[454]
    DIRECTION OUTPUT ;
    USE SIGNAL ;
    PORT
      LAYER M4 ;
        RECT  17.196 42.768 17.28 42.792 ;
    END
  END q[454]
  PIN q[455]
    DIRECTION OUTPUT ;
    USE SIGNAL ;
    PORT
      LAYER M4 ;
        RECT  17.196 42.864 17.28 42.888 ;
    END
  END q[455]
  PIN q[456]
    DIRECTION OUTPUT ;
    USE SIGNAL ;
    PORT
      LAYER M4 ;
        RECT  17.196 42.96 17.28 42.984 ;
    END
  END q[456]
  PIN q[457]
    DIRECTION OUTPUT ;
    USE SIGNAL ;
    PORT
      LAYER M4 ;
        RECT  17.196 43.056 17.28 43.08 ;
    END
  END q[457]
  PIN q[458]
    DIRECTION OUTPUT ;
    USE SIGNAL ;
    PORT
      LAYER M4 ;
        RECT  17.196 43.152 17.28 43.176 ;
    END
  END q[458]
  PIN q[459]
    DIRECTION OUTPUT ;
    USE SIGNAL ;
    PORT
      LAYER M4 ;
        RECT  17.196 43.248 17.28 43.272 ;
    END
  END q[459]
  PIN q[45]
    DIRECTION OUTPUT ;
    USE SIGNAL ;
    PORT
      LAYER M4 ;
        RECT  17.196 27.312 17.28 27.336 ;
    END
  END q[45]
  PIN q[460]
    DIRECTION OUTPUT ;
    USE SIGNAL ;
    PORT
      LAYER M4 ;
        RECT  17.196 43.344 17.28 43.368 ;
    END
  END q[460]
  PIN q[461]
    DIRECTION OUTPUT ;
    USE SIGNAL ;
    PORT
      LAYER M4 ;
        RECT  17.196 43.44 17.28 43.464 ;
    END
  END q[461]
  PIN q[462]
    DIRECTION OUTPUT ;
    USE SIGNAL ;
    PORT
      LAYER M4 ;
        RECT  17.196 43.536 17.28 43.56 ;
    END
  END q[462]
  PIN q[463]
    DIRECTION OUTPUT ;
    USE SIGNAL ;
    PORT
      LAYER M4 ;
        RECT  17.196 43.632 17.28 43.656 ;
    END
  END q[463]
  PIN q[464]
    DIRECTION OUTPUT ;
    USE SIGNAL ;
    PORT
      LAYER M4 ;
        RECT  17.196 43.728 17.28 43.752 ;
    END
  END q[464]
  PIN q[465]
    DIRECTION OUTPUT ;
    USE SIGNAL ;
    PORT
      LAYER M4 ;
        RECT  17.196 43.824 17.28 43.848 ;
    END
  END q[465]
  PIN q[466]
    DIRECTION OUTPUT ;
    USE SIGNAL ;
    PORT
      LAYER M4 ;
        RECT  17.196 43.92 17.28 43.944 ;
    END
  END q[466]
  PIN q[467]
    DIRECTION OUTPUT ;
    USE SIGNAL ;
    PORT
      LAYER M4 ;
        RECT  17.196 44.016 17.28 44.04 ;
    END
  END q[467]
  PIN q[468]
    DIRECTION OUTPUT ;
    USE SIGNAL ;
    PORT
      LAYER M4 ;
        RECT  17.196 44.112 17.28 44.136 ;
    END
  END q[468]
  PIN q[469]
    DIRECTION OUTPUT ;
    USE SIGNAL ;
    PORT
      LAYER M4 ;
        RECT  17.196 44.208 17.28 44.232 ;
    END
  END q[469]
  PIN q[46]
    DIRECTION OUTPUT ;
    USE SIGNAL ;
    PORT
      LAYER M4 ;
        RECT  17.196 27.408 17.28 27.432 ;
    END
  END q[46]
  PIN q[470]
    DIRECTION OUTPUT ;
    USE SIGNAL ;
    PORT
      LAYER M4 ;
        RECT  17.196 44.304 17.28 44.328 ;
    END
  END q[470]
  PIN q[471]
    DIRECTION OUTPUT ;
    USE SIGNAL ;
    PORT
      LAYER M4 ;
        RECT  17.196 44.4 17.28 44.424 ;
    END
  END q[471]
  PIN q[472]
    DIRECTION OUTPUT ;
    USE SIGNAL ;
    PORT
      LAYER M4 ;
        RECT  17.196 44.496 17.28 44.52 ;
    END
  END q[472]
  PIN q[473]
    DIRECTION OUTPUT ;
    USE SIGNAL ;
    PORT
      LAYER M4 ;
        RECT  17.196 44.592 17.28 44.616 ;
    END
  END q[473]
  PIN q[474]
    DIRECTION OUTPUT ;
    USE SIGNAL ;
    PORT
      LAYER M4 ;
        RECT  17.196 44.688 17.28 44.712 ;
    END
  END q[474]
  PIN q[475]
    DIRECTION OUTPUT ;
    USE SIGNAL ;
    PORT
      LAYER M4 ;
        RECT  17.196 44.784 17.28 44.808 ;
    END
  END q[475]
  PIN q[476]
    DIRECTION OUTPUT ;
    USE SIGNAL ;
    PORT
      LAYER M4 ;
        RECT  17.196 44.88 17.28 44.904 ;
    END
  END q[476]
  PIN q[477]
    DIRECTION OUTPUT ;
    USE SIGNAL ;
    PORT
      LAYER M4 ;
        RECT  17.196 44.976 17.28 45 ;
    END
  END q[477]
  PIN q[478]
    DIRECTION OUTPUT ;
    USE SIGNAL ;
    PORT
      LAYER M4 ;
        RECT  17.196 45.072 17.28 45.096 ;
    END
  END q[478]
  PIN q[479]
    DIRECTION OUTPUT ;
    USE SIGNAL ;
    PORT
      LAYER M4 ;
        RECT  17.196 45.168 17.28 45.192 ;
    END
  END q[479]
  PIN q[47]
    DIRECTION OUTPUT ;
    USE SIGNAL ;
    PORT
      LAYER M4 ;
        RECT  17.196 27.504 17.28 27.528 ;
    END
  END q[47]
  PIN q[480]
    DIRECTION OUTPUT ;
    USE SIGNAL ;
    PORT
      LAYER M4 ;
        RECT  17.196 32.208 17.28 32.232 ;
    END
  END q[480]
  PIN q[481]
    DIRECTION OUTPUT ;
    USE SIGNAL ;
    PORT
      LAYER M4 ;
        RECT  17.196 32.304 17.28 32.328 ;
    END
  END q[481]
  PIN q[482]
    DIRECTION OUTPUT ;
    USE SIGNAL ;
    PORT
      LAYER M4 ;
        RECT  17.196 32.4 17.28 32.424 ;
    END
  END q[482]
  PIN q[483]
    DIRECTION OUTPUT ;
    USE SIGNAL ;
    PORT
      LAYER M4 ;
        RECT  17.196 32.496 17.28 32.52 ;
    END
  END q[483]
  PIN q[484]
    DIRECTION OUTPUT ;
    USE SIGNAL ;
    PORT
      LAYER M4 ;
        RECT  17.196 32.592 17.28 32.616 ;
    END
  END q[484]
  PIN q[485]
    DIRECTION OUTPUT ;
    USE SIGNAL ;
    PORT
      LAYER M4 ;
        RECT  17.196 32.688 17.28 32.712 ;
    END
  END q[485]
  PIN q[486]
    DIRECTION OUTPUT ;
    USE SIGNAL ;
    PORT
      LAYER M4 ;
        RECT  17.196 32.784 17.28 32.808 ;
    END
  END q[486]
  PIN q[487]
    DIRECTION OUTPUT ;
    USE SIGNAL ;
    PORT
      LAYER M4 ;
        RECT  17.196 32.88 17.28 32.904 ;
    END
  END q[487]
  PIN q[488]
    DIRECTION OUTPUT ;
    USE SIGNAL ;
    PORT
      LAYER M4 ;
        RECT  17.196 32.976 17.28 33 ;
    END
  END q[488]
  PIN q[489]
    DIRECTION OUTPUT ;
    USE SIGNAL ;
    PORT
      LAYER M4 ;
        RECT  17.196 33.072 17.28 33.096 ;
    END
  END q[489]
  PIN q[48]
    DIRECTION OUTPUT ;
    USE SIGNAL ;
    PORT
      LAYER M4 ;
        RECT  17.196 27.6 17.28 27.624 ;
    END
  END q[48]
  PIN q[490]
    DIRECTION OUTPUT ;
    USE SIGNAL ;
    PORT
      LAYER M4 ;
        RECT  17.196 33.168 17.28 33.192 ;
    END
  END q[490]
  PIN q[491]
    DIRECTION OUTPUT ;
    USE SIGNAL ;
    PORT
      LAYER M4 ;
        RECT  17.196 33.264 17.28 33.288 ;
    END
  END q[491]
  PIN q[492]
    DIRECTION OUTPUT ;
    USE SIGNAL ;
    PORT
      LAYER M4 ;
        RECT  17.196 33.36 17.28 33.384 ;
    END
  END q[492]
  PIN q[493]
    DIRECTION OUTPUT ;
    USE SIGNAL ;
    PORT
      LAYER M4 ;
        RECT  17.196 33.456 17.28 33.48 ;
    END
  END q[493]
  PIN q[494]
    DIRECTION OUTPUT ;
    USE SIGNAL ;
    PORT
      LAYER M4 ;
        RECT  17.196 33.552 17.28 33.576 ;
    END
  END q[494]
  PIN q[495]
    DIRECTION OUTPUT ;
    USE SIGNAL ;
    PORT
      LAYER M4 ;
        RECT  17.196 33.648 17.28 33.672 ;
    END
  END q[495]
  PIN q[496]
    DIRECTION OUTPUT ;
    USE SIGNAL ;
    PORT
      LAYER M4 ;
        RECT  17.196 33.744 17.28 33.768 ;
    END
  END q[496]
  PIN q[497]
    DIRECTION OUTPUT ;
    USE SIGNAL ;
    PORT
      LAYER M4 ;
        RECT  17.196 33.84 17.28 33.864 ;
    END
  END q[497]
  PIN q[498]
    DIRECTION OUTPUT ;
    USE SIGNAL ;
    PORT
      LAYER M4 ;
        RECT  17.196 33.936 17.28 33.96 ;
    END
  END q[498]
  PIN q[499]
    DIRECTION OUTPUT ;
    USE SIGNAL ;
    PORT
      LAYER M4 ;
        RECT  17.196 34.032 17.28 34.056 ;
    END
  END q[499]
  PIN q[49]
    DIRECTION OUTPUT ;
    USE SIGNAL ;
    PORT
      LAYER M4 ;
        RECT  17.196 27.696 17.28 27.72 ;
    END
  END q[49]
  PIN q[4]
    DIRECTION OUTPUT ;
    USE SIGNAL ;
    PORT
      LAYER M4 ;
        RECT  17.196 20.304 17.28 20.328 ;
    END
  END q[4]
  PIN q[500]
    DIRECTION OUTPUT ;
    USE SIGNAL ;
    PORT
      LAYER M4 ;
        RECT  17.196 34.128 17.28 34.152 ;
    END
  END q[500]
  PIN q[501]
    DIRECTION OUTPUT ;
    USE SIGNAL ;
    PORT
      LAYER M4 ;
        RECT  17.196 34.224 17.28 34.248 ;
    END
  END q[501]
  PIN q[502]
    DIRECTION OUTPUT ;
    USE SIGNAL ;
    PORT
      LAYER M4 ;
        RECT  17.196 34.32 17.28 34.344 ;
    END
  END q[502]
  PIN q[503]
    DIRECTION OUTPUT ;
    USE SIGNAL ;
    PORT
      LAYER M4 ;
        RECT  17.196 34.416 17.28 34.44 ;
    END
  END q[503]
  PIN q[504]
    DIRECTION OUTPUT ;
    USE SIGNAL ;
    PORT
      LAYER M4 ;
        RECT  17.196 34.512 17.28 34.536 ;
    END
  END q[504]
  PIN q[505]
    DIRECTION OUTPUT ;
    USE SIGNAL ;
    PORT
      LAYER M4 ;
        RECT  17.196 34.608 17.28 34.632 ;
    END
  END q[505]
  PIN q[506]
    DIRECTION OUTPUT ;
    USE SIGNAL ;
    PORT
      LAYER M4 ;
        RECT  17.196 34.704 17.28 34.728 ;
    END
  END q[506]
  PIN q[507]
    DIRECTION OUTPUT ;
    USE SIGNAL ;
    PORT
      LAYER M4 ;
        RECT  17.196 34.8 17.28 34.824 ;
    END
  END q[507]
  PIN q[508]
    DIRECTION OUTPUT ;
    USE SIGNAL ;
    PORT
      LAYER M4 ;
        RECT  17.196 34.896 17.28 34.92 ;
    END
  END q[508]
  PIN q[509]
    DIRECTION OUTPUT ;
    USE SIGNAL ;
    PORT
      LAYER M4 ;
        RECT  17.196 34.992 17.28 35.016 ;
    END
  END q[509]
  PIN q[50]
    DIRECTION OUTPUT ;
    USE SIGNAL ;
    PORT
      LAYER M4 ;
        RECT  17.196 27.792 17.28 27.816 ;
    END
  END q[50]
  PIN q[510]
    DIRECTION OUTPUT ;
    USE SIGNAL ;
    PORT
      LAYER M4 ;
        RECT  17.196 35.088 17.28 35.112 ;
    END
  END q[510]
  PIN q[511]
    DIRECTION OUTPUT ;
    USE SIGNAL ;
    PORT
      LAYER M4 ;
        RECT  17.196 35.184 17.28 35.208 ;
    END
  END q[511]
  PIN q[51]
    DIRECTION OUTPUT ;
    USE SIGNAL ;
    PORT
      LAYER M4 ;
        RECT  17.196 27.888 17.28 27.912 ;
    END
  END q[51]
  PIN q[52]
    DIRECTION OUTPUT ;
    USE SIGNAL ;
    PORT
      LAYER M4 ;
        RECT  17.196 27.984 17.28 28.008 ;
    END
  END q[52]
  PIN q[53]
    DIRECTION OUTPUT ;
    USE SIGNAL ;
    PORT
      LAYER M4 ;
        RECT  17.196 28.08 17.28 28.104 ;
    END
  END q[53]
  PIN q[54]
    DIRECTION OUTPUT ;
    USE SIGNAL ;
    PORT
      LAYER M4 ;
        RECT  17.196 28.176 17.28 28.2 ;
    END
  END q[54]
  PIN q[55]
    DIRECTION OUTPUT ;
    USE SIGNAL ;
    PORT
      LAYER M4 ;
        RECT  17.196 28.272 17.28 28.296 ;
    END
  END q[55]
  PIN q[56]
    DIRECTION OUTPUT ;
    USE SIGNAL ;
    PORT
      LAYER M4 ;
        RECT  17.196 28.368 17.28 28.392 ;
    END
  END q[56]
  PIN q[57]
    DIRECTION OUTPUT ;
    USE SIGNAL ;
    PORT
      LAYER M4 ;
        RECT  17.196 28.464 17.28 28.488 ;
    END
  END q[57]
  PIN q[58]
    DIRECTION OUTPUT ;
    USE SIGNAL ;
    PORT
      LAYER M4 ;
        RECT  17.196 28.56 17.28 28.584 ;
    END
  END q[58]
  PIN q[59]
    DIRECTION OUTPUT ;
    USE SIGNAL ;
    PORT
      LAYER M4 ;
        RECT  17.196 28.656 17.28 28.68 ;
    END
  END q[59]
  PIN q[5]
    DIRECTION OUTPUT ;
    USE SIGNAL ;
    PORT
      LAYER M4 ;
        RECT  17.196 20.4 17.28 20.424 ;
    END
  END q[5]
  PIN q[60]
    DIRECTION OUTPUT ;
    USE SIGNAL ;
    PORT
      LAYER M4 ;
        RECT  17.196 28.752 17.28 28.776 ;
    END
  END q[60]
  PIN q[61]
    DIRECTION OUTPUT ;
    USE SIGNAL ;
    PORT
      LAYER M4 ;
        RECT  17.196 28.848 17.28 28.872 ;
    END
  END q[61]
  PIN q[62]
    DIRECTION OUTPUT ;
    USE SIGNAL ;
    PORT
      LAYER M4 ;
        RECT  17.196 28.944 17.28 28.968 ;
    END
  END q[62]
  PIN q[63]
    DIRECTION OUTPUT ;
    USE SIGNAL ;
    PORT
      LAYER M4 ;
        RECT  17.196 29.04 17.28 29.064 ;
    END
  END q[63]
  PIN q[64]
    DIRECTION OUTPUT ;
    USE SIGNAL ;
    PORT
      LAYER M4 ;
        RECT  17.196 29.136 17.28 29.16 ;
    END
  END q[64]
  PIN q[65]
    DIRECTION OUTPUT ;
    USE SIGNAL ;
    PORT
      LAYER M4 ;
        RECT  17.196 29.232 17.28 29.256 ;
    END
  END q[65]
  PIN q[66]
    DIRECTION OUTPUT ;
    USE SIGNAL ;
    PORT
      LAYER M4 ;
        RECT  17.196 29.328 17.28 29.352 ;
    END
  END q[66]
  PIN q[67]
    DIRECTION OUTPUT ;
    USE SIGNAL ;
    PORT
      LAYER M4 ;
        RECT  17.196 29.424 17.28 29.448 ;
    END
  END q[67]
  PIN q[68]
    DIRECTION OUTPUT ;
    USE SIGNAL ;
    PORT
      LAYER M4 ;
        RECT  17.196 29.52 17.28 29.544 ;
    END
  END q[68]
  PIN q[69]
    DIRECTION OUTPUT ;
    USE SIGNAL ;
    PORT
      LAYER M4 ;
        RECT  17.196 29.616 17.28 29.64 ;
    END
  END q[69]
  PIN q[6]
    DIRECTION OUTPUT ;
    USE SIGNAL ;
    PORT
      LAYER M4 ;
        RECT  17.196 20.496 17.28 20.52 ;
    END
  END q[6]
  PIN q[70]
    DIRECTION OUTPUT ;
    USE SIGNAL ;
    PORT
      LAYER M4 ;
        RECT  17.196 29.712 17.28 29.736 ;
    END
  END q[70]
  PIN q[71]
    DIRECTION OUTPUT ;
    USE SIGNAL ;
    PORT
      LAYER M4 ;
        RECT  17.196 29.808 17.28 29.832 ;
    END
  END q[71]
  PIN q[72]
    DIRECTION OUTPUT ;
    USE SIGNAL ;
    PORT
      LAYER M4 ;
        RECT  17.196 29.904 17.28 29.928 ;
    END
  END q[72]
  PIN q[73]
    DIRECTION OUTPUT ;
    USE SIGNAL ;
    PORT
      LAYER M4 ;
        RECT  17.196 30 17.28 30.024 ;
    END
  END q[73]
  PIN q[74]
    DIRECTION OUTPUT ;
    USE SIGNAL ;
    PORT
      LAYER M4 ;
        RECT  17.196 30.096 17.28 30.12 ;
    END
  END q[74]
  PIN q[75]
    DIRECTION OUTPUT ;
    USE SIGNAL ;
    PORT
      LAYER M4 ;
        RECT  17.196 30.192 17.28 30.216 ;
    END
  END q[75]
  PIN q[76]
    DIRECTION OUTPUT ;
    USE SIGNAL ;
    PORT
      LAYER M4 ;
        RECT  17.196 30.288 17.28 30.312 ;
    END
  END q[76]
  PIN q[77]
    DIRECTION OUTPUT ;
    USE SIGNAL ;
    PORT
      LAYER M4 ;
        RECT  17.196 30.384 17.28 30.408 ;
    END
  END q[77]
  PIN q[78]
    DIRECTION OUTPUT ;
    USE SIGNAL ;
    PORT
      LAYER M4 ;
        RECT  17.196 30.48 17.28 30.504 ;
    END
  END q[78]
  PIN q[79]
    DIRECTION OUTPUT ;
    USE SIGNAL ;
    PORT
      LAYER M4 ;
        RECT  17.196 30.576 17.28 30.6 ;
    END
  END q[79]
  PIN q[7]
    DIRECTION OUTPUT ;
    USE SIGNAL ;
    PORT
      LAYER M4 ;
        RECT  17.196 20.592 17.28 20.616 ;
    END
  END q[7]
  PIN q[80]
    DIRECTION OUTPUT ;
    USE SIGNAL ;
    PORT
      LAYER M4 ;
        RECT  17.196 30.672 17.28 30.696 ;
    END
  END q[80]
  PIN q[81]
    DIRECTION OUTPUT ;
    USE SIGNAL ;
    PORT
      LAYER M4 ;
        RECT  17.196 30.768 17.28 30.792 ;
    END
  END q[81]
  PIN q[82]
    DIRECTION OUTPUT ;
    USE SIGNAL ;
    PORT
      LAYER M4 ;
        RECT  17.196 30.864 17.28 30.888 ;
    END
  END q[82]
  PIN q[83]
    DIRECTION OUTPUT ;
    USE SIGNAL ;
    PORT
      LAYER M4 ;
        RECT  17.196 30.96 17.28 30.984 ;
    END
  END q[83]
  PIN q[84]
    DIRECTION OUTPUT ;
    USE SIGNAL ;
    PORT
      LAYER M4 ;
        RECT  17.196 31.056 17.28 31.08 ;
    END
  END q[84]
  PIN q[85]
    DIRECTION OUTPUT ;
    USE SIGNAL ;
    PORT
      LAYER M4 ;
        RECT  17.196 31.152 17.28 31.176 ;
    END
  END q[85]
  PIN q[86]
    DIRECTION OUTPUT ;
    USE SIGNAL ;
    PORT
      LAYER M4 ;
        RECT  17.196 31.248 17.28 31.272 ;
    END
  END q[86]
  PIN q[87]
    DIRECTION OUTPUT ;
    USE SIGNAL ;
    PORT
      LAYER M4 ;
        RECT  17.196 31.344 17.28 31.368 ;
    END
  END q[87]
  PIN q[88]
    DIRECTION OUTPUT ;
    USE SIGNAL ;
    PORT
      LAYER M4 ;
        RECT  17.196 31.44 17.28 31.464 ;
    END
  END q[88]
  PIN q[89]
    DIRECTION OUTPUT ;
    USE SIGNAL ;
    PORT
      LAYER M4 ;
        RECT  17.196 31.536 17.28 31.56 ;
    END
  END q[89]
  PIN q[8]
    DIRECTION OUTPUT ;
    USE SIGNAL ;
    PORT
      LAYER M4 ;
        RECT  17.196 20.688 17.28 20.712 ;
    END
  END q[8]
  PIN q[90]
    DIRECTION OUTPUT ;
    USE SIGNAL ;
    PORT
      LAYER M4 ;
        RECT  17.196 31.632 17.28 31.656 ;
    END
  END q[90]
  PIN q[91]
    DIRECTION OUTPUT ;
    USE SIGNAL ;
    PORT
      LAYER M4 ;
        RECT  17.196 31.728 17.28 31.752 ;
    END
  END q[91]
  PIN q[92]
    DIRECTION OUTPUT ;
    USE SIGNAL ;
    PORT
      LAYER M4 ;
        RECT  17.196 31.824 17.28 31.848 ;
    END
  END q[92]
  PIN q[93]
    DIRECTION OUTPUT ;
    USE SIGNAL ;
    PORT
      LAYER M4 ;
        RECT  17.196 31.92 17.28 31.944 ;
    END
  END q[93]
  PIN q[94]
    DIRECTION OUTPUT ;
    USE SIGNAL ;
    PORT
      LAYER M4 ;
        RECT  17.196 32.016 17.28 32.04 ;
    END
  END q[94]
  PIN q[95]
    DIRECTION OUTPUT ;
    USE SIGNAL ;
    PORT
      LAYER M4 ;
        RECT  17.196 32.112 17.28 32.136 ;
    END
  END q[95]
  PIN q[96]
    DIRECTION OUTPUT ;
    USE SIGNAL ;
    PORT
      LAYER M4 ;
        RECT  17.196 22.992 17.28 23.016 ;
    END
  END q[96]
  PIN q[97]
    DIRECTION OUTPUT ;
    USE SIGNAL ;
    PORT
      LAYER M4 ;
        RECT  17.196 23.088 17.28 23.112 ;
    END
  END q[97]
  PIN q[98]
    DIRECTION OUTPUT ;
    USE SIGNAL ;
    PORT
      LAYER M4 ;
        RECT  17.196 23.184 17.28 23.208 ;
    END
  END q[98]
  PIN q[99]
    DIRECTION OUTPUT ;
    USE SIGNAL ;
    PORT
      LAYER M4 ;
        RECT  17.196 23.28 17.28 23.304 ;
    END
  END q[99]
  PIN q[9]
    DIRECTION OUTPUT ;
    USE SIGNAL ;
    PORT
      LAYER M4 ;
        RECT  17.196 20.784 17.28 20.808 ;
    END
  END q[9]
  PIN VDD
    DIRECTION INOUT ;
    USE POWER ;
    PORT
      LAYER M5 ;
        RECT  13.392 2.151 13.512 95.049 ;
        RECT  7.992 2.151 8.112 95.049 ;
        RECT  2.592 2.151 2.712 95.049 ;
    END
  END VDD
  PIN VSS
    DIRECTION INOUT ;
    USE GROUND ;
    PORT
      LAYER M5 ;
        RECT  13.2 2.137 13.32 95.063 ;
        RECT  7.8 2.137 7.92 95.063 ;
        RECT  2.4 2.137 2.52 95.063 ;
    END
  END VSS
  # OT_OBS_CLOSED layer=M5 d_um=1.536 added=104
  OBS
    LAYER RVTN ;
     RECT  2.16 2.16 15.12 2.295 ;
     RECT  2.16 2.565 15.12 2.835 ;
     RECT  2.16 3.105 15.12 3.375 ;
     RECT  2.16 3.645 15.12 3.915 ;
     RECT  2.16 4.185 15.12 4.455 ;
     RECT  2.16 4.725 15.12 4.995 ;
     RECT  2.16 5.265 15.12 5.535 ;
     RECT  2.16 5.805 15.12 6.075 ;
     RECT  2.16 6.345 15.12 6.615 ;
     RECT  2.16 6.885 15.12 7.155 ;
     RECT  2.16 7.425 15.12 7.695 ;
     RECT  2.16 7.965 15.12 8.235 ;
     RECT  2.16 8.505 15.12 8.775 ;
     RECT  2.16 9.045 15.12 9.315 ;
     RECT  2.16 9.585 15.12 9.855 ;
     RECT  2.16 10.125 15.12 10.395 ;
     RECT  2.16 10.665 15.12 10.935 ;
     RECT  2.16 11.205 15.12 11.475 ;
     RECT  2.16 11.745 15.12 12.015 ;
     RECT  2.16 12.285 15.12 12.555 ;
     RECT  2.16 12.825 15.12 13.095 ;
     RECT  2.16 13.365 15.12 13.635 ;
     RECT  2.16 13.905 15.12 14.175 ;
     RECT  2.16 14.445 15.12 14.715 ;
     RECT  2.16 14.985 15.12 15.255 ;
     RECT  2.16 15.525 15.12 15.795 ;
     RECT  2.16 16.065 15.12 16.335 ;
     RECT  2.16 16.605 15.12 16.875 ;
     RECT  2.16 17.145 15.12 17.415 ;
     RECT  2.16 17.685 15.12 17.955 ;
     RECT  2.16 18.225 15.12 18.495 ;
     RECT  2.16 18.765 15.12 19.035 ;
     RECT  2.16 19.305 15.12 19.575 ;
     RECT  2.16 19.845 15.12 20.115 ;
     RECT  2.16 20.385 15.12 20.655 ;
     RECT  2.16 20.925 15.12 21.195 ;
     RECT  2.16 21.465 15.12 21.735 ;
     RECT  2.16 22.005 15.12 22.275 ;
     RECT  2.16 22.545 15.12 22.815 ;
     RECT  2.16 23.085 15.12 23.355 ;
     RECT  2.16 23.625 15.12 23.895 ;
     RECT  2.16 24.165 15.12 24.435 ;
     RECT  2.16 24.705 15.12 24.975 ;
     RECT  2.16 25.245 15.12 25.515 ;
     RECT  2.16 25.785 15.12 26.055 ;
     RECT  2.16 26.325 15.12 26.595 ;
     RECT  2.16 26.865 15.12 27.135 ;
     RECT  2.16 27.405 15.12 27.675 ;
     RECT  2.16 27.945 15.12 28.215 ;
     RECT  2.16 28.485 15.12 28.755 ;
     RECT  2.16 29.025 15.12 29.295 ;
     RECT  2.16 29.565 15.12 29.835 ;
     RECT  2.16 30.105 15.12 30.375 ;
     RECT  2.16 30.645 15.12 30.915 ;
     RECT  2.16 31.185 15.12 31.455 ;
     RECT  2.16 31.725 15.12 31.995 ;
     RECT  2.16 32.265 15.12 32.535 ;
     RECT  2.16 32.805 15.12 33.075 ;
     RECT  2.16 33.345 15.12 33.615 ;
     RECT  2.16 33.885 15.12 34.155 ;
     RECT  2.16 34.425 15.12 34.695 ;
     RECT  2.16 34.965 15.12 35.235 ;
     RECT  2.16 35.505 15.12 35.775 ;
     RECT  2.16 36.045 15.12 36.315 ;
     RECT  2.16 36.585 15.12 36.855 ;
     RECT  2.16 37.125 15.12 37.395 ;
     RECT  2.16 37.665 15.12 37.935 ;
     RECT  2.16 38.205 15.12 38.475 ;
     RECT  2.16 38.745 15.12 39.015 ;
     RECT  2.16 39.285 15.12 39.555 ;
     RECT  2.16 39.825 15.12 40.095 ;
     RECT  2.16 40.365 15.12 40.635 ;
     RECT  2.16 40.905 15.12 41.175 ;
     RECT  2.16 41.445 15.12 41.715 ;
     RECT  2.16 41.985 15.12 42.255 ;
     RECT  2.16 42.525 15.12 42.795 ;
     RECT  2.16 43.065 15.12 43.335 ;
     RECT  2.16 43.605 15.12 43.875 ;
     RECT  2.16 44.145 15.12 44.415 ;
     RECT  2.16 44.685 15.12 44.955 ;
     RECT  2.16 45.225 15.12 45.495 ;
     RECT  2.16 45.765 15.12 46.035 ;
     RECT  2.16 46.305 15.12 46.575 ;
     RECT  2.16 46.845 15.12 47.115 ;
     RECT  2.16 47.385 15.12 47.655 ;
     RECT  2.16 47.925 15.12 48.195 ;
     RECT  2.16 48.465 15.12 48.735 ;
     RECT  2.16 49.005 15.12 49.275 ;
     RECT  2.16 49.545 15.12 49.815 ;
     RECT  2.16 50.085 15.12 50.355 ;
     RECT  2.16 50.625 15.12 50.895 ;
     RECT  2.16 51.165 15.12 51.435 ;
     RECT  2.16 51.705 15.12 51.975 ;
     RECT  2.16 52.245 15.12 52.515 ;
     RECT  2.16 52.785 15.12 53.055 ;
     RECT  2.16 53.325 15.12 53.595 ;
     RECT  2.16 53.865 15.12 54.135 ;
     RECT  2.16 54.405 15.12 54.675 ;
     RECT  2.16 54.945 15.12 55.215 ;
     RECT  2.16 55.485 15.12 55.755 ;
     RECT  2.16 56.025 15.12 56.295 ;
     RECT  2.16 56.565 15.12 56.835 ;
     RECT  2.16 57.105 15.12 57.375 ;
     RECT  2.16 57.645 15.12 57.915 ;
     RECT  2.16 58.185 15.12 58.455 ;
     RECT  2.16 58.725 15.12 58.995 ;
     RECT  2.16 59.265 15.12 59.535 ;
     RECT  2.16 59.805 15.12 60.075 ;
     RECT  2.16 60.345 15.12 60.615 ;
     RECT  2.16 60.885 15.12 61.155 ;
     RECT  2.16 61.425 15.12 61.695 ;
     RECT  2.16 61.965 15.12 62.235 ;
     RECT  2.16 62.505 15.12 62.775 ;
     RECT  2.16 63.045 15.12 63.315 ;
     RECT  2.16 63.585 15.12 63.855 ;
     RECT  2.16 64.125 15.12 64.395 ;
     RECT  2.16 64.665 15.12 64.935 ;
     RECT  2.16 65.205 15.12 65.475 ;
     RECT  2.16 65.745 15.12 66.015 ;
     RECT  2.16 66.285 15.12 66.555 ;
     RECT  2.16 66.825 15.12 67.095 ;
     RECT  2.16 67.365 15.12 67.635 ;
     RECT  2.16 67.905 15.12 68.175 ;
     RECT  2.16 68.445 15.12 68.715 ;
     RECT  2.16 68.985 15.12 69.255 ;
     RECT  2.16 69.525 15.12 69.795 ;
     RECT  2.16 70.065 15.12 70.335 ;
     RECT  2.16 70.605 15.12 70.875 ;
     RECT  2.16 71.145 15.12 71.415 ;
     RECT  2.16 71.685 15.12 71.955 ;
     RECT  2.16 72.225 15.12 72.495 ;
     RECT  2.16 72.765 15.12 73.035 ;
     RECT  2.16 73.305 15.12 73.575 ;
     RECT  2.16 73.845 15.12 74.115 ;
     RECT  2.16 74.385 15.12 74.655 ;
     RECT  2.16 74.925 15.12 75.195 ;
     RECT  2.16 75.465 15.12 75.735 ;
     RECT  2.16 76.005 15.12 76.275 ;
     RECT  2.16 76.545 15.12 76.815 ;
     RECT  2.16 77.085 15.12 77.355 ;
     RECT  2.16 77.625 15.12 77.895 ;
     RECT  2.16 78.165 15.12 78.435 ;
     RECT  2.16 78.705 15.12 78.975 ;
     RECT  2.16 79.245 15.12 79.515 ;
     RECT  2.16 79.785 15.12 80.055 ;
     RECT  2.16 80.325 15.12 80.595 ;
     RECT  2.16 80.865 15.12 81.135 ;
     RECT  2.16 81.405 15.12 81.675 ;
     RECT  2.16 81.945 15.12 82.215 ;
     RECT  2.16 82.485 15.12 82.755 ;
     RECT  2.16 83.025 15.12 83.295 ;
     RECT  2.16 83.565 15.12 83.835 ;
     RECT  2.16 84.105 15.12 84.375 ;
     RECT  2.16 84.645 15.12 84.915 ;
     RECT  2.16 85.185 15.12 85.455 ;
     RECT  2.16 85.725 15.12 85.995 ;
     RECT  2.16 86.265 15.12 86.535 ;
     RECT  2.16 86.805 15.12 87.075 ;
     RECT  2.16 87.345 15.12 87.615 ;
     RECT  2.16 87.885 15.12 88.155 ;
     RECT  2.16 88.425 15.12 88.695 ;
     RECT  2.16 88.965 15.12 89.235 ;
     RECT  2.16 89.505 15.12 89.775 ;
     RECT  2.16 90.045 15.12 90.315 ;
     RECT  2.16 90.585 15.12 90.855 ;
     RECT  2.16 91.125 15.12 91.395 ;
     RECT  2.16 91.665 15.12 91.935 ;
     RECT  2.16 92.205 15.12 92.475 ;
     RECT  2.16 92.745 15.12 93.015 ;
     RECT  2.16 93.285 15.12 93.555 ;
     RECT  2.16 93.825 15.12 94.095 ;
     RECT  2.16 94.365 15.12 94.635 ;
     RECT  2.16 94.905 15.12 95.04 ;
    LAYER RVTP ;
     RECT  2.16 2.295 15.12 2.565 ;
     RECT  2.16 2.835 15.12 3.105 ;
     RECT  2.16 3.375 15.12 3.645 ;
     RECT  2.16 3.915 15.12 4.185 ;
     RECT  2.16 4.455 15.12 4.725 ;
     RECT  2.16 4.995 15.12 5.265 ;
     RECT  2.16 5.535 15.12 5.805 ;
     RECT  2.16 6.075 15.12 6.345 ;
     RECT  2.16 6.615 15.12 6.885 ;
     RECT  2.16 7.155 15.12 7.425 ;
     RECT  2.16 7.695 15.12 7.965 ;
     RECT  2.16 8.235 15.12 8.505 ;
     RECT  2.16 8.775 15.12 9.045 ;
     RECT  2.16 9.315 15.12 9.585 ;
     RECT  2.16 9.855 15.12 10.125 ;
     RECT  2.16 10.395 15.12 10.665 ;
     RECT  2.16 10.935 15.12 11.205 ;
     RECT  2.16 11.475 15.12 11.745 ;
     RECT  2.16 12.015 15.12 12.285 ;
     RECT  2.16 12.555 15.12 12.825 ;
     RECT  2.16 13.095 15.12 13.365 ;
     RECT  2.16 13.635 15.12 13.905 ;
     RECT  2.16 14.175 15.12 14.445 ;
     RECT  2.16 14.715 15.12 14.985 ;
     RECT  2.16 15.255 15.12 15.525 ;
     RECT  2.16 15.795 15.12 16.065 ;
     RECT  2.16 16.335 15.12 16.605 ;
     RECT  2.16 16.875 15.12 17.145 ;
     RECT  2.16 17.415 15.12 17.685 ;
     RECT  2.16 17.955 15.12 18.225 ;
     RECT  2.16 18.495 15.12 18.765 ;
     RECT  2.16 19.035 15.12 19.305 ;
     RECT  2.16 19.575 15.12 19.845 ;
     RECT  2.16 20.115 15.12 20.385 ;
     RECT  2.16 20.655 15.12 20.925 ;
     RECT  2.16 21.195 15.12 21.465 ;
     RECT  2.16 21.735 15.12 22.005 ;
     RECT  2.16 22.275 15.12 22.545 ;
     RECT  2.16 22.815 15.12 23.085 ;
     RECT  2.16 23.355 15.12 23.625 ;
     RECT  2.16 23.895 15.12 24.165 ;
     RECT  2.16 24.435 15.12 24.705 ;
     RECT  2.16 24.975 15.12 25.245 ;
     RECT  2.16 25.515 15.12 25.785 ;
     RECT  2.16 26.055 15.12 26.325 ;
     RECT  2.16 26.595 15.12 26.865 ;
     RECT  2.16 27.135 15.12 27.405 ;
     RECT  2.16 27.675 15.12 27.945 ;
     RECT  2.16 28.215 15.12 28.485 ;
     RECT  2.16 28.755 15.12 29.025 ;
     RECT  2.16 29.295 15.12 29.565 ;
     RECT  2.16 29.835 15.12 30.105 ;
     RECT  2.16 30.375 15.12 30.645 ;
     RECT  2.16 30.915 15.12 31.185 ;
     RECT  2.16 31.455 15.12 31.725 ;
     RECT  2.16 31.995 15.12 32.265 ;
     RECT  2.16 32.535 15.12 32.805 ;
     RECT  2.16 33.075 15.12 33.345 ;
     RECT  2.16 33.615 15.12 33.885 ;
     RECT  2.16 34.155 15.12 34.425 ;
     RECT  2.16 34.695 15.12 34.965 ;
     RECT  2.16 35.235 15.12 35.505 ;
     RECT  2.16 35.775 15.12 36.045 ;
     RECT  2.16 36.315 15.12 36.585 ;
     RECT  2.16 36.855 15.12 37.125 ;
     RECT  2.16 37.395 15.12 37.665 ;
     RECT  2.16 37.935 15.12 38.205 ;
     RECT  2.16 38.475 15.12 38.745 ;
     RECT  2.16 39.015 15.12 39.285 ;
     RECT  2.16 39.555 15.12 39.825 ;
     RECT  2.16 40.095 15.12 40.365 ;
     RECT  2.16 40.635 15.12 40.905 ;
     RECT  2.16 41.175 15.12 41.445 ;
     RECT  2.16 41.715 15.12 41.985 ;
     RECT  2.16 42.255 15.12 42.525 ;
     RECT  2.16 42.795 15.12 43.065 ;
     RECT  2.16 43.335 15.12 43.605 ;
     RECT  2.16 43.875 15.12 44.145 ;
     RECT  2.16 44.415 15.12 44.685 ;
     RECT  2.16 44.955 15.12 45.225 ;
     RECT  2.16 45.495 15.12 45.765 ;
     RECT  2.16 46.035 15.12 46.305 ;
     RECT  2.16 46.575 15.12 46.845 ;
     RECT  2.16 47.115 15.12 47.385 ;
     RECT  2.16 47.655 15.12 47.925 ;
     RECT  2.16 48.195 15.12 48.465 ;
     RECT  2.16 48.735 15.12 49.005 ;
     RECT  2.16 49.275 15.12 49.545 ;
     RECT  2.16 49.815 15.12 50.085 ;
     RECT  2.16 50.355 15.12 50.625 ;
     RECT  2.16 50.895 15.12 51.165 ;
     RECT  2.16 51.435 15.12 51.705 ;
     RECT  2.16 51.975 15.12 52.245 ;
     RECT  2.16 52.515 15.12 52.785 ;
     RECT  2.16 53.055 15.12 53.325 ;
     RECT  2.16 53.595 15.12 53.865 ;
     RECT  2.16 54.135 15.12 54.405 ;
     RECT  2.16 54.675 15.12 54.945 ;
     RECT  2.16 55.215 15.12 55.485 ;
     RECT  2.16 55.755 15.12 56.025 ;
     RECT  2.16 56.295 15.12 56.565 ;
     RECT  2.16 56.835 15.12 57.105 ;
     RECT  2.16 57.375 15.12 57.645 ;
     RECT  2.16 57.915 15.12 58.185 ;
     RECT  2.16 58.455 15.12 58.725 ;
     RECT  2.16 58.995 15.12 59.265 ;
     RECT  2.16 59.535 15.12 59.805 ;
     RECT  2.16 60.075 15.12 60.345 ;
     RECT  2.16 60.615 15.12 60.885 ;
     RECT  2.16 61.155 15.12 61.425 ;
     RECT  2.16 61.695 15.12 61.965 ;
     RECT  2.16 62.235 15.12 62.505 ;
     RECT  2.16 62.775 15.12 63.045 ;
     RECT  2.16 63.315 15.12 63.585 ;
     RECT  2.16 63.855 15.12 64.125 ;
     RECT  2.16 64.395 15.12 64.665 ;
     RECT  2.16 64.935 15.12 65.205 ;
     RECT  2.16 65.475 15.12 65.745 ;
     RECT  2.16 66.015 15.12 66.285 ;
     RECT  2.16 66.555 15.12 66.825 ;
     RECT  2.16 67.095 15.12 67.365 ;
     RECT  2.16 67.635 15.12 67.905 ;
     RECT  2.16 68.175 15.12 68.445 ;
     RECT  2.16 68.715 15.12 68.985 ;
     RECT  2.16 69.255 15.12 69.525 ;
     RECT  2.16 69.795 15.12 70.065 ;
     RECT  2.16 70.335 15.12 70.605 ;
     RECT  2.16 70.875 15.12 71.145 ;
     RECT  2.16 71.415 15.12 71.685 ;
     RECT  2.16 71.955 15.12 72.225 ;
     RECT  2.16 72.495 15.12 72.765 ;
     RECT  2.16 73.035 15.12 73.305 ;
     RECT  2.16 73.575 15.12 73.845 ;
     RECT  2.16 74.115 15.12 74.385 ;
     RECT  2.16 74.655 15.12 74.925 ;
     RECT  2.16 75.195 15.12 75.465 ;
     RECT  2.16 75.735 15.12 76.005 ;
     RECT  2.16 76.275 15.12 76.545 ;
     RECT  2.16 76.815 15.12 77.085 ;
     RECT  2.16 77.355 15.12 77.625 ;
     RECT  2.16 77.895 15.12 78.165 ;
     RECT  2.16 78.435 15.12 78.705 ;
     RECT  2.16 78.975 15.12 79.245 ;
     RECT  2.16 79.515 15.12 79.785 ;
     RECT  2.16 80.055 15.12 80.325 ;
     RECT  2.16 80.595 15.12 80.865 ;
     RECT  2.16 81.135 15.12 81.405 ;
     RECT  2.16 81.675 15.12 81.945 ;
     RECT  2.16 82.215 15.12 82.485 ;
     RECT  2.16 82.755 15.12 83.025 ;
     RECT  2.16 83.295 15.12 83.565 ;
     RECT  2.16 83.835 15.12 84.105 ;
     RECT  2.16 84.375 15.12 84.645 ;
     RECT  2.16 84.915 15.12 85.185 ;
     RECT  2.16 85.455 15.12 85.725 ;
     RECT  2.16 85.995 15.12 86.265 ;
     RECT  2.16 86.535 15.12 86.805 ;
     RECT  2.16 87.075 15.12 87.345 ;
     RECT  2.16 87.615 15.12 87.885 ;
     RECT  2.16 88.155 15.12 88.425 ;
     RECT  2.16 88.695 15.12 88.965 ;
     RECT  2.16 89.235 15.12 89.505 ;
     RECT  2.16 89.775 15.12 90.045 ;
     RECT  2.16 90.315 15.12 90.585 ;
     RECT  2.16 90.855 15.12 91.125 ;
     RECT  2.16 91.395 15.12 91.665 ;
     RECT  2.16 91.935 15.12 92.205 ;
     RECT  2.16 92.475 15.12 92.745 ;
     RECT  2.16 93.015 15.12 93.285 ;
     RECT  2.16 93.555 15.12 93.825 ;
     RECT  2.16 94.095 15.12 94.365 ;
     RECT  2.16 94.635 15.12 94.905 ;
    LAYER M1 ;
     RECT  2.16 2.151 15.12 95.049 ;
    LAYER M2 ;
     RECT  0.031 16.65 0.067 16.668 ;
     RECT  0.031 22.014 0.067 22.032 ;
     RECT  0.031 32.238 0.067 32.256 ;
     RECT  0.067 21.321 0.103 22.608 ;
     RECT  0.067 27.378 0.103 27.396 ;
     RECT  0.067 32.202 0.103 32.256 ;
     RECT  0.067 33.93 0.103 33.948 ;
     RECT  0.031 35.748 0.103 35.766 ;
     RECT  0.067 36.792 0.103 36.81 ;
     RECT  0.031 55.188 0.103 55.206 ;
     RECT  0.031 60.12 0.103 60.138 ;
     RECT  0.031 78.561 0.103 78.579 ;
     RECT  0.103 35.28 0.131 35.766 ;
     RECT  0.067 16.11 0.139 16.668 ;
     RECT  0.103 17.424 0.139 17.442 ;
     RECT  0.031 24.372 0.139 24.39 ;
     RECT  0.103 31.041 0.139 31.059 ;
     RECT  0.103 32.202 0.139 32.328 ;
     RECT  0.067 47.7 0.139 47.718 ;
     RECT  0.103 52.722 0.139 52.74 ;
     RECT  0.103 54.144 0.139 55.206 ;
     RECT  0.067 69.156 0.139 69.174 ;
     RECT  0.103 70.002 0.139 70.02 ;
     RECT  0.031 28.836 0.167 28.854 ;
     RECT  0.103 36.792 0.167 37.116 ;
     RECT  0.067 61.974 0.167 61.992 ;
     RECT  0.139 16.11 0.175 17.442 ;
     RECT  0.103 18.81 0.175 18.828 ;
     RECT  0.103 20.511 0.175 20.529 ;
     RECT  0.103 21.321 0.175 23.148 ;
     RECT  0.103 27.378 0.175 27.9 ;
     RECT  0.139 52.182 0.175 52.74 ;
     RECT  0.139 54.144 0.175 55.278 ;
     RECT  0.103 73.548 0.175 73.566 ;
     RECT  0.103 46.161 0.203 46.179 ;
     RECT  0.103 78.561 0.203 78.66 ;
     RECT  0.139 30.888 0.211 31.059 ;
     RECT  0.139 32.04 0.211 32.328 ;
     RECT  0.067 65.682 0.211 65.7 ;
     RECT  0.139 69.156 0.211 70.02 ;
     RECT  0.139 70.776 0.211 70.794 ;
     RECT  0.067 75.51 0.211 75.528 ;
     RECT  0.139 47.7 0.239 47.916 ;
     RECT  0.175 18.81 0.247 19.224 ;
     RECT  0.211 32.04 0.247 32.49 ;
     RECT  0.103 33.39 0.247 34.182 ;
     RECT  0.067 50.832 0.247 50.85 ;
     RECT  0.175 52.182 0.247 55.278 ;
     RECT  0.103 59.472 0.247 60.138 ;
     RECT  0.211 30.852 0.275 31.059 ;
     RECT  0.139 63.324 0.275 63.342 ;
     RECT  0.103 26.1 0.283 26.118 ;
     RECT  0.175 27.18 0.283 28.476 ;
     RECT  0.247 50.832 0.283 51.228 ;
     RECT  0.103 58.536 0.283 58.644 ;
     RECT  0.211 69.066 0.283 70.794 ;
     RECT  0.211 75.204 0.283 75.528 ;
     RECT  0.247 18.468 0.319 19.224 ;
     RECT  0.175 20.511 0.319 23.148 ;
     RECT  0.139 23.904 0.319 25.119 ;
     RECT  0.283 68.418 0.319 70.794 ;
     RECT  0.175 72.621 0.319 72.639 ;
     RECT  0.247 77.094 0.319 77.112 ;
     RECT  0.319 72 0.355 72.639 ;
     RECT  0.175 73.548 0.355 74.106 ;
     RECT  0.355 72 0.391 74.106 ;
     RECT  0.103 40.914 0.427 40.932 ;
     RECT  0.283 75.204 0.427 75.96 ;
     RECT  0.103 39.222 0.463 39.888 ;
     RECT  0.427 40.644 0.463 40.932 ;
     RECT  0.283 58.158 0.463 58.644 ;
     RECT  0.391 72 0.499 74.214 ;
     RECT  0.427 75.204 0.499 76.338 ;
     RECT  0.167 37.098 0.535 37.116 ;
     RECT  0.175 37.98 0.535 37.998 ;
     RECT  0.463 39.222 0.535 40.932 ;
     RECT  0.103 42.732 0.535 42.75 ;
     RECT  0.283 50.832 0.535 51.39 ;
     RECT  0.247 52.182 0.535 55.359 ;
     RECT  0.463 58.041 0.535 58.644 ;
     RECT  0.247 59.472 0.535 60.84 ;
     RECT  0.499 72 0.571 76.338 ;
     RECT  0.103 79.524 0.571 79.542 ;
     RECT  0.239 47.898 0.599 47.916 ;
     RECT  0.319 20.511 0.751 25.119 ;
     RECT  0.283 26.1 0.751 28.476 ;
     RECT  0.319 68.112 0.751 70.794 ;
     RECT  0.571 71.694 0.751 76.338 ;
     RECT  0.067 29.61 0.779 29.628 ;
     RECT  0.751 20.511 0.787 28.476 ;
     RECT  0.535 57.96 0.787 60.84 ;
     RECT  0.319 77.094 0.787 77.31 ;
     RECT  0.355 78.102 0.787 78.12 ;
     RECT  0.175 16.11 0.823 17.712 ;
     RECT  0.751 68.112 0.851 76.338 ;
     RECT  0.031 81.612 0.859 81.63 ;
     RECT  0.787 57.924 0.895 60.84 ;
     RECT  0.275 30.852 0.931 31.014 ;
     RECT  0.895 57.924 0.931 61.146 ;
     RECT  0.787 77.094 0.931 78.12 ;
     RECT  0.859 14.22 0.967 14.238 ;
     RECT  0.931 57.312 0.967 61.146 ;
     RECT  0.319 18.468 1.003 19.296 ;
     RECT  0.535 50.832 1.039 55.359 ;
     RECT  0.851 68.922 1.039 76.338 ;
     RECT  0.931 77.094 1.039 78.264 ;
     RECT  0.967 14.22 1.075 14.778 ;
     RECT  0.823 15.84 1.075 17.712 ;
     RECT  1.075 14.22 1.111 17.712 ;
     RECT  1.003 18.468 1.111 19.368 ;
     RECT  0.967 57.312 1.111 61.38 ;
     RECT  0.103 49.212 1.147 49.23 ;
     RECT  0.823 64.602 1.147 64.62 ;
     RECT  0.211 65.682 1.147 65.772 ;
     RECT  0.851 68.112 1.147 68.13 ;
     RECT  1.039 50.832 1.183 56.052 ;
     RECT  1.111 56.88 1.183 61.38 ;
     RECT  1.147 64.602 1.183 65.772 ;
     RECT  1.183 64.602 1.255 66.51 ;
     RECT  0.859 48.132 1.327 48.42 ;
     RECT  1.147 49.212 1.327 49.842 ;
     RECT  1.255 64.602 1.327 66.78 ;
     RECT  1.147 67.572 1.327 68.13 ;
     RECT  0.571 79.524 1.327 79.614 ;
     RECT  1.183 50.832 1.363 61.38 ;
     RECT  0.859 62.172 1.363 62.19 ;
     RECT  1.327 79.524 1.363 80.28 ;
     RECT  1.363 50.832 1.399 62.19 ;
     RECT  1.363 79.182 1.399 80.28 ;
     RECT  1.399 79.182 1.435 80.55 ;
     RECT  0.859 81.342 1.435 81.63 ;
     RECT  0.931 30.69 1.471 31.014 ;
     RECT  1.471 30.69 1.507 31.248 ;
     RECT  0.247 32.04 1.507 34.182 ;
     RECT  1.327 64.602 1.507 68.13 ;
     RECT  1.399 50.832 1.579 62.46 ;
     RECT  1.039 68.922 1.579 78.264 ;
     RECT  1.435 79.182 1.579 81.63 ;
     RECT  1.507 30.69 1.687 34.182 ;
     RECT  1.111 14.22 1.723 19.368 ;
     RECT  0.787 20.124 1.723 28.476 ;
     RECT  1.687 30.15 1.723 34.182 ;
     RECT  1.579 50.832 1.723 63 ;
     RECT  1.723 50.832 1.759 63.54 ;
     RECT  1.507 64.332 1.759 68.13 ;
     RECT  1.327 48.132 1.795 49.842 ;
     RECT  1.723 46.584 1.831 46.602 ;
     RECT  1.723 14.22 1.975 28.476 ;
     RECT  1.795 48.132 2.047 50.04 ;
     RECT  1.759 50.832 2.047 68.13 ;
     RECT  1.975 13.572 2.16 28.476 ;
     RECT  1.723 29.538 2.16 34.182 ;
     RECT  0.131 35.28 2.16 35.298 ;
     RECT  0.535 36.324 2.16 36.342 ;
     RECT  0.535 37.098 2.16 37.998 ;
     RECT  0.535 39.222 2.16 42.75 ;
     RECT  0.103 43.812 2.16 43.83 ;
     RECT  1.831 46.584 2.16 46.872 ;
     RECT  2.047 48.132 2.16 68.13 ;
     RECT  1.579 68.922 2.16 81.63 ;
     RECT  2.16 2.151 15.12 95.049 ;
     RECT  15.12 18.432 15.143 59.634 ;
     RECT  15.12 62.712 15.143 79.164 ;
     RECT  15.12 81.648 15.179 82.314 ;
     RECT  15.12 80.496 15.251 80.892 ;
     RECT  15.143 63.396 15.287 79.164 ;
     RECT  15.287 63.396 15.323 78.624 ;
     RECT  15.143 18.432 15.395 59.094 ;
     RECT  15.323 63.396 15.395 77.922 ;
     RECT  15.12 15.3 15.683 15.894 ;
     RECT  15.12 61.056 15.683 61.074 ;
     RECT  15.179 81.648 15.683 81.864 ;
     RECT  15.12 17.496 15.719 17.604 ;
     RECT  15.251 80.496 15.719 80.784 ;
     RECT  15.719 80.496 15.791 80.514 ;
     RECT  15.395 63.396 15.935 77.616 ;
     RECT  15.719 17.496 15.971 17.514 ;
     RECT  15.395 19.656 15.971 59.094 ;
     RECT  15.935 76.446 15.971 77.616 ;
     RECT  15.935 63.396 16.043 75.654 ;
     RECT  15.971 19.656 16.079 56.754 ;
     RECT  16.043 64.098 16.079 65.736 ;
     RECT  15.683 15.336 16.259 15.894 ;
     RECT  15.683 81.648 16.259 81.666 ;
     RECT  16.259 15.876 16.331 15.894 ;
     RECT  16.079 21.006 16.439 56.754 ;
     RECT  15.971 57.546 16.439 59.094 ;
     RECT  16.079 64.098 16.439 65.664 ;
     RECT  16.439 21.006 16.475 38.124 ;
     RECT  16.439 39.294 16.475 56.664 ;
     RECT  16.043 66.726 16.475 75.654 ;
     RECT  15.395 18.432 16.511 18.684 ;
     RECT  16.475 21.006 16.511 25.434 ;
     RECT  16.475 26.334 16.511 35.424 ;
     RECT  16.475 36.216 16.511 38.124 ;
     RECT  16.475 39.294 16.511 55.746 ;
     RECT  16.439 57.618 16.511 59.094 ;
     RECT  16.439 64.368 16.511 65.664 ;
     RECT  16.475 66.726 16.511 68.094 ;
     RECT  16.475 69.966 16.511 75.654 ;
     RECT  16.079 19.656 16.547 20.106 ;
     RECT  16.511 26.568 16.547 31.374 ;
     RECT  16.511 39.294 16.547 42.858 ;
     RECT  16.511 43.686 16.547 45.792 ;
     RECT  16.511 51.444 16.547 52.614 ;
     RECT  16.511 54.414 16.547 55.746 ;
     RECT  16.511 66.726 16.547 67.734 ;
     RECT  15.971 76.446 16.547 77.184 ;
     RECT  16.547 19.926 16.583 20.106 ;
     RECT  16.547 26.721 16.583 31.374 ;
     RECT  16.547 51.786 16.583 52.614 ;
     RECT  16.475 56.538 16.583 56.664 ;
     RECT  16.547 66.798 16.583 67.626 ;
     RECT  16.583 19.926 16.619 20.034 ;
     RECT  16.583 66.798 16.619 66.816 ;
     RECT  16.547 43.686 16.979 44.136 ;
     RECT  16.511 46.584 16.979 50.688 ;
     RECT  16.979 43.686 17.015 44.1 ;
     RECT  16.547 40.986 17.051 42.858 ;
     RECT  17.015 43.686 17.051 44.064 ;
     RECT  16.511 23.706 17.087 25.434 ;
     RECT  16.547 39.294 17.087 40.194 ;
     RECT  16.547 45.432 17.087 45.594 ;
     RECT  16.511 58.266 17.087 59.094 ;
     RECT  16.511 70.146 17.087 73.332 ;
     RECT  17.087 23.976 17.123 25.434 ;
     RECT  17.051 41.616 17.123 42.858 ;
     RECT  16.547 54.576 17.123 55.674 ;
     RECT  17.087 70.146 17.123 73.296 ;
     RECT  16.547 76.446 17.123 76.734 ;
     RECT  16.619 19.926 17.159 19.944 ;
     RECT  16.583 27.45 17.159 29.862 ;
     RECT  16.583 30.618 17.159 31.374 ;
     RECT  16.511 34.056 17.159 35.424 ;
     RECT  16.511 37.17 17.159 38.124 ;
     RECT  17.123 41.886 17.159 42.858 ;
     RECT  16.979 46.584 17.159 48.762 ;
     RECT  16.979 49.518 17.159 50.688 ;
     RECT  16.583 51.948 17.159 52.614 ;
     RECT  17.123 54.576 17.159 54.774 ;
     RECT  17.123 55.566 17.159 55.674 ;
     RECT  17.087 58.266 17.159 58.284 ;
     RECT  16.475 68.958 17.159 69.084 ;
     RECT  17.123 70.146 17.159 72.864 ;
     RECT  16.511 74.358 17.159 75.024 ;
     RECT  17.123 76.716 17.159 76.734 ;
     RECT  16.511 18.432 17.195 18.45 ;
     RECT  16.511 21.006 17.195 22.842 ;
     RECT  17.123 24.174 17.195 25.434 ;
     RECT  17.159 27.45 17.195 27.468 ;
     RECT  17.159 28.494 17.195 29.862 ;
     RECT  17.159 30.618 17.195 30.636 ;
     RECT  16.511 32.472 17.195 32.49 ;
     RECT  17.159 34.506 17.195 35.424 ;
     RECT  17.159 37.476 17.195 38.124 ;
     RECT  17.087 39.528 17.195 40.194 ;
     RECT  17.159 42.03 17.195 42.048 ;
     RECT  17.159 42.84 17.195 42.858 ;
     RECT  17.051 43.686 17.195 43.704 ;
     RECT  17.087 45.432 17.195 45.45 ;
     RECT  17.159 46.584 17.195 46.908 ;
     RECT  17.159 47.736 17.195 47.88 ;
     RECT  17.159 48.744 17.195 48.762 ;
     RECT  17.159 49.518 17.195 49.806 ;
     RECT  17.159 51.948 17.195 51.966 ;
     RECT  17.159 54.576 17.195 54.594 ;
     RECT  17.159 55.656 17.195 55.674 ;
     RECT  16.583 56.646 17.195 56.664 ;
     RECT  17.087 59.076 17.195 59.094 ;
     RECT  16.511 64.368 17.195 64.962 ;
     RECT  17.159 69.066 17.195 69.084 ;
     RECT  17.159 70.38 17.195 70.398 ;
     RECT  17.159 71.694 17.195 72.054 ;
     RECT  17.159 72.846 17.195 72.864 ;
     RECT  17.159 74.358 17.195 74.376 ;
     RECT  17.195 22.014 17.231 22.842 ;
     RECT  17.231 22.626 17.267 22.644 ;
     RECT  17.195 24.714 17.267 24.732 ;
    LAYER M3 ;
     RECT  4.392 1.723 4.41 2.255 ;
     RECT  2.415 2.143 2.505 2.413 ;
     RECT  7.815 2.143 7.905 2.413 ;
     RECT  13.215 2.143 13.305 2.413 ;
     RECT  4.608 2.263 4.626 3.065 ;
     RECT  13.215 2.413 13.497 5.071 ;
     RECT  11.988 5.071 13.497 5.305 ;
     RECT  11.988 5.305 13.806 5.341 ;
     RECT  11.988 5.341 14.202 5.503 ;
     RECT  11.916 5.503 14.202 5.539 ;
     RECT  11.808 5.539 14.202 5.575 ;
     RECT  11.736 5.575 14.202 5.611 ;
     RECT  7.815 2.413 8.097 5.737 ;
     RECT  11.736 5.611 14.274 5.773 ;
     RECT  11.664 5.773 14.274 5.909 ;
     RECT  11.664 5.909 13.806 5.999 ;
     RECT  2.415 2.413 2.697 6.115 ;
     RECT  10.836 6.151 10.854 6.269 ;
     RECT  7.164 5.737 8.097 6.385 ;
     RECT  6.84 6.385 8.097 6.647 ;
     RECT  2.415 6.115 2.79 6.655 ;
     RECT  11.736 5.999 13.806 6.683 ;
     RECT  7.308 6.647 8.097 7.151 ;
     RECT  2.304 6.655 3.006 7.195 ;
     RECT  10.98 6.817 10.998 7.195 ;
     RECT  14.76 7.231 14.778 7.349 ;
     RECT  10.548 7.195 11.07 7.393 ;
     RECT  11.808 6.683 13.806 7.393 ;
     RECT  7.632 7.151 8.097 7.465 ;
     RECT  8.892 5.881 8.91 7.465 ;
     RECT  6.84 7.393 6.858 7.619 ;
     RECT  10.116 7.393 11.07 7.771 ;
     RECT  11.808 7.393 14.022 7.771 ;
     RECT  10.116 7.771 14.022 7.861 ;
     RECT  7.632 7.465 8.91 7.889 ;
     RECT  7.632 7.889 8.766 7.961 ;
     RECT  7.815 7.961 8.766 7.997 ;
     RECT  10.116 7.861 14.058 8.005 ;
     RECT  9.684 8.005 14.058 8.239 ;
     RECT  6.984 8.401 7.002 8.501 ;
     RECT  7.815 7.997 8.097 8.815 ;
     RECT  7.815 8.815 8.298 8.969 ;
     RECT  9.648 8.239 14.058 8.969 ;
     RECT  6.768 8.977 6.786 9.239 ;
     RECT  5.796 5.809 5.814 9.355 ;
     RECT  4.824 3.181 4.842 9.625 ;
     RECT  6.84 9.481 6.858 9.653 ;
     RECT  9.756 8.969 14.058 9.661 ;
     RECT  7.815 8.969 8.226 9.739 ;
     RECT  9.756 9.661 14.67 9.851 ;
     RECT  7.815 9.739 8.802 9.931 ;
     RECT  9.756 9.851 14.238 9.931 ;
     RECT  7.815 9.931 14.238 9.965 ;
     RECT  7.815 9.965 14.058 10.165 ;
     RECT  4.572 9.625 4.842 10.327 ;
     RECT  5.58 9.355 5.814 10.327 ;
     RECT  7.164 10.165 14.058 10.399 ;
     RECT  2.304 7.195 3.69 10.435 ;
     RECT  4.572 10.327 5.814 10.435 ;
     RECT  6.84 10.399 14.058 10.499 ;
     RECT  7.164 10.499 14.058 10.589 ;
     RECT  7.272 10.589 14.058 10.697 ;
     RECT  2.304 10.435 5.814 10.831 ;
     RECT  2.304 10.831 5.886 11.209 ;
     RECT  2.304 11.209 6.03 11.281 ;
     RECT  9.972 10.697 14.058 11.281 ;
     RECT  7.272 10.697 9.234 11.309 ;
     RECT  2.304 11.281 6.066 11.399 ;
     RECT  9.972 11.281 14.238 11.399 ;
     RECT  9.972 11.399 14.166 11.471 ;
     RECT  7.815 11.309 9.234 11.551 ;
     RECT  9.972 11.471 14.058 11.551 ;
     RECT  7.02 11.407 7.038 11.939 ;
     RECT  2.304 11.399 6.03 12.325 ;
     RECT  6.84 12.055 6.858 12.325 ;
     RECT  7.815 11.551 14.058 12.361 ;
     RECT  7.815 12.361 14.094 12.451 ;
     RECT  7.815 12.451 14.238 12.551 ;
     RECT  2.304 12.325 6.858 12.829 ;
     RECT  7.815 12.551 8.154 12.829 ;
     RECT  2.304 12.829 8.154 13.369 ;
     RECT  8.928 12.551 14.238 13.369 ;
     RECT  2.304 13.369 14.238 13.567 ;
     RECT  1.98 13.567 14.238 14.485 ;
     RECT  1.98 14.485 14.706 14.521 ;
     RECT  0.864 14.215 0.882 14.755 ;
     RECT  0.864 14.755 0.99 15.295 ;
     RECT  1.98 14.521 14.994 15.295 ;
     RECT  1.98 15.295 15.678 15.331 ;
     RECT  1.98 15.331 16.254 15.359 ;
     RECT  0.864 15.295 1.098 15.565 ;
     RECT  1.98 15.359 14.922 15.565 ;
     RECT  0.864 15.565 14.922 15.835 ;
     RECT  15.66 15.359 16.254 15.871 ;
     RECT  0.072 16.105 0.09 16.645 ;
     RECT  0.036 16.645 0.09 16.915 ;
     RECT  0.828 15.835 14.922 16.915 ;
     RECT  0.036 16.915 14.922 16.951 ;
     RECT  15.66 15.871 16.326 16.951 ;
     RECT  0.036 16.951 16.326 18.661 ;
     RECT  17.172 18.427 17.19 18.661 ;
     RECT  0.036 18.661 17.19 22.009 ;
     RECT  0.036 22.009 17.226 22.037 ;
     RECT  0.072 22.037 17.226 22.621 ;
     RECT  0.072 22.621 17.262 23.789 ;
     RECT  0.072 23.789 15.066 23.981 ;
     RECT  16.02 23.789 17.262 24.077 ;
     RECT  0.072 23.981 14.994 24.367 ;
     RECT  16.056 24.077 17.262 24.461 ;
     RECT  16.416 24.461 17.262 24.737 ;
     RECT  16.416 24.737 17.19 25.439 ;
     RECT  16.416 25.439 17.118 25.469 ;
     RECT  16.416 25.469 16.506 25.717 ;
     RECT  15.984 25.717 16.506 25.901 ;
     RECT  16.056 25.901 16.506 26.563 ;
     RECT  0.036 24.367 14.994 26.599 ;
     RECT  16.056 26.563 16.542 26.671 ;
     RECT  15.984 26.671 16.542 26.716 ;
     RECT  0.036 26.599 15.174 26.744 ;
     RECT  15.984 26.716 16.578 26.861 ;
     RECT  16.056 26.861 16.578 27.115 ;
     RECT  16.056 27.115 17.19 27.607 ;
     RECT  0.036 26.744 14.994 27.643 ;
     RECT  15.984 27.607 17.19 27.643 ;
     RECT  0.036 27.643 17.19 28.205 ;
     RECT  0.036 28.205 14.994 28.859 ;
     RECT  15.948 28.205 17.19 28.939 ;
     RECT  0.108 28.859 14.994 29.323 ;
     RECT  15.912 28.939 17.19 29.323 ;
     RECT  0.108 29.323 17.19 29.605 ;
     RECT  0.072 29.605 17.19 29.867 ;
     RECT  0.072 29.867 17.046 29.939 ;
     RECT  0.072 29.939 5.454 30.137 ;
     RECT  0.072 30.137 5.346 30.479 ;
     RECT  0.072 30.479 5.274 30.569 ;
     RECT  0.072 30.569 5.094 30.611 ;
     RECT  6.192 29.939 17.046 30.613 ;
     RECT  6.192 30.613 17.19 31.181 ;
     RECT  0.072 30.611 5.022 31.495 ;
     RECT  6.192 31.181 14.994 31.495 ;
     RECT  0.072 31.495 14.994 31.559 ;
     RECT  0.072 31.559 5.526 31.757 ;
     RECT  15.948 31.181 17.19 31.757 ;
     RECT  0.072 31.757 5.238 32.233 ;
     RECT  6.264 31.559 14.994 32.251 ;
     RECT  6.264 32.251 15.426 32.297 ;
     RECT  6.264 32.297 14.994 32.477 ;
     RECT  16.416 31.757 17.19 32.491 ;
     RECT  0.036 32.233 5.238 32.611 ;
     RECT  6.264 32.477 14.886 32.611 ;
     RECT  15.948 32.491 17.19 32.621 ;
     RECT  15.948 32.621 17.154 33.079 ;
     RECT  15.912 33.079 17.154 33.197 ;
     RECT  0.036 32.611 14.886 33.349 ;
     RECT  0.036 33.349 14.922 33.539 ;
     RECT  15.912 33.197 16.506 34.051 ;
     RECT  15.912 34.051 17.154 34.157 ;
     RECT  16.38 34.157 17.154 34.501 ;
     RECT  0.036 33.539 14.85 34.733 ;
     RECT  0.936 34.733 14.85 34.735 ;
     RECT  16.38 34.501 17.19 35.311 ;
     RECT  16.344 35.311 17.19 35.429 ;
     RECT  16.344 35.429 17.118 35.453 ;
     RECT  0.936 34.735 15.426 35.609 ;
     RECT  0.936 35.609 14.742 35.735 ;
     RECT  0.036 34.733 0.198 35.771 ;
     RECT  0.936 35.735 14.562 35.981 ;
     RECT  16.344 35.453 16.542 36.235 ;
     RECT  0.072 35.771 0.198 36.319 ;
     RECT  0.936 35.981 0.954 36.319 ;
     RECT  2.052 35.981 14.562 36.365 ;
     RECT  16.344 36.235 17.19 36.427 ;
     RECT  2.16 36.365 14.562 36.461 ;
     RECT  0.072 36.319 0.954 36.557 ;
     RECT  2.268 36.461 14.562 36.571 ;
     RECT  0.072 36.557 0.558 36.815 ;
     RECT  2.268 36.571 14.598 36.895 ;
     RECT  15.984 36.427 17.19 37.129 ;
     RECT  2.268 36.895 14.814 37.325 ;
     RECT  2.304 37.325 14.814 37.589 ;
     RECT  2.304 37.589 5.13 37.625 ;
     RECT  15.948 37.129 17.19 37.675 ;
     RECT  0.108 36.815 0.558 37.709 ;
     RECT  0.108 37.709 0.342 37.901 ;
     RECT  15.912 37.675 17.19 37.931 ;
     RECT  6.012 37.589 14.814 38.059 ;
     RECT  17.172 37.931 17.19 38.129 ;
     RECT  15.912 37.931 16.434 38.201 ;
     RECT  6.012 38.059 14.886 38.209 ;
     RECT  0.108 37.901 0.198 38.285 ;
     RECT  6.012 38.209 15.39 38.285 ;
     RECT  16.416 38.201 16.434 38.579 ;
     RECT  6.012 38.285 14.886 38.785 ;
     RECT  2.304 37.625 5.094 38.821 ;
     RECT  5.904 38.785 14.886 38.821 ;
     RECT  0.18 38.285 0.198 38.861 ;
     RECT  2.304 38.821 14.886 39.115 ;
     RECT  2.304 39.115 15.39 39.209 ;
     RECT  17.172 39.211 17.19 39.289 ;
     RECT  5.976 39.209 15.39 39.307 ;
     RECT  2.304 39.209 4.914 39.479 ;
     RECT  5.976 39.307 15.966 39.595 ;
     RECT  17.064 39.289 17.19 39.595 ;
     RECT  2.304 39.479 4.842 39.659 ;
     RECT  0.108 39.217 0.162 40.013 ;
     RECT  0.432 40.369 0.486 40.405 ;
     RECT  2.304 39.659 4.806 40.405 ;
     RECT  5.976 39.595 17.19 40.405 ;
     RECT  2.304 40.405 17.19 40.739 ;
     RECT  0.432 40.405 0.558 40.909 ;
     RECT  2.304 40.739 15.462 41.009 ;
     RECT  5.904 41.009 15.462 41.165 ;
     RECT  0.108 40.909 0.558 41.453 ;
     RECT  2.304 41.009 5.166 41.791 ;
     RECT  5.904 41.165 15.426 41.791 ;
     RECT  0.54 41.453 0.558 42.523 ;
     RECT  2.304 41.791 15.426 42.529 ;
     RECT  16.416 40.739 17.19 42.529 ;
     RECT  0.144 42.523 0.558 42.727 ;
     RECT  0.108 42.727 0.558 42.797 ;
     RECT  0.108 42.797 0.126 42.989 ;
     RECT  2.304 42.529 17.19 43.243 ;
     RECT  2.268 43.243 17.19 43.277 ;
     RECT  0.108 43.807 0.126 44.011 ;
     RECT  2.268 43.277 14.958 44.203 ;
     RECT  0.108 44.011 0.342 44.333 ;
     RECT  2.232 44.203 14.958 44.383 ;
     RECT  15.984 43.277 17.19 44.383 ;
     RECT  2.232 44.383 17.19 44.779 ;
     RECT  0.144 44.333 0.342 44.909 ;
     RECT  1.728 44.779 17.19 45.005 ;
     RECT  1.728 45.005 14.886 45.883 ;
     RECT  0.144 45.883 0.162 45.931 ;
     RECT  1.152 45.883 14.886 46.003 ;
     RECT  15.984 45.005 17.19 46.003 ;
     RECT  0.144 45.931 0.342 46.156 ;
     RECT  0.108 46.156 0.342 46.184 ;
     RECT  1.152 46.003 17.19 46.699 ;
     RECT  0.108 46.184 0.126 47.179 ;
     RECT  0.864 46.699 17.19 47.179 ;
     RECT  0.108 47.179 17.19 47.695 ;
     RECT  0.072 47.695 17.19 47.885 ;
     RECT  4.788 47.885 17.19 48.731 ;
     RECT  0.072 47.885 4.014 48.739 ;
     RECT  4.788 48.731 15.39 48.739 ;
     RECT  16.38 48.731 17.19 49.271 ;
     RECT  0.072 48.739 15.39 49.739 ;
     RECT  16.488 49.271 17.19 49.811 ;
     RECT  5.976 49.739 15.39 50.251 ;
     RECT  16.488 49.811 17.154 50.251 ;
     RECT  0.072 49.739 5.202 50.521 ;
     RECT  5.976 50.251 17.154 50.521 ;
     RECT  0.072 50.521 17.154 50.539 ;
     RECT  0.072 50.539 17.19 50.855 ;
     RECT  0.108 50.855 17.19 51.089 ;
     RECT  0.108 51.089 14.814 51.871 ;
     RECT  15.912 51.089 17.19 51.883 ;
     RECT  15.876 51.883 17.19 51.971 ;
     RECT  0.108 51.871 14.922 52.051 ;
     RECT  15.876 51.971 17.154 52.459 ;
     RECT  0.108 52.051 14.994 52.555 ;
     RECT  15.768 52.459 17.154 52.555 ;
     RECT  0.108 52.555 17.154 52.619 ;
     RECT  0.108 52.619 16.506 53.419 ;
     RECT  0.108 53.419 16.542 53.515 ;
     RECT  0.108 53.515 17.118 53.707 ;
     RECT  0.108 53.707 17.19 55.183 ;
     RECT  0.036 55.183 17.19 58.721 ;
     RECT  16.452 58.721 17.19 58.919 ;
     RECT  17.172 58.919 17.19 59.099 ;
     RECT  0.036 58.721 15.678 60.143 ;
     RECT  0.252 60.143 15.678 60.845 ;
     RECT  0.828 60.845 15.678 61.079 ;
     RECT  0.828 61.079 15.066 61.96 ;
     RECT  0.144 61.96 15.066 61.969 ;
     RECT  0.072 61.969 15.066 62.707 ;
     RECT  0.072 62.707 15.138 63.239 ;
     RECT  5.976 63.239 15.138 64.021 ;
     RECT  16.02 63.391 16.038 64.093 ;
     RECT  0.072 63.239 5.166 64.129 ;
     RECT  5.904 64.021 15.138 64.129 ;
     RECT  16.02 64.093 16.434 64.561 ;
     RECT  17.172 64.363 17.19 64.561 ;
     RECT  0.072 64.129 15.138 64.867 ;
     RECT  16.02 64.561 17.19 64.867 ;
     RECT  0.072 64.867 17.19 65.165 ;
     RECT  0.072 65.165 16.614 65.645 ;
     RECT  0.072 65.645 14.994 65.705 ;
     RECT  0.108 65.705 14.994 66.523 ;
     RECT  15.948 65.645 16.614 66.523 ;
     RECT  0.108 66.523 16.614 66.701 ;
     RECT  0.108 66.701 14.994 66.749 ;
     RECT  0.108 66.749 14.958 67.531 ;
     RECT  15.948 66.701 16.614 67.531 ;
     RECT  0.108 67.531 16.614 67.661 ;
     RECT  0.108 67.661 16.578 68.491 ;
     RECT  0.108 68.491 17.19 69.089 ;
     RECT  0.108 69.089 17.154 69.101 ;
     RECT  0.108 69.101 16.506 69.151 ;
     RECT  0.072 69.151 16.506 70.025 ;
     RECT  15.408 70.025 16.506 70.027 ;
     RECT  15.408 70.027 17.19 70.979 ;
     RECT  0.072 70.025 14.67 70.987 ;
     RECT  15.948 70.979 17.19 71.249 ;
     RECT  0.072 70.987 14.85 71.375 ;
     RECT  15.984 71.249 17.19 71.693 ;
     RECT  0.072 71.375 14.778 72.139 ;
     RECT  0.072 72.139 14.85 72.523 ;
     RECT  16.488 71.693 17.19 72.869 ;
     RECT  16.488 72.869 17.154 72.907 ;
     RECT  0.072 72.523 15.39 73.031 ;
     RECT  16.452 72.907 17.154 73.291 ;
     RECT  15.912 73.291 17.154 73.675 ;
     RECT  0.072 73.031 14.778 73.771 ;
     RECT  15.912 73.675 17.19 73.771 ;
     RECT  0.072 73.771 17.19 74.381 ;
     RECT  0.072 74.381 17.154 75.533 ;
     RECT  0.108 75.533 17.154 76.739 ;
     RECT  0.108 76.739 16.542 77.189 ;
     RECT  0.108 77.189 16.254 78.556 ;
     RECT  0.036 78.556 16.254 79.619 ;
     RECT  0.864 79.619 16.254 79.709 ;
     RECT  0.864 79.709 8.097 80.123 ;
     RECT  8.82 79.709 16.254 80.159 ;
     RECT  0.864 80.123 1.458 81.095 ;
     RECT  8.82 80.159 9.774 81.211 ;
     RECT  10.548 80.159 16.254 81.211 ;
     RECT  2.34 80.123 8.097 81.301 ;
     RECT  8.82 81.211 16.254 81.301 ;
     RECT  0.864 81.095 0.882 81.365 ;
     RECT  0.036 79.619 0.054 81.635 ;
     RECT  2.34 81.301 16.254 81.671 ;
     RECT  2.34 81.671 15.678 81.869 ;
     RECT  2.34 81.869 15.174 82.139 ;
     RECT  2.34 82.139 14.238 82.175 ;
     RECT  14.976 82.139 15.174 82.211 ;
     RECT  15.156 82.211 15.174 82.319 ;
     RECT  2.376 82.175 14.238 83.641 ;
     RECT  2.376 83.641 14.67 83.759 ;
     RECT  10.224 83.759 14.454 84.299 ;
     RECT  2.376 83.759 9.378 84.569 ;
     RECT  2.376 84.569 8.73 84.605 ;
     RECT  10.224 84.299 14.238 84.649 ;
     RECT  2.376 84.605 6.39 84.875 ;
     RECT  7.272 84.605 8.73 84.875 ;
     RECT  5.724 84.875 6.39 85.145 ;
     RECT  2.376 84.875 4.806 85.289 ;
     RECT  9.828 84.649 14.238 85.351 ;
     RECT  7.308 84.875 8.73 85.379 ;
     RECT  4.356 85.289 4.806 85.415 ;
     RECT  6.012 85.145 6.39 85.415 ;
     RECT  7.308 85.379 8.406 85.415 ;
     RECT  9.792 85.351 14.238 85.483 ;
     RECT  2.376 85.289 3.546 85.523 ;
     RECT  7.416 85.415 8.406 85.649 ;
     RECT  6.264 85.415 6.282 85.685 ;
     RECT  9.18 85.483 14.238 85.793 ;
     RECT  9.18 85.793 9.414 85.919 ;
     RECT  10.224 85.793 10.854 85.919 ;
     RECT  11.592 85.793 14.238 85.919 ;
     RECT  14.976 85.801 14.994 85.919 ;
     RECT  3.456 85.523 3.546 85.955 ;
     RECT  7.416 85.649 8.097 85.955 ;
     RECT  10.296 85.919 10.674 85.955 ;
     RECT  11.88 85.919 14.238 85.991 ;
     RECT  10.656 85.955 10.674 86.063 ;
     RECT  7.452 85.955 8.097 86.225 ;
     RECT  11.88 85.991 14.166 87.151 ;
     RECT  11.88 87.151 14.238 87.211 ;
     RECT  11.16 87.211 14.238 87.241 ;
     RECT  2.376 85.523 2.697 87.305 ;
     RECT  3.528 85.955 3.546 87.305 ;
     RECT  4.356 85.415 4.734 87.305 ;
     RECT  2.415 87.305 2.697 87.349 ;
     RECT  6.84 87.349 6.858 87.385 ;
     RECT  7.815 86.225 8.097 87.385 ;
     RECT  4.536 87.305 4.554 87.413 ;
     RECT  2.415 87.349 2.826 87.449 ;
     RECT  11.16 87.241 14.922 87.449 ;
     RECT  11.16 87.449 13.986 87.539 ;
     RECT  3.744 87.421 3.762 87.575 ;
     RECT  8.928 87.313 8.946 87.575 ;
     RECT  11.16 87.539 11.178 87.575 ;
     RECT  6.84 87.385 8.097 87.583 ;
     RECT  6.84 87.583 8.154 87.611 ;
     RECT  11.016 87.595 11.034 87.647 ;
     RECT  6.84 87.611 6.858 87.683 ;
     RECT  11.988 87.539 13.986 87.683 ;
     RECT  11.988 87.683 12.294 87.809 ;
     RECT  13.104 87.683 13.986 87.809 ;
     RECT  14.904 87.449 14.922 87.809 ;
     RECT  7.815 87.611 8.154 87.845 ;
     RECT  12.132 87.809 12.15 87.845 ;
     RECT  13.215 87.809 13.806 87.845 ;
     RECT  2.415 87.449 2.697 94.787 ;
     RECT  7.815 87.845 8.097 94.787 ;
     RECT  13.215 87.845 13.497 94.787 ;
     RECT  2.415 94.787 2.505 95.057 ;
     RECT  7.815 94.787 7.905 95.057 ;
     RECT  13.215 94.787 13.305 95.057 ;
    LAYER M4 ;
     RECT  0.06 61.968 0.173 74.184 ;
     RECT  0.173 62.064 0.209 74.184 ;
     RECT  0.06 20.496 0.241 58.056 ;
     RECT  0.241 20.496 0.353 58.152 ;
     RECT  0.241 18.816 0.497 18.84 ;
     RECT  0.353 20.496 1.957 58.008 ;
     RECT  1.957 20.064 2.293 58.008 ;
     RECT  1.957 79.248 2.293 79.272 ;
     RECT  2.329 76.944 2.365 76.968 ;
     RECT  2.293 16.656 2.408 16.68 ;
     RECT  2.293 18.096 2.408 18.12 ;
     RECT  2.293 19.872 2.408 58.008 ;
     RECT  0.209 62.064 2.408 74.088 ;
     RECT  2.221 75.696 2.408 75.72 ;
     RECT  2.365 76.944 2.408 77.112 ;
     RECT  2.293 78.912 2.408 79.272 ;
     RECT  2.408 2.148 2.512 95.052 ;
     RECT  2.512 2.418 2.704 94.782 ;
     RECT  2.704 20.592 2.765 42.744 ;
     RECT  2.704 51.024 2.765 52.584 ;
     RECT  2.765 20.592 2.819 39.912 ;
     RECT  2.704 48.384 2.819 49.56 ;
     RECT  2.819 20.688 2.837 39.912 ;
     RECT  2.837 24.624 2.867 39.912 ;
     RECT  2.867 26.64 2.873 39.912 ;
     RECT  2.765 40.896 2.873 42.744 ;
     RECT  2.873 26.64 2.909 31.896 ;
     RECT  2.704 13.056 2.915 13.08 ;
     RECT  2.704 64.992 2.917 66.6 ;
     RECT  2.867 24.624 2.963 25.32 ;
     RECT  2.704 16.32 3.017 18.936 ;
     RECT  2.837 20.688 3.017 23.544 ;
     RECT  2.873 40.896 3.017 41.544 ;
     RECT  2.873 42.528 3.017 42.744 ;
     RECT  2.704 43.824 3.053 45.624 ;
     RECT  2.704 76.176 3.053 80.328 ;
     RECT  2.909 26.784 3.125 31.896 ;
     RECT  3.125 26.784 3.197 31.272 ;
     RECT  2.873 33.072 3.197 39.768 ;
     RECT  3.197 33.6 3.251 39.768 ;
     RECT  2.704 56.928 3.269 59.832 ;
     RECT  3.017 20.736 3.305 23.544 ;
     RECT  2.819 48.912 3.305 49.512 ;
     RECT  2.704 11.52 3.341 11.544 ;
     RECT  3.251 34.896 3.377 39.768 ;
     RECT  3.305 21.984 3.413 23.544 ;
     RECT  2.704 67.68 3.413 69.288 ;
     RECT  3.413 68.976 3.449 69.288 ;
     RECT  2.704 70.368 3.449 75.144 ;
     RECT  3.017 16.368 3.457 18.936 ;
     RECT  3.413 22.224 3.485 23.544 ;
     RECT  3.053 43.872 3.491 45.624 ;
     RECT  3.491 44.064 3.529 45.624 ;
     RECT  3.377 35.616 3.557 39.768 ;
     RECT  3.269 59.616 3.593 59.832 ;
     RECT  3.197 28.464 3.683 31.272 ;
     RECT  3.557 37.68 3.693 39.768 ;
     RECT  3.017 42.672 3.697 42.744 ;
     RECT  2.704 47.376 3.697 47.4 ;
     RECT  3.593 59.712 3.701 59.832 ;
     RECT  3.693 37.68 3.737 37.8 ;
     RECT  2.765 51.024 3.737 52.488 ;
     RECT  3.413 67.68 3.737 67.896 ;
     RECT  3.053 76.656 3.737 80.328 ;
     RECT  3.737 67.68 3.773 67.848 ;
     RECT  2.704 53.568 3.805 55.368 ;
     RECT  3.269 56.928 3.805 58.44 ;
     RECT  3.737 51.216 3.841 52.488 ;
     RECT  3.805 53.568 3.841 58.44 ;
     RECT  3.697 47.376 3.913 47.688 ;
     RECT  3.701 59.808 3.913 59.832 ;
     RECT  2.704 60.96 3.913 60.984 ;
     RECT  3.841 51.216 3.917 58.44 ;
     RECT  3.737 76.896 3.917 80.328 ;
     RECT  2.704 62.784 3.949 63.816 ;
     RECT  3.917 53.088 3.953 58.44 ;
     RECT  3.449 70.368 3.971 75 ;
     RECT  2.917 65.712 3.973 66.6 ;
     RECT  3.949 62.448 3.98 63.816 ;
     RECT  3.305 48.912 3.985 49.464 ;
     RECT  3.449 68.976 3.989 69 ;
     RECT  3.917 76.896 3.989 79.704 ;
     RECT  3.98 62.4 4.019 63.816 ;
     RECT  3.973 65.376 4.019 66.6 ;
     RECT  3.989 77.904 4.061 79.704 ;
     RECT  3.913 59.808 4.067 60.984 ;
     RECT  3.913 46.944 4.069 47.688 ;
     RECT  3.017 41.04 4.093 41.544 ;
     RECT  3.697 42.672 4.093 42.888 ;
     RECT  3.971 70.368 4.097 74.952 ;
     RECT  2.963 24.672 4.129 25.32 ;
     RECT  4.097 73.152 4.133 74.952 ;
     RECT  3.953 53.328 4.163 58.44 ;
     RECT  3.251 33.6 4.165 33.624 ;
     RECT  3.529 44.064 4.169 44.952 ;
     RECT  4.061 77.904 4.169 79.512 ;
     RECT  4.169 78 4.205 79.512 ;
     RECT  3.305 20.736 4.273 21 ;
     RECT  3.989 76.896 4.277 76.92 ;
     RECT  3.457 18.816 4.381 18.936 ;
     RECT  3.917 51.216 4.403 52.056 ;
     RECT  4.273 20.736 4.412 21.096 ;
     RECT  3.985 48.768 4.417 49.464 ;
     RECT  4.069 1.728 4.421 1.752 ;
     RECT  4.412 20.736 4.453 21.192 ;
     RECT  3.485 22.224 4.453 23.352 ;
     RECT  4.381 18.816 4.489 19.608 ;
     RECT  4.453 20.736 4.489 23.352 ;
     RECT  4.129 24.624 4.489 25.32 ;
     RECT  4.163 53.328 4.493 56.136 ;
     RECT  4.165 33.12 4.529 33.624 ;
     RECT  3.737 37.68 4.529 37.704 ;
     RECT  4.067 59.808 4.529 60.408 ;
     RECT  2.704 81.648 4.529 82.152 ;
     RECT  3.197 26.976 4.556 27.336 ;
     RECT  4.069 46.848 4.561 47.688 ;
     RECT  4.417 48.768 4.561 49.944 ;
     RECT  4.093 41.04 4.595 42.888 ;
     RECT  4.561 46.848 4.595 49.944 ;
     RECT  4.097 70.368 4.601 71.832 ;
     RECT  4.019 66.528 4.633 66.6 ;
     RECT  4.403 51.216 4.637 51.432 ;
     RECT  4.529 81.648 4.637 81.672 ;
     RECT  4.556 26.784 4.643 27.336 ;
     RECT  3.683 28.464 4.741 28.968 ;
     RECT  3.693 38.784 4.745 39.768 ;
     RECT  4.169 44.928 4.777 44.952 ;
     RECT  4.601 70.368 4.781 70.392 ;
     RECT  4.163 57.504 4.813 58.44 ;
     RECT  4.745 38.784 4.853 39.624 ;
     RECT  4.601 71.808 4.853 71.832 ;
     RECT  4.019 62.4 4.921 63.72 ;
     RECT  4.273 83.136 4.921 83.16 ;
     RECT  4.489 18.816 4.925 25.32 ;
     RECT  4.925 20.976 4.931 25.32 ;
     RECT  3.683 30.384 4.957 31.272 ;
     RECT  4.595 41.04 4.961 41.064 ;
     RECT  4.643 26.784 4.993 27.096 ;
     RECT  3.557 35.616 4.993 35.976 ;
     RECT  4.931 22.272 4.997 23.352 ;
     RECT  4.921 61.92 5.027 63.72 ;
     RECT  3.457 16.368 5.029 17.64 ;
     RECT  4.529 33.12 5.029 33.288 ;
     RECT  4.741 28.464 5.033 29.304 ;
     RECT  4.637 51.216 5.033 51.24 ;
     RECT  4.993 35.184 5.065 35.976 ;
     RECT  4.019 65.376 5.065 65.4 ;
     RECT  5.033 29.28 5.077 29.304 ;
     RECT  4.957 30.384 5.077 31.608 ;
     RECT  5.065 35.136 5.077 35.976 ;
     RECT  4.931 25.152 5.105 25.32 ;
     RECT  4.669 37.056 5.123 37.464 ;
     RECT  5.065 65.28 5.137 65.4 ;
     RECT  4.133 73.488 5.137 74.952 ;
     RECT  4.777 44.928 5.141 45.336 ;
     RECT  5.027 61.92 5.141 62.808 ;
     RECT  5.057 68.976 5.141 69 ;
     RECT  5.029 33.072 5.173 33.288 ;
     RECT  4.925 18.816 5.213 19.608 ;
     RECT  4.931 20.976 5.213 21 ;
     RECT  4.529 60.384 5.213 60.408 ;
     RECT  5.077 29.28 5.219 31.608 ;
     RECT  4.633 66.528 5.249 66.744 ;
     RECT  5.173 32.736 5.26 33.288 ;
     RECT  4.205 78.24 5.281 79.512 ;
     RECT  4.493 53.328 5.285 56.088 ;
     RECT  5.26 33.024 5.293 33.288 ;
     RECT  5.141 61.92 5.317 62.424 ;
     RECT  5.137 64.176 5.317 65.4 ;
     RECT  5.137 73.488 5.317 75.192 ;
     RECT  5.317 73.488 5.353 75.768 ;
     RECT  5.317 61.536 5.357 62.424 ;
     RECT  5.249 66.672 5.357 66.744 ;
     RECT  3.773 67.824 5.357 67.848 ;
     RECT  5.219 29.28 5.393 30.792 ;
     RECT  5.285 53.568 5.393 56.088 ;
     RECT  4.595 46.848 5.429 49.464 ;
     RECT  5.029 15.888 5.501 17.64 ;
     RECT  5.281 77.712 5.533 79.512 ;
     RECT  5.393 54.144 5.537 56.088 ;
     RECT  5.537 56.064 5.573 56.088 ;
     RECT  5.353 73.488 5.573 76.392 ;
     RECT  5.533 77.712 5.603 80.424 ;
     RECT  4.813 57.504 5.609 59.352 ;
     RECT  5.123 37.44 5.645 37.464 ;
     RECT  5.281 44.544 5.669 44.568 ;
     RECT  5.603 78.528 5.699 80.424 ;
     RECT  4.853 38.784 5.701 39.096 ;
     RECT  5.669 43.872 5.747 44.568 ;
     RECT  5.605 45.552 5.747 45.672 ;
     RECT  4.993 13.104 5.749 13.128 ;
     RECT  2.704 14.304 5.749 14.808 ;
     RECT  5.293 33.072 5.749 33.288 ;
     RECT  5.077 34.56 5.749 36.072 ;
     RECT  5.573 76.368 5.749 76.392 ;
     RECT  5.501 15.888 5.753 15.912 ;
     RECT  5.501 17.232 5.753 17.64 ;
     RECT  5.747 43.872 5.753 43.896 ;
     RECT  5.537 54.144 5.753 55.08 ;
     RECT  5.749 13.104 5.785 14.808 ;
     RECT  4.993 26.592 5.789 27.096 ;
     RECT  5.749 76.368 5.821 76.488 ;
     RECT  5.785 13.104 5.825 15.72 ;
     RECT  5.753 17.616 5.825 17.64 ;
     RECT  4.997 23.328 5.825 23.352 ;
     RECT  5.699 78.528 5.825 79.752 ;
     RECT  5.573 73.488 5.929 75.192 ;
     RECT  5.825 13.536 5.933 15.72 ;
     RECT  5.933 13.536 5.969 14.328 ;
     RECT  5.749 33.072 6.005 36.072 ;
     RECT  4.595 42.192 6.005 42.744 ;
     RECT  5.857 40.416 6.145 40.44 ;
     RECT  4.921 83.04 6.145 83.16 ;
     RECT  5.357 61.536 6.149 62.328 ;
     RECT  5.213 18.816 6.181 18.84 ;
     RECT  6.005 42.192 6.181 42.456 ;
     RECT  4.997 22.272 6.185 22.296 ;
     RECT  5.965 50.784 6.217 50.808 ;
     RECT  6.217 50.784 6.253 50.856 ;
     RECT  5.701 38.064 6.275 39.096 ;
     RECT  6.005 33.6 6.293 36.072 ;
     RECT  5.393 30.384 6.329 30.792 ;
     RECT  6.253 50.4 6.329 50.856 ;
     RECT  6.275 38.832 6.361 39.096 ;
     RECT  5.317 64.176 6.365 65.496 ;
     RECT  5.929 73.296 6.365 75.192 ;
     RECT  5.105 25.248 6.373 25.32 ;
     RECT  6.329 50.4 6.401 50.808 ;
     RECT  6.365 64.176 6.401 65.304 ;
     RECT  5.789 26.784 6.419 27.096 ;
     RECT  5.609 57.504 6.433 57.624 ;
     RECT  6.433 57.12 6.476 57.624 ;
     RECT  6.181 18 6.541 18.84 ;
     RECT  5.747 45.552 6.541 45.576 ;
     RECT  6.149 62.304 6.545 62.328 ;
     RECT  6.109 84.288 6.545 84.312 ;
     RECT  6.476 57.024 6.563 57.624 ;
     RECT  6.401 64.176 6.565 64.92 ;
     RECT  6.145 40.416 6.613 40.632 ;
     RECT  6.181 42.144 6.613 42.456 ;
     RECT  5.357 66.72 6.613 66.744 ;
     RECT  5.821 76.368 6.649 76.584 ;
     RECT  6.541 45.456 6.653 45.576 ;
     RECT  5.753 54.24 6.653 55.08 ;
     RECT  6.365 73.296 6.653 74.952 ;
     RECT  6.613 66.48 6.685 66.744 ;
     RECT  6.253 28.272 6.721 28.296 ;
     RECT  5.393 29.28 6.721 29.304 ;
     RECT  6.361 38.832 6.725 39.24 ;
     RECT  6.649 75.984 6.757 76.968 ;
     RECT  5.825 78.528 6.757 78.936 ;
     RECT  6.721 28.272 6.829 29.304 ;
     RECT  6.329 30.384 6.829 30.408 ;
     RECT  6.361 68.304 6.829 68.328 ;
     RECT  6.253 69.504 6.829 69.528 ;
     RECT  6.505 21.696 6.833 21.72 ;
     RECT  5.609 58.704 6.833 59.352 ;
     RECT  5.933 15.36 6.853 15.72 ;
     RECT  6.853 15.36 6.901 15.864 ;
     RECT  6.541 18 6.901 19.368 ;
     RECT  6.86 20.496 6.901 20.52 ;
     RECT  6.373 24.768 6.973 25.32 ;
     RECT  6.613 40.416 6.973 42.456 ;
     RECT  6.563 57.12 6.973 57.624 ;
     RECT  6.833 58.704 6.973 59.256 ;
     RECT  6.419 26.976 7.009 27.096 ;
     RECT  6.565 63.792 7.009 64.92 ;
     RECT  5.429 46.848 7.045 48.936 ;
     RECT  6.401 50.4 7.045 50.424 ;
     RECT  6.793 51.792 7.1 51.816 ;
     RECT  6.653 54.24 7.1 54.888 ;
     RECT  6.253 22.704 7.117 22.824 ;
     RECT  6.757 75.984 7.225 78.936 ;
     RECT  6.721 31.872 7.261 31.896 ;
     RECT  6.653 45.552 7.261 45.576 ;
     RECT  7.045 46.848 7.261 50.424 ;
     RECT  7.117 22.704 7.333 22.968 ;
     RECT  6.973 40.416 7.333 42.504 ;
     RECT  6.293 34.128 7.369 36.072 ;
     RECT  6.829 68.304 7.477 69.528 ;
     RECT  7.189 60.384 7.573 60.408 ;
     RECT  6.973 57.12 7.585 59.256 ;
     RECT  7.225 75.984 7.621 79.224 ;
     RECT  6.829 28.272 7.669 30.408 ;
     RECT  7.009 63.072 7.669 64.92 ;
     RECT  6.685 66.336 7.669 66.744 ;
     RECT  7.477 67.824 7.669 69.528 ;
     RECT  6.577 71.232 7.669 71.256 ;
     RECT  7.333 22.704 7.693 23.352 ;
     RECT  6.973 24.672 7.693 25.32 ;
     RECT  7.009 26.976 7.693 27.144 ;
     RECT  7.117 81.696 7.693 81.72 ;
     RECT  5.969 13.824 7.808 14.328 ;
     RECT  6.901 15.36 7.808 16.44 ;
     RECT  6.901 18 7.808 21.384 ;
     RECT  7.693 22.704 7.808 25.32 ;
     RECT  7.693 26.544 7.808 27.144 ;
     RECT  7.669 28.272 7.808 30.456 ;
     RECT  7.261 31.872 7.808 32.28 ;
     RECT  7.369 33.552 7.808 36.072 ;
     RECT  6.685 37.824 7.808 37.848 ;
     RECT  6.725 39.216 7.808 39.24 ;
     RECT  7.333 40.416 7.808 43.08 ;
     RECT  7.58 44.4 7.808 44.424 ;
     RECT  7.261 45.552 7.808 50.424 ;
     RECT  7.1 51.792 7.808 51.912 ;
     RECT  7.1 53.472 7.808 54.888 ;
     RECT  7.585 56.352 7.808 59.256 ;
     RECT  7.573 60.384 7.808 60.888 ;
     RECT  7.669 62.544 7.808 64.92 ;
     RECT  7.669 66.336 7.808 69.528 ;
     RECT  7.669 71.232 7.808 71.928 ;
     RECT  6.653 73.296 7.808 74.04 ;
     RECT  7.621 75.984 7.808 79.32 ;
     RECT  7.693 81.6 7.808 81.72 ;
     RECT  6.145 83.04 7.808 83.304 ;
     RECT  7.261 84.672 7.808 84.696 ;
     RECT  7.808 2.148 7.912 95.052 ;
     RECT  7.912 2.418 8.104 94.782 ;
     RECT  8.104 20.16 8.201 20.184 ;
     RECT  8.104 46.512 8.201 52.104 ;
     RECT  8.104 79.2 8.243 79.752 ;
     RECT  8.104 26.544 8.281 28.296 ;
     RECT  8.201 46.56 8.281 52.104 ;
     RECT  8.104 13.824 8.417 16.392 ;
     RECT  8.104 53.136 8.417 55.08 ;
     RECT  8.417 54.624 8.435 55.08 ;
     RECT  8.104 83.232 8.453 84.696 ;
     RECT  8.104 56.352 8.476 58.68 ;
     RECT  8.104 73.296 8.489 73.512 ;
     RECT  8.489 73.392 8.524 73.512 ;
     RECT  8.104 70.272 8.569 71.928 ;
     RECT  8.104 17.664 8.597 18.696 ;
     RECT  8.104 24.192 8.597 24.792 ;
     RECT  8.453 83.232 8.597 83.784 ;
     RECT  8.104 21.264 8.627 23.016 ;
     RECT  8.597 17.664 8.633 17.688 ;
     RECT  8.417 13.824 8.669 14.904 ;
     RECT  8.281 28.272 8.705 28.296 ;
     RECT  8.104 68.976 8.705 69 ;
     RECT  8.281 26.544 8.741 26.904 ;
     RECT  8.627 22.752 8.813 23.016 ;
     RECT  8.104 29.28 8.813 35.88 ;
     RECT  8.476 58.08 8.813 58.68 ;
     RECT  8.243 79.2 8.813 79.32 ;
     RECT  8.104 9.744 8.819 9.768 ;
     RECT  8.104 11.664 8.819 11.688 ;
     RECT  8.435 54.624 8.819 54.888 ;
     RECT  8.104 7.968 8.821 7.992 ;
     RECT  8.104 81.408 8.849 81.624 ;
     RECT  8.104 37.824 8.956 41.544 ;
     RECT  8.741 26.64 8.957 26.904 ;
     RECT  8.813 22.848 9.029 23.016 ;
     RECT  8.956 38.736 9.029 41.544 ;
     RECT  8.104 62.256 9.059 63.816 ;
     RECT  8.813 58.08 9.093 58.632 ;
     RECT  8.597 18.672 9.097 18.696 ;
     RECT  8.104 42.624 9.097 44.472 ;
     RECT  8.849 81.6 9.101 81.624 ;
     RECT  8.524 73.44 9.137 73.512 ;
     RECT  9.059 63.264 9.155 63.816 ;
     RECT  8.104 60.048 9.164 61.272 ;
     RECT  8.569 70.272 9.173 70.632 ;
     RECT  8.417 16.368 9.205 16.392 ;
     RECT  8.104 74.928 9.205 74.952 ;
     RECT  8.417 53.136 9.241 53.64 ;
     RECT  9.109 64.944 9.241 64.968 ;
     RECT  8.569 71.904 9.241 71.928 ;
     RECT  9.155 63.264 9.251 63.288 ;
     RECT  8.669 13.824 9.269 14.376 ;
     RECT  9.097 42.576 9.277 44.472 ;
     RECT  8.281 46.56 9.277 51.72 ;
     RECT  8.104 77.712 9.277 77.832 ;
     RECT  8.597 24.432 9.313 24.792 ;
     RECT  9.205 74.928 9.313 75 ;
     RECT  9.269 13.632 9.347 14.376 ;
     RECT  9.347 13.632 9.353 13.944 ;
     RECT  9.353 13.824 9.389 13.944 ;
     RECT  9.205 16.368 9.389 17.304 ;
     RECT  8.627 21.264 9.421 21.624 ;
     RECT  9.277 42.528 9.421 44.472 ;
     RECT  8.813 79.296 9.452 79.32 ;
     RECT  9.389 13.824 9.461 13.896 ;
     RECT  8.476 56.352 9.493 56.376 ;
     RECT  8.104 76.032 9.493 76.056 ;
     RECT  9.277 77.088 9.493 77.832 ;
     RECT  8.104 67.392 9.529 67.848 ;
     RECT  9.452 79.296 9.539 79.944 ;
     RECT  8.957 26.736 9.565 26.904 ;
     RECT  9.421 42.528 9.565 44.52 ;
     RECT  9.565 42.528 9.589 45.048 ;
     RECT  9.029 40.416 9.601 41.544 ;
     RECT  9.589 42.528 9.601 45.576 ;
     RECT  9.277 46.56 9.601 51.912 ;
     RECT  8.597 83.472 9.601 83.688 ;
     RECT  9.313 24.432 9.637 25.128 ;
     RECT  9.313 74.592 9.673 75 ;
     RECT  9.241 53.04 9.709 53.64 ;
     RECT  8.819 54.624 9.709 54.648 ;
     RECT  9.241 64.944 9.709 65.496 ;
     RECT  9.097 18.672 9.733 19.128 ;
     RECT  9.241 71.904 9.733 72.312 ;
     RECT  9.733 18.576 9.745 19.128 ;
     RECT  9.164 60.048 9.749 62.088 ;
     RECT  9.733 71.808 9.779 72.936 ;
     RECT  9.673 74.064 9.779 75 ;
     RECT  9.709 64.944 9.809 65.88 ;
     RECT  9.529 66.864 9.809 67.848 ;
     RECT  9.779 74.064 9.821 74.616 ;
     RECT  9.097 9.936 9.853 10.248 ;
     RECT  9.493 76.032 9.853 77.832 ;
     RECT  9.821 74.112 9.857 74.616 ;
     RECT  9.853 9.792 9.893 10.248 ;
     RECT  9.389 16.368 9.925 16.488 ;
     RECT  9.173 70.512 9.925 70.632 ;
     RECT  9.539 79.296 9.929 79.752 ;
     RECT  9.925 70.512 9.961 70.68 ;
     RECT  9.779 71.808 9.961 71.928 ;
     RECT  9.749 60.048 9.965 60.312 ;
     RECT  9.745 18.192 9.969 19.128 ;
     RECT  9.421 20.544 9.969 21.624 ;
     RECT  9.637 23.808 9.997 25.128 ;
     RECT  9.929 79.296 10.001 79.32 ;
     RECT  9.997 23.808 10.019 25.224 ;
     RECT  9.997 69.072 10.033 69.096 ;
     RECT  9.969 18.192 10.067 21.624 ;
     RECT  10.067 19.632 10.069 21.624 ;
     RECT  9.973 22.656 10.069 22.68 ;
     RECT  10.019 24.192 10.069 25.224 ;
     RECT  9.565 26.736 10.069 28.104 ;
     RECT  9.601 40.416 10.069 51.912 ;
     RECT  9.709 53.04 10.069 54.648 ;
     RECT  9.133 37.536 10.105 37.56 ;
     RECT  9.779 72.912 10.181 72.936 ;
     RECT  9.809 64.944 10.213 67.848 ;
     RECT  10.033 69.072 10.213 69.528 ;
     RECT  10.069 40.416 10.217 54.648 ;
     RECT  10.105 37.296 10.249 37.56 ;
     RECT  9.029 38.736 10.249 39.288 ;
     RECT  10.067 18.192 10.289 18.216 ;
     RECT  9.853 75.936 10.289 77.832 ;
     RECT  9.093 58.128 10.309 58.632 ;
     RECT  9.493 56.352 10.321 57 ;
     RECT  10.309 58.128 10.321 59.064 ;
     RECT  9.961 70.512 10.325 71.928 ;
     RECT  9.925 15.648 10.355 16.488 ;
     RECT  10.249 37.296 10.357 39.288 ;
     RECT  10.217 40.416 10.357 43.128 ;
     RECT  10.321 56.352 10.396 59.064 ;
     RECT  10.357 37.296 10.403 43.128 ;
     RECT  10.213 64.944 10.429 69.528 ;
     RECT  10.325 70.512 10.429 71.832 ;
     RECT  10.403 38.736 10.444 43.128 ;
     RECT  10.403 37.296 10.465 37.56 ;
     RECT  9.601 83.376 10.465 83.688 ;
     RECT  10.429 64.944 10.505 71.832 ;
     RECT  10.289 75.936 10.505 76.296 ;
     RECT  10.217 44.304 10.537 54.648 ;
     RECT  10.537 44.304 10.645 55.272 ;
     RECT  10.396 56.352 10.645 58.152 ;
     RECT  9.277 85.488 10.645 85.512 ;
     RECT  10.505 64.944 10.649 71.784 ;
     RECT  9.749 61.776 10.717 62.088 ;
     RECT  10.069 19.632 10.753 22.68 ;
     RECT  10.069 24.192 10.789 28.104 ;
     RECT  8.813 29.28 10.789 31.944 ;
     RECT  10.309 12.768 10.796 12.792 ;
     RECT  9.461 13.824 10.796 13.848 ;
     RECT  10.789 24.192 10.825 31.944 ;
     RECT  8.813 32.928 10.825 35.88 ;
     RECT  10.649 64.944 10.825 65.016 ;
     RECT  10.796 12.768 10.837 13.848 ;
     RECT  10.355 15.648 10.837 16.008 ;
     RECT  9.893 9.792 10.861 9.96 ;
     RECT  10.837 12.768 10.883 16.008 ;
     RECT  10.645 85.488 10.883 86.04 ;
     RECT  10.861 9.168 10.892 9.96 ;
     RECT  10.649 66 10.901 71.784 ;
     RECT  10.883 12.768 10.909 12.888 ;
     RECT  10.837 11.376 10.937 11.4 ;
     RECT  10.645 44.304 10.973 58.152 ;
     RECT  10.892 9.168 10.979 10.344 ;
     RECT  10.837 87.216 11.005 87.24 ;
     RECT  10.465 83.376 11.036 83.736 ;
     RECT  10.717 61.68 11.041 62.088 ;
     RECT  10.825 63.12 11.041 63.144 ;
     RECT  10.973 48.384 11.045 58.152 ;
     RECT  10.973 44.304 11.081 47.304 ;
     RECT  11.036 83.376 11.084 84.36 ;
     RECT  9.965 60.288 11.113 60.312 ;
     RECT  10.825 64.464 11.113 65.016 ;
     RECT  11.041 81.6 11.113 81.624 ;
     RECT  11.084 82.608 11.113 84.36 ;
     RECT  11.005 10.8 11.117 10.824 ;
     RECT  10.883 15.984 11.117 16.008 ;
     RECT  11.113 81.6 11.123 84.36 ;
     RECT  10.825 24.192 11.125 35.88 ;
     RECT  11.123 81.6 11.171 83.736 ;
     RECT  11.113 60.288 11.185 60.696 ;
     RECT  10.753 19.632 11.189 22.728 ;
     RECT  10.901 66 11.189 68.232 ;
     RECT  11.125 23.856 11.221 35.88 ;
     RECT  10.465 37.056 11.221 37.56 ;
     RECT  11.041 61.68 11.221 63.144 ;
     RECT  11.113 64.176 11.221 65.016 ;
     RECT  11.171 81.6 11.221 82.056 ;
     RECT  10.979 9.168 11.225 9.816 ;
     RECT  11.221 81.312 11.228 82.056 ;
     RECT  11.185 60.192 11.257 60.696 ;
     RECT  11.221 61.68 11.257 65.016 ;
     RECT  10.505 75.936 11.257 76.104 ;
     RECT  10.825 17.184 11.293 17.208 ;
     RECT  9.857 74.112 11.297 74.136 ;
     RECT  11.228 80.448 11.315 82.056 ;
     RECT  11.257 75.792 11.329 76.104 ;
     RECT  11.045 54.288 11.363 58.152 ;
     RECT  10.465 7.632 11.365 7.656 ;
     RECT  11.221 23.856 11.365 37.56 ;
     RECT  10.444 38.736 11.365 38.76 ;
     RECT  10.444 40.416 11.365 43.128 ;
     RECT  11.257 60.192 11.369 65.016 ;
     RECT  11.365 7.632 11.411 8.184 ;
     RECT  11.225 9.6 11.411 9.816 ;
     RECT  11.363 54.288 11.441 56.76 ;
     RECT  11.171 83.376 11.441 83.736 ;
     RECT  11.369 60.528 11.459 65.016 ;
     RECT  11.189 21.648 11.473 22.728 ;
     RECT  11.365 23.856 11.473 38.76 ;
     RECT  11.441 83.712 11.513 83.736 ;
     RECT  10.289 77.76 11.545 77.832 ;
     RECT  11.189 19.968 11.585 20.616 ;
     RECT  11.441 54.384 11.621 56.76 ;
     RECT  11.365 40.416 11.653 43.32 ;
     RECT  11.621 54.384 11.657 56.616 ;
     RECT  11.473 21.648 11.689 38.76 ;
     RECT  11.653 39.792 11.689 43.32 ;
     RECT  11.081 44.304 11.693 46.776 ;
     RECT  11.689 21.648 11.725 43.32 ;
     RECT  11.545 77.76 11.761 78.696 ;
     RECT  11.189 66 11.765 66.936 ;
     RECT  11.329 74.496 11.833 76.104 ;
     RECT  11.411 8.16 11.837 8.184 ;
     RECT  11.761 77.76 11.852 78.84 ;
     RECT  10.883 14.208 11.869 14.808 ;
     RECT  11.459 60.576 11.873 65.016 ;
     RECT  11.852 77.76 11.893 78.888 ;
     RECT  11.363 58.128 11.941 58.152 ;
     RECT  10.909 12.768 11.977 12.792 ;
     RECT  11.869 13.92 11.977 14.808 ;
     RECT  11.293 17.184 11.977 17.64 ;
     RECT  11.765 66.096 12.017 66.936 ;
     RECT  11.585 19.968 12.035 19.992 ;
     RECT  11.657 54.384 12.053 55.848 ;
     RECT  11.977 17.184 12.061 18.216 ;
     RECT  11.005 87.216 12.092 87.624 ;
     RECT  10.901 69.36 12.121 71.784 ;
     RECT  12.092 87.216 12.133 87.816 ;
     RECT  11.045 48.384 12.157 53.256 ;
     RECT  11.725 21.648 12.161 43.896 ;
     RECT  12.133 87.12 12.179 87.816 ;
     RECT  12.157 48.384 12.193 53.304 ;
     RECT  11.189 68.112 12.193 68.232 ;
     RECT  11.693 45.024 12.229 46.776 ;
     RECT  12.193 47.856 12.229 53.304 ;
     RECT  12.121 69.36 12.229 72.264 ;
     RECT  12.229 69.36 12.301 72.408 ;
     RECT  11.893 77.76 12.332 79.704 ;
     RECT  11.833 74.496 12.337 76.344 ;
     RECT  11.315 81.312 12.373 82.056 ;
     RECT  11.977 12.768 12.445 14.808 ;
     RECT  12.061 17.184 12.445 18.168 ;
     RECT  11.977 5.088 12.517 5.112 ;
     RECT  11.905 6.288 12.517 6.312 ;
     RECT  12.445 12.768 12.517 15.096 ;
     RECT  12.445 16.656 12.517 18.168 ;
     RECT  12.193 67.824 12.517 68.232 ;
     RECT  12.337 74.4 12.553 76.344 ;
     RECT  12.332 77.712 12.553 79.704 ;
     RECT  12.179 87.12 12.565 87.624 ;
     RECT  12.373 81.168 12.613 82.056 ;
     RECT  12.613 81.168 12.625 82.824 ;
     RECT  12.553 74.4 12.877 79.704 ;
     RECT  12.625 80.928 12.877 82.824 ;
     RECT  12.661 7.392 12.908 7.416 ;
     RECT  12.517 5.088 12.913 6.312 ;
     RECT  12.908 7.392 12.913 8.376 ;
     RECT  12.229 45.024 12.913 53.304 ;
     RECT  12.181 19.92 13.045 19.944 ;
     RECT  12.913 44.88 13.057 53.304 ;
     RECT  12.877 74.4 13.085 82.824 ;
     RECT  13.057 44.88 13.129 53.352 ;
     RECT  12.053 54.624 13.129 55.848 ;
     RECT  12.161 21.744 13.165 43.896 ;
     RECT  13.129 44.88 13.165 55.848 ;
     RECT  12.913 5.088 13.208 8.376 ;
     RECT  11.411 9.6 13.208 9.624 ;
     RECT  12.517 11.376 13.208 15.096 ;
     RECT  12.517 16.128 13.208 18.168 ;
     RECT  13.045 19.536 13.208 19.944 ;
     RECT  13.165 21.744 13.208 55.848 ;
     RECT  11.941 58.128 13.208 58.872 ;
     RECT  11.873 60.576 13.208 63.624 ;
     RECT  11.873 64.896 13.208 65.016 ;
     RECT  12.017 66.096 13.208 66.12 ;
     RECT  12.517 67.824 13.208 68.376 ;
     RECT  12.301 69.36 13.208 72.744 ;
     RECT  13.085 73.728 13.208 82.824 ;
     RECT  12.476 84.192 13.208 84.216 ;
     RECT  10.883 85.488 13.208 85.512 ;
     RECT  12.565 86.928 13.208 87.624 ;
     RECT  13.208 2.148 13.312 95.052 ;
     RECT  13.312 2.418 13.504 94.782 ;
     RECT  13.504 20.88 13.601 33.144 ;
     RECT  13.504 12.24 13.619 12.264 ;
     RECT  13.601 20.88 13.619 32.856 ;
     RECT  13.504 74.688 13.619 76.872 ;
     RECT  13.619 74.784 13.66 76.104 ;
     RECT  13.504 5.472 13.709 5.88 ;
     RECT  13.504 17.088 13.715 17.112 ;
     RECT  13.504 18.768 13.715 19.56 ;
     RECT  13.66 75.216 13.715 76.104 ;
     RECT  13.504 83.088 13.753 83.112 ;
     RECT  13.504 7.392 13.763 8.184 ;
     RECT  13.504 9.456 13.763 9.96 ;
     RECT  13.619 20.928 13.781 32.856 ;
     RECT  13.763 8.16 13.804 8.184 ;
     RECT  13.504 78.624 13.811 78.696 ;
     RECT  13.709 5.472 13.817 5.496 ;
     RECT  13.504 34.368 13.817 55.464 ;
     RECT  13.504 87.12 13.817 87.816 ;
     RECT  13.504 64.896 13.853 66.888 ;
     RECT  13.504 84.768 13.859 86.04 ;
     RECT  13.817 87.12 13.859 87.144 ;
     RECT  13.781 25.488 13.889 32.856 ;
     RECT  13.504 81.168 13.925 82.104 ;
     RECT  13.811 78.624 13.961 78.648 ;
     RECT  13.781 20.928 13.997 24.504 ;
     RECT  13.889 25.488 13.997 32.76 ;
     RECT  13.817 34.368 14.033 50.184 ;
     RECT  13.925 81.168 14.033 81.192 ;
     RECT  13.859 85.344 14.033 86.04 ;
     RECT  14.033 85.344 14.177 85.368 ;
     RECT  13.763 9.936 14.284 9.96 ;
     RECT  13.504 68.064 14.357 68.184 ;
     RECT  13.715 19.536 14.393 19.56 ;
     RECT  13.997 20.928 14.605 24.168 ;
     RECT  13.817 51.792 14.753 55.464 ;
     RECT  13.997 25.488 14.785 25.8 ;
     RECT  14.033 34.368 14.821 38.184 ;
     RECT  13.997 26.784 14.857 32.76 ;
     RECT  14.821 33.744 14.857 38.184 ;
     RECT  13.715 75.216 14.857 75.24 ;
     RECT  14.753 51.888 14.861 55.464 ;
     RECT  13.504 69.168 14.861 73.224 ;
     RECT  13.853 64.944 14.893 66.888 ;
     RECT  14.605 20.688 14.965 24.168 ;
     RECT  14.785 25.296 14.965 25.8 ;
     RECT  14.857 26.784 14.965 38.184 ;
     RECT  14.033 39.504 14.969 50.184 ;
     RECT  14.857 74.928 15.037 75.24 ;
     RECT  15.001 76.464 15.037 76.488 ;
     RECT  15.037 56.976 15.073 57 ;
     RECT  15.037 74.928 15.073 76.488 ;
     RECT  14.861 55.248 15.109 55.464 ;
     RECT  15.073 56.976 15.109 57.192 ;
     RECT  15.073 74.928 15.145 76.584 ;
     RECT  14.965 20.688 15.361 38.184 ;
     RECT  14.969 39.504 15.361 46.632 ;
     RECT  14.861 72.528 15.361 73.224 ;
     RECT  15.145 74.448 15.361 76.584 ;
     RECT  14.357 68.16 15.397 68.184 ;
     RECT  14.861 69.168 15.397 71.496 ;
     RECT  15.361 20.688 15.649 46.632 ;
     RECT  15.649 20.304 15.721 46.632 ;
     RECT  15.361 72.528 15.757 76.584 ;
     RECT  14.969 47.76 15.829 50.184 ;
     RECT  14.861 51.888 15.829 53.928 ;
     RECT  15.829 47.76 15.901 50.664 ;
     RECT  15.829 51.888 15.901 54.12 ;
     RECT  15.109 55.248 15.901 57.192 ;
     RECT  15.721 20.208 15.937 46.632 ;
     RECT  15.901 47.76 15.937 57.192 ;
     RECT  14.893 64.464 15.937 66.888 ;
     RECT  15.397 68.016 15.937 71.496 ;
     RECT  15.937 19.92 15.973 46.632 ;
     RECT  15.937 47.664 15.973 57.192 ;
     RECT  15.937 64.464 15.973 71.496 ;
     RECT  15.757 72.528 15.973 76.68 ;
     RECT  15.973 19.92 16.405 57.192 ;
     RECT  16.405 19.92 17.244 57.48 ;
     RECT  15.973 64.464 17.244 76.68 ;
    LAYER M5 ;
     RECT  3.984 0.016 4.104 1.763 ;
     RECT  2.4 2.137 2.52 2.151 ;
     RECT  7.8 2.137 7.92 2.151 ;
     RECT  13.2 2.137 13.32 2.151 ;
     RECT  13.2 2.151 13.512 5.461 ;
     RECT  12.528 5.461 13.512 6.323 ;
     RECT  12.672 6.323 13.512 7.381 ;
     RECT  12.672 7.381 13.752 7.427 ;
     RECT  7.8 2.151 8.112 7.957 ;
     RECT  11.376 7.621 11.4 9.781 ;
     RECT  10.944 9.781 11.4 9.827 ;
     RECT  12.96 7.427 13.752 9.925 ;
     RECT  10.944 9.827 10.968 10.355 ;
     RECT  2.4 2.151 2.712 11.509 ;
     RECT  10.848 11.365 10.872 12.757 ;
     RECT  2.4 11.509 2.808 13.045 ;
     RECT  7.8 7.957 8.808 13.621 ;
     RECT  7.8 13.621 9.336 14.197 ;
     RECT  7.056 14.197 9.336 14.387 ;
     RECT  12.96 9.925 14.232 14.485 ;
     RECT  7.056 14.387 8.616 14.915 ;
     RECT  7.056 14.915 8.112 15.349 ;
     RECT  6.864 15.349 8.112 15.875 ;
     RECT  10.32 12.757 10.872 16.019 ;
     RECT  2.4 13.045 2.904 16.309 ;
     RECT  2.4 16.309 2.952 16.357 ;
     RECT  3.984 1.763 4.008 16.357 ;
     RECT  10.32 16.019 10.344 16.499 ;
     RECT  5.04 14.773 5.064 16.595 ;
     RECT  2.4 16.357 4.008 16.645 ;
     RECT  2.304 16.645 4.008 18.131 ;
     RECT  12.528 14.485 14.232 18.181 ;
     RECT  2.4 18.131 4.008 18.947 ;
     RECT  9.744 18.565 9.768 19.093 ;
     RECT  9.744 19.093 10.056 19.139 ;
     RECT  10.032 19.139 10.056 19.621 ;
     RECT  10.032 19.621 11.016 19.955 ;
     RECT  12 18.181 14.232 20.003 ;
     RECT  2.4 18.947 2.952 20.053 ;
     RECT  3.984 18.947 4.008 20.965 ;
     RECT  10.992 19.955 11.016 21.013 ;
     RECT  1.968 20.053 2.952 21.157 ;
     RECT  6.912 15.875 8.112 21.395 ;
     RECT  10.8 21.013 11.016 21.541 ;
     RECT  12.192 20.003 14.232 21.683 ;
     RECT  0.144 21.733 0.168 21.923 ;
     RECT  7.68 21.395 8.112 22.165 ;
     RECT  1.968 21.157 3 22.211 ;
     RECT  10.8 21.541 11.064 22.307 ;
     RECT  11.04 22.307 11.064 22.691 ;
     RECT  12.192 21.683 13.512 22.693 ;
     RECT  12 22.693 13.512 22.835 ;
     RECT  7.68 22.165 8.616 22.883 ;
     RECT  12.192 22.835 12.216 23.411 ;
     RECT  11.136 23.845 11.16 24.371 ;
     RECT  1.968 22.211 2.952 24.659 ;
     RECT  9.984 22.645 10.008 24.659 ;
     RECT  3.984 20.965 4.92 25.091 ;
     RECT  1.968 24.659 2.712 25.861 ;
     RECT  10.272 25.621 10.296 26.531 ;
     RECT  7.68 22.883 8.112 26.533 ;
     RECT  3.984 25.091 4.008 26.773 ;
     RECT  6.384 22.789 6.408 26.819 ;
     RECT  1.968 25.861 2.856 26.867 ;
     RECT  11.52 27.685 11.544 28.211 ;
     RECT  7.68 26.533 8.232 28.307 ;
     RECT  3.984 26.773 4.632 28.499 ;
     RECT  0.144 28.597 0.168 28.787 ;
     RECT  1.968 26.867 2.808 29.605 ;
     RECT  3.984 28.499 4.008 29.605 ;
     RECT  7.68 28.307 8.112 29.605 ;
     RECT  1.968 29.605 4.008 30.131 ;
     RECT  7.68 29.605 8.424 30.467 ;
     RECT  5.088 29.605 5.112 30.565 ;
     RECT  5.088 30.565 5.208 30.611 ;
     RECT  11.04 30.661 11.064 30.803 ;
     RECT  0.24 30.373 0.264 31.139 ;
     RECT  2.304 30.131 4.008 31.235 ;
     RECT  9.888 29.893 9.912 31.379 ;
     RECT  5.184 30.611 5.208 32.771 ;
     RECT  5.232 33.013 5.256 33.299 ;
     RECT  7.8 30.467 8.424 33.539 ;
     RECT  2.4 31.235 4.008 34.357 ;
     RECT  0.144 34.453 0.168 34.739 ;
     RECT  5.088 34.549 5.112 35.413 ;
     RECT  7.8 33.539 8.328 35.845 ;
     RECT  2.304 34.357 4.008 36.515 ;
     RECT  13.2 22.835 13.512 36.565 ;
     RECT  13.2 36.565 13.704 36.707 ;
     RECT  5.088 35.413 5.736 37.091 ;
     RECT  0.192 36.949 0.216 37.381 ;
     RECT  0.144 37.381 0.216 37.667 ;
     RECT  7.8 35.845 8.904 37.859 ;
     RECT  0.192 37.667 0.216 38.051 ;
     RECT  5.712 37.091 5.736 38.099 ;
     RECT  7.8 37.859 8.712 39.923 ;
     RECT  6.24 38.773 6.264 40.405 ;
     RECT  7.8 39.923 8.328 40.405 ;
     RECT  6.24 40.405 8.328 40.451 ;
     RECT  2.4 36.515 4.008 41.029 ;
     RECT  2.4 41.029 4.584 41.075 ;
     RECT  10.368 38.005 10.392 41.075 ;
     RECT  6.912 40.451 8.328 42.467 ;
     RECT  3.984 41.075 4.584 42.803 ;
     RECT  4.08 42.803 4.584 42.899 ;
     RECT  7.632 42.467 8.328 43.285 ;
     RECT  2.4 41.075 2.712 43.861 ;
     RECT  4.08 42.899 4.104 43.861 ;
     RECT  0.144 44.101 0.168 44.483 ;
     RECT  7.632 43.285 9.096 44.483 ;
     RECT  2.4 43.861 4.104 45.635 ;
     RECT  5.712 43.861 5.736 45.683 ;
     RECT  7.632 44.483 8.328 46.501 ;
     RECT  9.6 45.541 9.624 46.645 ;
     RECT  9.6 46.645 10.296 46.691 ;
     RECT  7.296 46.501 8.328 46.787 ;
     RECT  10.272 46.691 10.296 46.787 ;
     RECT  4.08 45.635 4.104 46.883 ;
     RECT  7.8 46.787 8.328 47.845 ;
     RECT  2.4 45.635 2.712 48.373 ;
     RECT  0.288 48.709 0.312 48.805 ;
     RECT  0.144 48.805 0.312 48.851 ;
     RECT  0.144 48.851 0.168 48.995 ;
     RECT  4.608 46.933 4.632 48.995 ;
     RECT  2.4 48.373 2.808 49.571 ;
     RECT  7.8 47.845 8.808 50.389 ;
     RECT  10.272 48.421 10.296 50.771 ;
     RECT  4.56 49.333 4.584 51.205 ;
     RECT  4.368 51.205 4.584 51.251 ;
     RECT  10.368 51.781 10.392 53.459 ;
     RECT  13.2 36.707 13.512 53.509 ;
     RECT  4.368 51.251 4.392 53.603 ;
     RECT  7.152 50.389 8.808 54.371 ;
     RECT  13.2 53.509 13.656 54.707 ;
     RECT  12.192 51.781 12.216 55.813 ;
     RECT  13.2 54.707 13.512 55.813 ;
     RECT  12.192 55.813 13.512 56.101 ;
     RECT  2.4 49.571 2.712 56.965 ;
     RECT  11.328 56.101 13.512 56.965 ;
     RECT  0.144 57.349 0.168 57.539 ;
     RECT  6.528 54.661 6.552 57.589 ;
     RECT  7.8 54.371 8.808 57.589 ;
     RECT  6.528 57.589 8.808 57.635 ;
     RECT  10.368 56.965 13.512 57.635 ;
     RECT  2.4 56.965 2.808 57.683 ;
     RECT  6.816 57.635 8.808 58.069 ;
     RECT  6.816 58.069 9.048 58.787 ;
     RECT  2.4 57.683 2.712 58.933 ;
     RECT  2.4 58.933 2.952 59.029 ;
     RECT  2.4 59.029 3.048 59.219 ;
     RECT  4.128 56.101 4.152 59.797 ;
     RECT  4.032 59.797 4.152 59.843 ;
     RECT  7.584 58.787 9.048 60.277 ;
     RECT  10.32 58.117 10.344 60.323 ;
     RECT  11.424 57.635 13.512 60.563 ;
     RECT  5.712 59.221 5.736 61.571 ;
     RECT  7.584 60.277 9.24 62.675 ;
     RECT  12.048 60.563 13.512 62.821 ;
     RECT  7.584 62.675 8.112 63.107 ;
     RECT  4.032 59.843 4.056 63.205 ;
     RECT  5.328 62.293 5.352 63.205 ;
     RECT  9.216 62.675 9.24 63.299 ;
     RECT  0.24 62.437 0.264 63.347 ;
     RECT  4.032 63.205 5.352 63.491 ;
     RECT  12 62.821 13.512 63.635 ;
     RECT  4.992 63.491 5.352 64.451 ;
     RECT  6.576 63.781 6.6 64.931 ;
     RECT  9.12 63.781 9.144 64.979 ;
     RECT  12.192 63.635 13.512 64.979 ;
     RECT  2.4 59.219 2.904 65.027 ;
     RECT  4.992 64.451 5.112 65.411 ;
     RECT  3.984 63.781 4.008 66.179 ;
     RECT  7.68 63.107 8.112 66.709 ;
     RECT  9.84 65.845 9.864 66.755 ;
     RECT  10.944 66.325 10.968 67.331 ;
     RECT  6.816 66.709 8.112 68.339 ;
     RECT  5.088 65.411 5.112 69.011 ;
     RECT  10.56 68.341 10.584 69.539 ;
     RECT  2.4 65.027 2.712 70.117 ;
     RECT  1.968 70.117 2.712 70.501 ;
     RECT  7.68 68.339 8.112 70.645 ;
     RECT  0.144 70.357 0.168 71.267 ;
     RECT  7.68 70.645 8.52 71.315 ;
     RECT  4.56 71.221 4.584 71.843 ;
     RECT  12.24 64.979 13.512 72.419 ;
     RECT  12.384 72.419 13.512 72.661 ;
     RECT  1.968 70.501 3.048 72.949 ;
     RECT  7.68 71.315 8.112 73.381 ;
     RECT  1.968 72.949 3.576 73.475 ;
     RECT  7.68 73.381 8.472 74.005 ;
     RECT  5.952 73.477 5.976 74.245 ;
     RECT  5.952 74.245 6.12 74.291 ;
     RECT  1.968 73.475 3.048 74.485 ;
     RECT  12.384 72.661 13.848 74.485 ;
     RECT  12.288 74.485 13.848 74.627 ;
     RECT  7.44 74.005 8.472 74.963 ;
     RECT  9.744 71.797 9.768 74.965 ;
     RECT  1.968 74.485 3.96 75.011 ;
     RECT  9.504 74.965 9.768 75.011 ;
     RECT  6.096 74.291 6.12 75.203 ;
     RECT  12.384 74.627 13.848 76.309 ;
     RECT  7.44 74.963 8.112 76.933 ;
     RECT  1.968 75.011 3.192 76.981 ;
     RECT  7.056 76.933 8.112 77.795 ;
     RECT  11.904 76.309 13.848 77.797 ;
     RECT  7.44 77.795 8.112 77.843 ;
     RECT  1.968 76.981 3.288 78.853 ;
     RECT  1.968 78.853 3.912 78.899 ;
     RECT  7.8 77.843 8.112 79.189 ;
     RECT  1.968 78.899 2.712 79.283 ;
     RECT  5.568 77.701 5.592 79.283 ;
     RECT  3.888 78.899 3.912 79.427 ;
     RECT  11.28 77.797 13.848 79.715 ;
     RECT  9.504 75.011 9.528 79.955 ;
     RECT  2.4 79.283 2.712 80.293 ;
     RECT  5.664 79.717 5.688 80.435 ;
     RECT  11.28 79.715 11.304 80.483 ;
     RECT  12.384 79.715 13.848 81.203 ;
     RECT  7.8 79.189 8.232 81.587 ;
     RECT  2.4 80.293 3.432 82.115 ;
     RECT  11.136 82.597 11.16 83.411 ;
     RECT  12.576 81.203 13.848 84.181 ;
     RECT  12.528 84.181 13.848 84.803 ;
     RECT  11.088 84.325 11.112 85.477 ;
     RECT  10.848 85.477 11.112 85.523 ;
     RECT  12.528 84.803 13.8 85.523 ;
     RECT  12.576 85.523 13.8 86.005 ;
     RECT  12.576 86.005 13.848 86.963 ;
     RECT  13.2 86.963 13.848 87.155 ;
     RECT  10.848 85.523 10.872 87.251 ;
     RECT  12.144 87.109 12.168 87.827 ;
     RECT  13.2 87.155 13.704 87.827 ;
     RECT  2.4 82.115 2.712 95.049 ;
     RECT  7.8 81.587 8.112 95.049 ;
     RECT  13.2 87.827 13.512 95.049 ;
     RECT  2.4 95.049 2.52 95.063 ;
     RECT  7.8 95.049 7.92 95.063 ;
     RECT  13.2 95.049 13.32 95.063 ;
     RECT  2.52 2.137 3.984 2.151 ;
     RECT  2.712 2.151 3.984 11.509 ;
     RECT  2.808 11.509 3.984 13.045 ;
     RECT  8.808 12.757 10.32 13.621 ;
     RECT  2.904 13.045 3.984 16.309 ;
     RECT  9.336 13.621 10.32 14.387 ;
     RECT  4.008 14.773 5.04 16.595 ;
     RECT  2.952 16.309 3.984 16.357 ;
     RECT  2.952 18.947 3.984 21.157 ;
     RECT  11.016 19.621 12 20.003 ;
     RECT  10.8 19.955 10.992 21.013 ;
     RECT  11.016 20.003 12.192 21.541 ;
     RECT  3 21.157 3.984 22.211 ;
     RECT  6.912 21.395 7.68 22.789 ;
     RECT  11.064 21.541 12.192 22.691 ;
     RECT  2.952 22.211 3.984 24.659 ;
     RECT  10.8 22.307 11.04 22.645 ;
     RECT  8.616 22.645 9.984 22.883 ;
     RECT  10.008 22.645 11.04 22.691 ;
     RECT  10.008 22.691 12.192 22.693 ;
     RECT  10.008 22.693 12 22.835 ;
     RECT  4.92 22.789 6.384 25.091 ;
     RECT  6.408 22.789 7.68 26.819 ;
     RECT  10.008 22.835 12.192 23.411 ;
     RECT  12.216 22.835 13.2 23.411 ;
     RECT  10.008 23.411 11.16 23.845 ;
     RECT  10.008 23.845 11.136 24.371 ;
     RECT  10.008 24.371 10.296 24.659 ;
     RECT  2.712 24.659 3.984 25.861 ;
     RECT  10.272 24.659 10.296 25.621 ;
     RECT  2.856 25.861 3.984 26.867 ;
     RECT  2.808 26.867 3.984 29.605 ;
     RECT  8.112 28.307 8.232 29.605 ;
     RECT  4.008 28.499 4.632 29.605 ;
     RECT  4.008 29.605 5.088 30.611 ;
     RECT  8.424 29.893 9.888 31.379 ;
     RECT  4.008 30.611 5.184 32.771 ;
     RECT  9.912 30.661 11.04 30.803 ;
     RECT  4.008 32.771 5.208 33.013 ;
     RECT  4.008 33.013 5.232 33.299 ;
     RECT  4.008 33.299 5.112 34.549 ;
     RECT  4.008 34.549 5.088 37.091 ;
     RECT  2.712 41.075 3.984 42.803 ;
     RECT  2.712 42.803 4.08 43.861 ;
     RECT  8.328 44.483 9.096 45.541 ;
     RECT  8.328 45.541 9.6 46.691 ;
     RECT  2.712 45.635 4.08 46.883 ;
     RECT  8.328 46.691 10.272 46.787 ;
     RECT  8.328 46.787 8.808 47.845 ;
     RECT  2.712 46.883 2.808 48.373 ;
     RECT  8.808 48.421 10.272 50.771 ;
     RECT  12.216 51.781 13.2 55.813 ;
     RECT  7.152 54.371 7.8 54.661 ;
     RECT  6.552 54.661 7.8 57.589 ;
     RECT  2.712 56.101 4.128 56.965 ;
     RECT  2.808 56.965 4.128 57.683 ;
     RECT  10.368 57.635 11.424 58.069 ;
     RECT  2.712 57.683 4.128 58.933 ;
     RECT  9.048 58.069 11.424 58.117 ;
     RECT  9.048 58.117 10.32 60.277 ;
     RECT  10.344 58.117 11.424 60.323 ;
     RECT  2.952 58.933 4.128 59.029 ;
     RECT  3.048 59.029 4.128 59.219 ;
     RECT  2.904 59.219 4.128 59.797 ;
     RECT  2.904 59.797 4.032 63.491 ;
     RECT  9.24 60.277 10.32 60.323 ;
     RECT  4.056 62.293 5.328 63.205 ;
     RECT  8.112 62.675 9.216 63.299 ;
     RECT  7.584 63.107 7.68 63.781 ;
     RECT  8.112 63.299 9.144 63.781 ;
     RECT  2.904 63.491 4.992 63.781 ;
     RECT  2.904 63.781 3.984 65.027 ;
     RECT  4.008 63.781 4.992 65.411 ;
     RECT  5.352 63.781 6.576 64.451 ;
     RECT  6.6 63.781 7.68 64.931 ;
     RECT  8.112 63.781 9.12 64.979 ;
     RECT  5.112 64.451 6.576 64.931 ;
     RECT  12.192 64.979 12.24 66.325 ;
     RECT  2.712 65.027 3.984 66.179 ;
     RECT  4.008 65.411 5.088 66.179 ;
     RECT  9.864 66.325 10.944 66.755 ;
     RECT  10.968 66.325 12.24 67.331 ;
     RECT  3.048 71.221 4.56 71.843 ;
     RECT  3.048 71.843 3.576 72.949 ;
     RECT  8.472 73.381 9.744 74.963 ;
     RECT  3.048 73.475 3.576 74.485 ;
     RECT  5.976 74.005 7.44 74.245 ;
     RECT  6.12 74.245 7.44 75.203 ;
     RECT  8.112 74.963 9.744 74.965 ;
     RECT  8.112 74.965 9.504 79.189 ;
     RECT  5.592 77.701 7.056 77.795 ;
     RECT  2.712 78.899 3.888 79.427 ;
     RECT  8.232 79.189 9.504 79.955 ;
     RECT  2.712 79.427 3.432 80.293 ;
     RECT  11.304 79.715 12.384 80.483 ;
     RECT  12.384 81.203 12.576 82.597 ;
     RECT  11.16 82.597 12.576 83.411 ;
     RECT  11.136 83.411 12.576 84.181 ;
     RECT  11.136 84.181 12.528 84.325 ;
     RECT  11.112 84.325 12.528 85.523 ;
     RECT  13.8 84.803 13.848 86.005 ;
     RECT  12.576 86.963 13.2 87.109 ;
     RECT  10.872 87.109 12.144 87.251 ;
     RECT  12.168 87.109 13.2 87.827 ;
  END
END ot_qfd_vm_xrelay_t
END LIBRARY
